# iorx65n register map
Registers from a debugger description file.
Registers are 8-bit, access not given, no defined reset value unless marked. A register's access mark holds for its fields unless they carry their own. Addresses are absolute; registers are grouped by the start of their names; lines under a group give offsets from that group; [hi:lo] are bit positions; {n}, {i} and the like mark numbered series; 'fields as' and 'values as' point back to an identical list; <NAME> marks a mode.

## SFR (part 1 of 7)
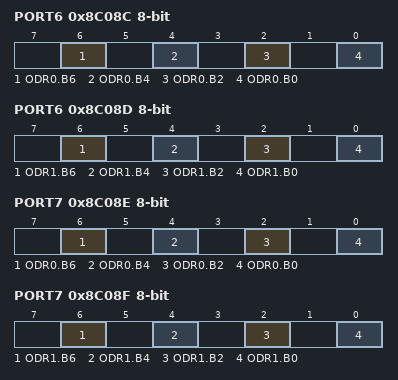
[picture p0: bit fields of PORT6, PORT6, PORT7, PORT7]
0x8C08C PORT6
  [6] ODR0.B6, [4] ODR0.B4, [2] ODR0.B2, [0] ODR0.B0
0x8C08D PORT6
  [6] ODR1.B6, [4] ODR1.B4, [2] ODR1.B2, [0] ODR1.B0
0x8C08E PORT7
  [6] ODR0.B6, [4] ODR0.B4, [2] ODR0.B2, [0] ODR0.B0
0x8C08F PORT7
  [6] ODR1.B6, [4] ODR1.B4, [2] ODR1.B2, [0] ODR1.B0
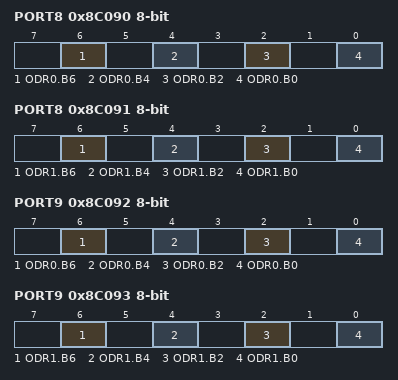
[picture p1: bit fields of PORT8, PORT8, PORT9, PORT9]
0x8C090 PORT8
  [6] ODR0.B6, [4] ODR0.B4, [2] ODR0.B2, [0] ODR0.B0
0x8C091 PORT8
  [6] ODR1.B6, [4] ODR1.B4, [2] ODR1.B2, [0] ODR1.B0
0x8C092 PORT9
  [6] ODR0.B6, [4] ODR0.B4, [2] ODR0.B2, [0] ODR0.B0
0x8C093 PORT9
  [6] ODR1.B6, [4] ODR1.B4, [2] ODR1.B2, [0] ODR1.B0
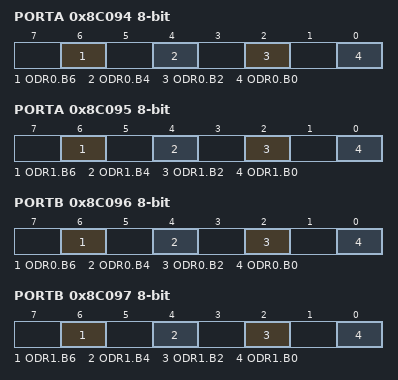
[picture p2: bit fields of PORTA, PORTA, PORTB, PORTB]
0x8C094 PORTA
  [6] ODR0.B6, [4] ODR0.B4, [2] ODR0.B2, [0] ODR0.B0
0x8C095 PORTA
  [6] ODR1.B6, [4] ODR1.B4, [2] ODR1.B2, [0] ODR1.B0
0x8C096 PORTB
  [6] ODR0.B6, [4] ODR0.B4, [2] ODR0.B2, [0] ODR0.B0
0x8C097 PORTB
  [6] ODR1.B6, [4] ODR1.B4, [2] ODR1.B2, [0] ODR1.B0
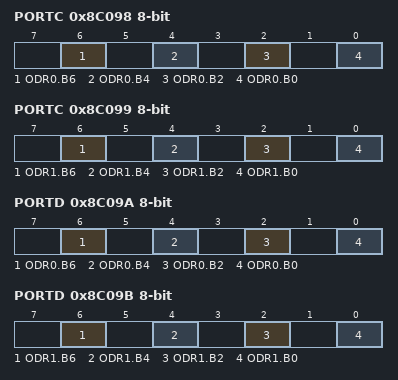
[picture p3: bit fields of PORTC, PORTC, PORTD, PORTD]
0x8C098 PORTC
  [6] ODR0.B6, [4] ODR0.B4, [2] ODR0.B2, [0] ODR0.B0
0x8C099 PORTC
  [6] ODR1.B6, [4] ODR1.B4, [2] ODR1.B2, [0] ODR1.B0
0x8C09A PORTD
  [6] ODR0.B6, [4] ODR0.B4, [2] ODR0.B2, [0] ODR0.B0
0x8C09B PORTD
  [6] ODR1.B6, [4] ODR1.B4, [2] ODR1.B2, [0] ODR1.B0
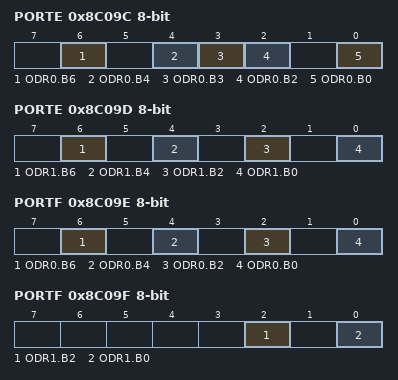
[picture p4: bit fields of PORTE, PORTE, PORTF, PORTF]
0x8C09C PORTE
  [6] ODR0.B6, [4] ODR0.B4, [3] ODR0.B3, [2] ODR0.B2, [0] ODR0.B0
0x8C09D PORTE
  [6] ODR1.B6, [4] ODR1.B4, [2] ODR1.B2, [0] ODR1.B0
0x8C09E PORTF
  [6] ODR0.B6, [4] ODR0.B4, [2] ODR0.B2, [0] ODR0.B0
0x8C09F PORTF
  [2] ODR1.B2, [0] ODR1.B0
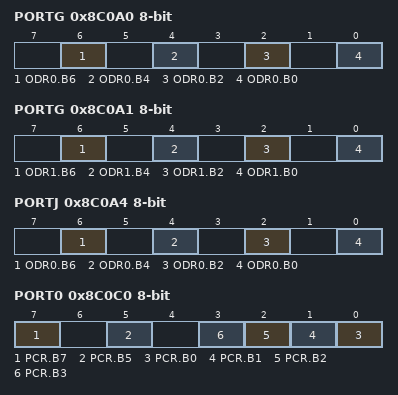
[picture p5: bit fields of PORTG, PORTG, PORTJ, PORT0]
0x8C0A0 PORTG
  [6] ODR0.B6, [4] ODR0.B4, [2] ODR0.B2, [0] ODR0.B0
0x8C0A1 PORTG
  [6] ODR1.B6, [4] ODR1.B4, [2] ODR1.B2, [0] ODR1.B0
0x8C0A4 PORTJ
  [6] ODR0.B6, [4] ODR0.B4, [2] ODR0.B2, [0] ODR0.B0
0x8C0A5 PORTJ
  [2] ODR1.B2
0x8C0C0 PORT0
  [7] PCR.B7, [5] PCR.B5, [n] PCR.B{n} (n=0..3)
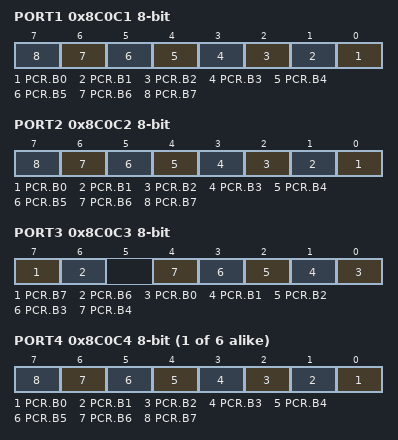
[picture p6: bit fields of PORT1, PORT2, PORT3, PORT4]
0x8C0C1 PORT1
  [n] PCR.B{n} (n=0..7)
0x8C0C2 PORT2
  [n] PCR.B{n} (n=0..7)
0x8C0C3 PORT3
  [7] PCR.B7, [6] PCR.B6, [n] PCR.B{n} (n=0..4)
{0x8C0C0+i} PORT{i} (i=4..9)
  [n] PCR.B{n} (n=0..7)
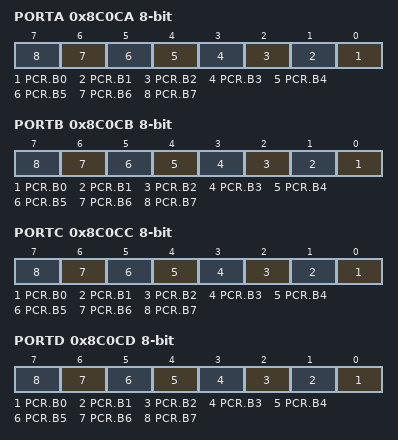
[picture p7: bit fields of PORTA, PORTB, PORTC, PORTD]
0x8C0CA PORTA
  [n] PCR.B{n} (n=0..7)
0x8C0CB PORTB
  [n] PCR.B{n} (n=0..7)
0x8C0CC PORTC
  [n] PCR.B{n} (n=0..7)
0x8C0CD PORTD
  [n] PCR.B{n} (n=0..7)
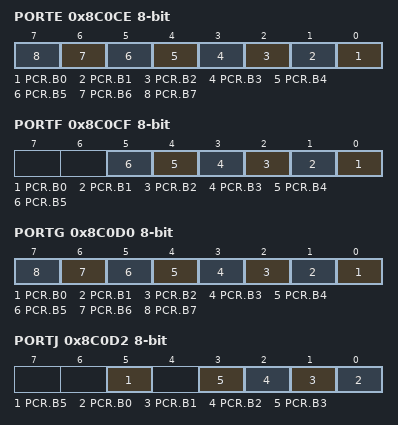
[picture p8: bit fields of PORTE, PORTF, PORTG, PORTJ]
0x8C0CE PORTE
  [n] PCR.B{n} (n=0..7)
0x8C0CF PORTF
  [n] PCR.B{n} (n=0..5)
0x8C0D0 PORTG
  [n] PCR.B{n} (n=0..7)
0x8C0D2 PORTJ
  [5] PCR.B5, [n] PCR.B{n} (n=0..3)
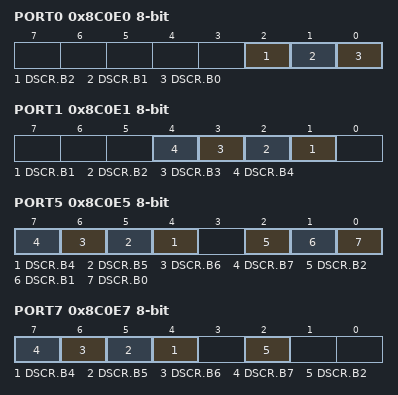
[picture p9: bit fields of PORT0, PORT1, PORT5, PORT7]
0x8C0E0 PORT0
  [2] DSCR.B2, [1] DSCR.B1, [0] DSCR.B0
0x8C0E1 PORT1
  [n] DSCR.B{n} (n=1..4)
0x8C0E2 PORT2
  [7] DSCR.B7
0x8C0E5 PORT5
  [n] DSCR.B{n} (n=4..7), [2] DSCR.B2, [1] DSCR.B1, [0] DSCR.B0
0x8C0E7 PORT7
  [n] DSCR.B{n} (n=4..7), [2] DSCR.B2
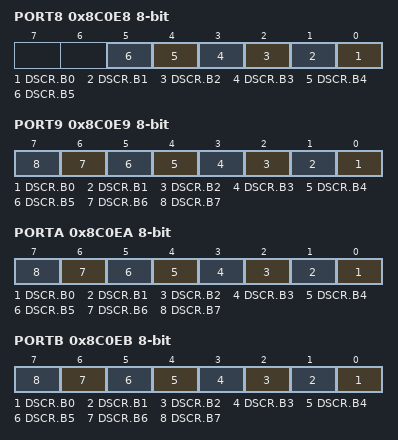
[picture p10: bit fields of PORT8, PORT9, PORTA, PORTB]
0x8C0E8 PORT8
  [n] DSCR.B{n} (n=0..5)
0x8C0E9 PORT9
  [n] DSCR.B{n} (n=0..7)
0x8C0EA PORTA
  [n] DSCR.B{n} (n=0..7)
0x8C0EB PORTB
  [n] DSCR.B{n} (n=0..7)
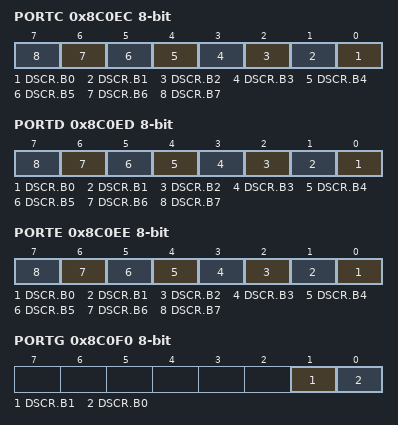
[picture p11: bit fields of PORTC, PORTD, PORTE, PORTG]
0x8C0EC PORTC
  [n] DSCR.B{n} (n=0..7)
0x8C0ED PORTD
  [n] DSCR.B{n} (n=0..7)
0x8C0EE PORTE
  [n] DSCR.B{n} (n=0..7)
0x8C0F0 PORTG
  [1] DSCR.B1, [0] DSCR.B0
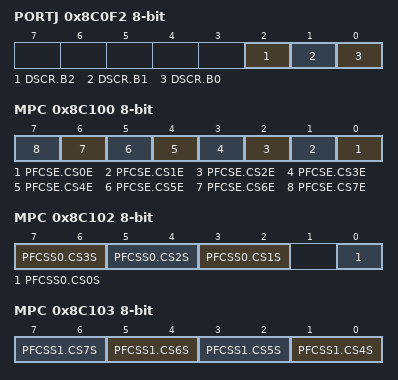
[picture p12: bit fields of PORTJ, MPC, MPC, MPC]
0x8C0F2 PORTJ
  [2] DSCR.B2, [1] DSCR.B1, [0] DSCR.B0
0x8C100 MPC
  [n] PFCSE.CS{n}E (n=0..7)
0x8C102 MPC
  [7:6] PFCSS0.CS3S, [5:4] PFCSS0.CS2S, [3:2] PFCSS0.CS1S, [0] PFCSS0.CS0S
0x8C103 MPC
  [2n-7:2n-8] PFCSS1.CS{n}S (n=4..7)
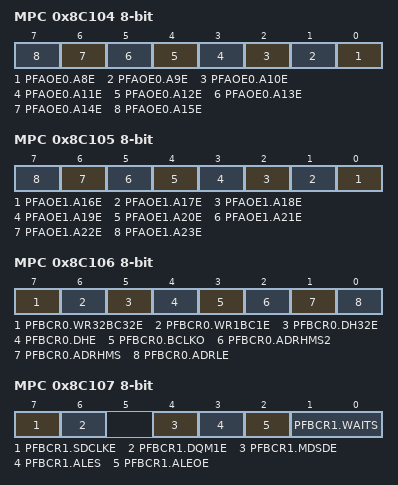
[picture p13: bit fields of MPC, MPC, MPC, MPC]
0x8C104 MPC
  [n-8] PFAOE0.A{n}E (n=8..15)
0x8C105 MPC
  [n-16] PFAOE1.A{n}E (n=16..23)
0x8C106 MPC
  [7] PFBCR0.WR32BC32E, [6] PFBCR0.WR1BC1E, [5] PFBCR0.DH32E, [4] PFBCR0.DHE, [3] PFBCR0.BCLKO, [2] PFBCR0.ADRHMS2, [1] PFBCR0.ADRHMS, [0] PFBCR0.ADRLE
0x8C107 MPC
  [7] PFBCR1.SDCLKE, [6] PFBCR1.DQM1E, [4] PFBCR1.MDSDE, [3] PFBCR1.ALES, [2] PFBCR1.ALEOE, [1:0] PFBCR1.WAITS
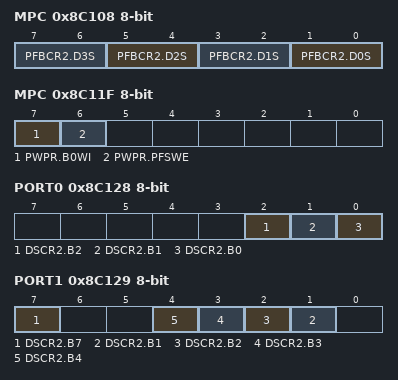
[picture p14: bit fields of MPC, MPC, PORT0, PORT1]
0x8C108 MPC
  [2n+1:2n] PFBCR2.D{n}S (n=0..3)
0x8C109 MPC
  [0] PFBCR3.DLHS
0x8C10E MPC
  [4] PFENET.PHYMODE0
0x8C11F MPC
  [7] PWPR.B0WI, [6] PWPR.PFSWE
0x8C128 PORT0
  [2] DSCR2.B2, [1] DSCR2.B1, [0] DSCR2.B0
0x8C129 PORT1
  [7] DSCR2.B7, [n] DSCR2.B{n} (n=1..4)
0x8C12A PORT2
  [7] DSCR2.B7, [n] DSCR2.B{n} (n=0..3)
0x8C12B PORT3
  [1] DSCR2.B1, [0] DSCR2.B0
0x8C12D PORT5
  [n] DSCR2.B{n} (n=0..7)
0x8C12F PORT7
  [n] DSCR2.B{n} (n=2..7), [0] DSCR2.B0
0x8C130 PORT8
  [7] DSCR2.B7, [n] DSCR2.B{n} (n=0..5)
0x8C131 PORT9
  [n] DSCR2.B{n} (n=0..7)
0x8C132 PORTA
  [n] DSCR2.B{n} (n=0..7)
0x8C133 PORTB
  [n] DSCR2.B{n} (n=0..7)
0x8C134 PORTC
  [n] DSCR2.B{n} (n=0..7)
0x8C135 PORTD
  [n] DSCR2.B{n} (n=0..7)
0x8C136 PORTE
  [n] DSCR2.B{n} (n=0..7)
0x8C138 PORTG
  [n] DSCR2.B{n} (n=0..7)
0x8C13A PORTJ
  [2] DSCR2.B2, [1] DSCR2.B1, [0] DSCR2.B0
0x8C140 MPC
  [7] P00PFS.ASEL, [6] P00PFS.ISEL, [5:0] P00PFS.PSEL
0x8C141 MPC
  [7] P01PFS.ASEL, [6] P01PFS.ISEL, [5:0] P01PFS.PSEL
0x8C142 MPC
  [7] P02PFS.ASEL, [6] P02PFS.ISEL, [5:0] P02PFS.PSEL
0x8C143 MPC
  [7] P03PFS.ASEL, [6] P03PFS.ISEL
0x8C145 MPC
  [7] P05PFS.ASEL, [6] P05PFS.ISEL
0x8C147 MPC
  [6] P07PFS.ISEL, [5:0] P07PFS.PSEL
0x8C148 MPC
  [6] P10PFS.ISEL, [5:0] P10PFS.PSEL
0x8C149 MPC
  [6] P11PFS.ISEL, [5:0] P11PFS.PSEL
0x8C14A MPC
  [6] P12PFS.ISEL, [5:0] P12PFS.PSEL
0x8C14B MPC
  [6] P13PFS.ISEL, [5:0] P13PFS.PSEL
0x8C14C MPC
  [6] P14PFS.ISEL, [5:0] P14PFS.PSEL
0x8C14D MPC
  [6] P15PFS.ISEL, [5:0] P15PFS.PSEL
0x8C14E MPC
  [6] P16PFS.ISEL, [5:0] P16PFS.PSEL
0x8C14F MPC
  [6] P17PFS.ISEL, [5:0] P17PFS.PSEL
0x8C150 MPC
  [6] P20PFS.ISEL, [5:0] P20PFS.PSEL
0x8C151 MPC
  [6] P21PFS.ISEL, [5:0] P21PFS.PSEL
0x8C152 MPC
  [5:0] P22PFS.PSEL
0x8C153 MPC
  [5:0] P23PFS.PSEL
0x8C154 MPC
  [5:0] P24PFS.PSEL
0x8C155 MPC
  [5:0] P25PFS.PSEL
0x8C156 MPC
  [5:0] P26PFS.PSEL
0x8C157 MPC
  [5:0] P27PFS.PSEL
0x8C158 MPC
  [6] P30PFS.ISEL, [5:0] P30PFS.PSEL
0x8C159 MPC
  [6] P31PFS.ISEL, [5:0] P31PFS.PSEL
0x8C15A MPC
  [6] P32PFS.ISEL, [5:0] P32PFS.PSEL
0x8C15B MPC
  [6] P33PFS.ISEL, [5:0] P33PFS.PSEL
0x8C15C MPC
  [6] P34PFS.ISEL, [5:0] P34PFS.PSEL
0x8C160 MPC
  [7] P40PFS.ASEL, [6] P40PFS.ISEL
0x8C161 MPC
  [7] P41PFS.ASEL, [6] P41PFS.ISEL
0x8C162 MPC
  [7] P42PFS.ASEL, [6] P42PFS.ISEL
0x8C163 MPC
  [7] P43PFS.ASEL, [6] P43PFS.ISEL
0x8C164 MPC
  [7] P44PFS.ASEL, [6] P44PFS.ISEL
0x8C165 MPC
  [7] P45PFS.ASEL, [6] P45PFS.ISEL
0x8C166 MPC
  [7] P46PFS.ASEL, [6] P46PFS.ISEL
0x8C167 MPC
  [7] P47PFS.ASEL, [6] P47PFS.ISEL
0x8C168 MPC
  [5:0] P50PFS.PSEL
0x8C169 MPC
  [5:0] P51PFS.PSEL
0x8C16A MPC
  [5:0] P52PFS.PSEL
0x8C16C MPC
  [5:0] P54PFS.PSEL
0x8C16D MPC
  [6] P55PFS.ISEL, [5:0] P55PFS.PSEL
0x8C16E MPC
  [5:0] P56PFS.PSEL
0x8C16F MPC
  [5:0] P57PFS.PSEL
0x8C176 MPC
  [5:0] P66PFS.PSEL
0x8C177 MPC
  [6] P67PFS.ISEL, [5:0] P67PFS.PSEL
0x8C179 MPC
  [5:0] P71PFS.PSEL
0x8C17A MPC
  [5:0] P72PFS.PSEL
0x8C17B MPC
  [5:0] P73PFS.PSEL
0x8C17C MPC
  [5:0] P74PFS.PSEL
0x8C17D MPC
  [5:0] P75PFS.PSEL
0x8C17E MPC
  [5:0] P76PFS.PSEL
0x8C17F MPC
  [5:0] P77PFS.PSEL
0x8C180 MPC
  [5:0] P80PFS.PSEL
0x8C181 MPC
  [5:0] P81PFS.PSEL
0x8C182 MPC
  [5:0] P82PFS.PSEL
0x8C183 MPC
  [5:0] P83PFS.PSEL
0x8C184 MPC
  [5:0] P84PFS.PSEL
0x8C185 MPC
  [5:0] P85PFS.PSEL
0x8C186 MPC
  [5:0] P86PFS.PSEL
0x8C187 MPC
  [5:0] P87PFS.PSEL
0x8C188 MPC
  [7] P90PFS.ASEL, [5:0] P90PFS.PSEL
0x8C189 MPC
  [7] P91PFS.ASEL, [5:0] P91PFS.PSEL
0x8C18A MPC
  [7] P92PFS.ASEL, [5:0] P92PFS.PSEL
0x8C18B MPC
  [7] P93PFS.ASEL, [5:0] P93PFS.PSEL
0x8C190 MPC
  [5:0] PA0PFS.PSEL
0x8C191 MPC
  [6] PA1PFS.ISEL, [5:0] PA1PFS.PSEL
0x8C192 MPC
  [5:0] PA2PFS.PSEL
0x8C193 MPC
  [6] PA3PFS.ISEL, [5:0] PA3PFS.PSEL
0x8C194 MPC
  [6] PA4PFS.ISEL, [5:0] PA4PFS.PSEL
0x8C195 MPC
  [5:0] PA5PFS.PSEL
0x8C196 MPC
  [5:0] PA6PFS.PSEL
0x8C197 MPC
  [5:0] PA7PFS.PSEL
0x8C198 MPC
  [6] PB0PFS.ISEL, [5:0] PB0PFS.PSEL
0x8C199 MPC
  [6] PB1PFS.ISEL, [5:0] PB1PFS.PSEL
0x8C19A MPC
  [5:0] PB2PFS.PSEL
0x8C19B MPC
  [5:0] PB3PFS.PSEL
0x8C19C MPC
  [5:0] PB4PFS.PSEL
0x8C19D MPC
  [5:0] PB5PFS.PSEL
0x8C19E MPC
  [5:0] PB6PFS.PSEL
0x8C19F MPC
  [5:0] PB7PFS.PSEL
0x8C1A0 MPC
  [6] PC0PFS.ISEL, [5:0] PC0PFS.PSEL
0x8C1A1 MPC
  [6] PC1PFS.ISEL, [5:0] PC1PFS.PSEL
0x8C1A2 MPC
  [5:0] PC2PFS.PSEL
0x8C1A3 MPC
  [5:0] PC3PFS.PSEL
0x8C1A4 MPC
  [5:0] PC4PFS.PSEL
0x8C1A5 MPC
  [5:0] PC5PFS.PSEL
0x8C1A6 MPC
  [6] PC6PFS.ISEL, [5:0] PC6PFS.PSEL
0x8C1A7 MPC
  [6] PC7PFS.ISEL, [5:0] PC7PFS.PSEL
0x8C1A8 MPC
  [7] PD0PFS.ASEL, [6] PD0PFS.ISEL, [5:0] PD0PFS.PSEL
0x8C1A9 MPC
  [7] PD1PFS.ASEL, [6] PD1PFS.ISEL, [5:0] PD1PFS.PSEL
0x8C1AA MPC
  [7] PD2PFS.ASEL, [6] PD2PFS.ISEL, [5:0] PD2PFS.PSEL
0x8C1AB MPC
  [7] PD3PFS.ASEL, [6] PD3PFS.ISEL, [5:0] PD3PFS.PSEL
0x8C1AC MPC
  [7] PD4PFS.ASEL, [6] PD4PFS.ISEL, [5:0] PD4PFS.PSEL
0x8C1AD MPC
  [7] PD5PFS.ASEL, [6] PD5PFS.ISEL, [5:0] PD5PFS.PSEL
0x8C1AE MPC
  [7] PD6PFS.ASEL, [6] PD6PFS.ISEL, [5:0] PD6PFS.PSEL
0x8C1AF MPC
  [7] PD7PFS.ASEL, [6] PD7PFS.ISEL, [5:0] PD7PFS.PSEL
0x8C1B0 MPC
  [7] PE0PFS.ASEL, [5:0] PE0PFS.PSEL
0x8C1B1 MPC
  [7] PE1PFS.ASEL, [5:0] PE1PFS.PSEL
0x8C1B2 MPC
  [7] PE2PFS.ASEL, [6] PE2PFS.ISEL, [5:0] PE2PFS.PSEL
0x8C1B3 MPC
  [7] PE3PFS.ASEL, [5:0] PE3PFS.PSEL
0x8C1B4 MPC
  [7] PE4PFS.ASEL, [5:0] PE4PFS.PSEL
0x8C1B5 MPC
  [7] PE5PFS.ASEL, [6] PE5PFS.ISEL, [5:0] PE5PFS.PSEL
0x8C1B6 MPC
  [7] PE6PFS.ASEL, [6] PE6PFS.ISEL, [5:0] PE6PFS.PSEL
0x8C1B7 MPC
  [7] PE7PFS.ASEL, [6] PE7PFS.ISEL, [5:0] PE7PFS.PSEL
0x8C1B8 MPC
  [5:0] PF0PFS.PSEL
0x8C1B9 MPC
  [5:0] PF1PFS.PSEL
0x8C1BA MPC
  [5:0] PF2PFS.PSEL
0x8C1BD MPC
  [6] PF5PFS.ISEL
0x8C1D0 MPC
  [5:0] PJ0PFS.PSEL
0x8C1D1 MPC
  [5:0] PJ1PFS.PSEL
0x8C1D2 MPC
  [5:0] PJ2PFS.PSEL
0x8C1D3 MPC
  [5:0] PJ3PFS.PSEL
0x8C1D5 MPC
  [5:0] PJ5PFS.PSEL
0x8C280 SYSTEM
  [7] DPSBYCR.DPSBY, [6] DPSBYCR.IOKEEP, [1:0] DPSBYCR.DEEPCUT
0x8C282 SYSTEM
  [n] DPSIER0.DIRQ{n}E (n=0..7)
0x8C283 SYSTEM
  [n-8] DPSIER1.DIRQ{n}E (n=8..15)
0x8C284 SYSTEM
  [7] DPSIER2.DUSBIE, [6] DPSIER2.DRIICCIE, [5] DPSIER2.DRIICDIE, [4] DPSIER2.DNMIE, [3] DPSIER2.DRTCAIE, [2] DPSIER2.DRTCIIE, [1] DPSIER2.DLVD2IE, [0] DPSIER2.DLVD1IE
0x8C285 SYSTEM
  [0] DPSIER3.DCANIE
0x8C286 SYSTEM
  [n] DPSIFR0.DIRQ{n}F (n=0..7)
0x8C287 SYSTEM
  [n-8] DPSIFR1.DIRQ{n}F (n=8..15)
0x8C288 SYSTEM
  [7] DPSIFR2.DUSBIF, [6] DPSIFR2.DRIICCIF, [5] DPSIFR2.DRIICDIF, [4] DPSIFR2.DNMIF, [3] DPSIFR2.DRTCAIF, [2] DPSIFR2.DRTCIIF, [1] DPSIFR2.DLVD2IF, [0] DPSIFR2.DLVD1IF
0x8C289 SYSTEM
  [0] DPSIFR3.DCANIF
0x8C28A SYSTEM
  [n] DPSIEGR0.DIRQ{n}EG (n=0..7)
0x8C28B SYSTEM
  [n-8] DPSIEGR1.DIRQ{n}EG (n=8..15)
0x8C28C SYSTEM
  [6] DPSIEGR2.DRIICCEG, [5] DPSIEGR2.DRIICDEG, [4] DPSIEGR2.DNMIEG, [1] DPSIEGR2.DLVD2EG, [0] DPSIEGR2.DLVD1EG
0x8C28D SYSTEM
  [0] DPSIEGR3.DCANIEG
0x8C290 SYSTEM
  [7] RSTSR0.DPSRSTF, [3] RSTSR0.LVD2RF, [2] RSTSR0.LVD1RF, [1] RSTSR0.LVD0RF, [0] RSTSR0.PORF
0x8C291 SYSTEM
  [0] RSTSR1.CWSF
0x8C293 SYSTEM
  [6] MOFCR.MOSEL, [5:4] MOFCR.MODRV2, [0] MOFCR.MOFXIN
0x8C294 SYSTEM
  [0] HOCOPCR.HOCOPCNT
0x8C296 FLASH
  [1:0] FWEPROR.FLWE
0x8C297 SYSTEM
  [6] LVCMPCR.LVD2E, [5] LVCMPCR.LVD1E
0x8C298 SYSTEM
  [7:4] LVDLVLR.LVD2LVL, [3:0] LVDLVLR.LVD1LVL
0x8C29A SYSTEM
  [7] LVD1CR0.LVD1RN, [6] LVD1CR0.LVD1RI, [5:4] LVD1CR0.LVD1FSAMP, [2] LVD1CR0.LVD1CMPE, [1] LVD1CR0.LVD1DFDIS, [0] LVD1CR0.LVD1RIE
0x8C29B SYSTEM
  [7] LVD2CR0.LVD2RN, [6] LVD2CR0.LVD2RI, [5:4] LVD2CR0.LVD2FSAMP, [2] LVD2CR0.LVD2CMPE, [1] LVD2CR0.LVD2DFDIS, [0] LVD2CR0.LVD2RIE
0x8C400 RTC
  [6] R64CNT.F1HZ, [5] R64CNT.F2HZ, [4] R64CNT.F4HZ, [3] R64CNT.F8HZ, [2] R64CNT.F16HZ, [1] R64CNT.F32HZ, [0] R64CNT.F64HZ
0x8C402 RTC
  [6:4] RSECCNT.SEC10, [3:0] RSECCNT.SEC1, [7:0] BCNT0.BCNT
0x8C404 RTC
  [6:4] RMINCNT.MIN10, [3:0] RMINCNT.MIN1, [7:0] BCNT1.BCNT
0x8C406 RTC
  [6] RHRCNT.PM, [5:4] RHRCNT.HR10, [3:0] RHRCNT.HR1, [7:0] BCNT2.BCNT
0x8C408 RTC
  [2:0] RWKCNT.DAYW, [7:0] BCNT3.BCNT
0x8C40A RTC
  [5:4] RDAYCNT.DATE10, [3:0] RDAYCNT.DATE1
0x8C40C RTC
  [4] RMONCNT.MON10, [3:0] RMONCNT.MON1
0x8C40E RTC 16-bit
  [7:4] RYRCNT.YR10, [3:0] RYRCNT.YR1
0x8C410 RTC
  [7] RSECAR.ENB, [6:4] RSECAR.SEC10, [3:0] RSECAR.SEC1, [7:0] BCNT0AR.BCNTAR
0x8C412 RTC
  [7] RMINAR.ENB, [6:4] RMINAR.MIN10, [3:0] RMINAR.MIN1, [7:0] BCNT1AR.BCNTAR
0x8C414 RTC
  [7] RHRAR.ENB, [6] RHRAR.PM, [5:4] RHRAR.HR10, [3:0] RHRAR.HR1, [7:0] BCNT2AR.BCNTAR
0x8C416 RTC
  [7] RWKAR.ENB, [2:0] RWKAR.DAYW, [7:0] BCNT3AR.BCNTAR
0x8C418 RTC
  [7] RDAYAR.ENB, [5:4] RDAYAR.DATE10, [3:0] RDAYAR.DATE1, [7:0] BCNT0AER.ENB
0x8C41A RTC
  [7] RMONAR.ENB, [4] RMONAR.MON10, [3:0] RMONAR.MON1, [7:0] BCNT1AER.ENB
0x8C41C RTC 16-bit
  [7:4] RYRAR.YR10, [3:0] RYRAR.YR1, [7:0] BCNT2AER.ENB
0x8C41E RTC
  [7] RYRAREN.ENB, [7:0] BCNT3AER.ENB
0x8C422 RTC
  [7:4] RCR1.PES, [3] RCR1.RTCOS, [2] RCR1.PIE, [1] RCR1.CIE, [0] RCR1.AIE
0x8C424 RTC
  [7] RCR2.CNTMD, [6] RCR2.HR24, [5] RCR2.AADJP, [4] RCR2.AADJE, [3] RCR2.RTCOE, [2] RCR2.ADJ30, [1] RCR2.RESET, [0] RCR2.START
0x8C426 RTC
  [3:1] RCR3.RTCDV, [0] RCR3.RTCEN
0x8C428 RTC
  [0] RCR4.RCKSEL
0x8C42A RTC 16-bit
  [0] RFRH.RFC
0x8C42C RTC 16-bit
  [15:0] RFRL.RFC
0x8C42E RTC
  [7:6] RADJ.PMADJ, [5:0] RADJ.ADJ
0x8C440 RTC
  [7] RTCCR0.TCEN, [5:4] RTCCR0.TCNF, [2] RTCCR0.TCST, [1:0] RTCCR0.TCCT
0x8C442 RTC
  [7] RTCCR1.TCEN, [5:4] RTCCR1.TCNF, [2] RTCCR1.TCST, [1:0] RTCCR1.TCCT
0x8C444 RTC
  [7] RTCCR2.TCEN, [5:4] RTCCR2.TCNF, [2] RTCCR2.TCST, [1:0] RTCCR2.TCCT
0x8C452 RTC
  [6:4] RSECCP0.SEC10, [3:0] RSECCP0.SEC1, [7:0] BCNT0CP0.BCNTCP0
0x8C454 RTC
  [6:4] RMINCP0.MIN10, [3:0] RMINCP0.MIN1, [7:0] BCNT1CP0.BCNTCP0
0x8C456 RTC
  [6] RHRCP0.PM, [5:4] RHRCP0.HR10, [3:0] RHRCP0.HR1, [7:0] BCNT2CP0.BCNTCP0
0x8C45A RTC
  [5:4] RDAYCP0.DATE10, [3:0] RDAYCP0.DATE1, [7:0] BCNT3CP0.BCNTCP0
0x8C45C RTC
  [4] RMONCP0.MON10, [3:0] RMONCP0.MON1
0x8C462 RTC
  [6:4] RSECCP1.SEC10, [3:0] RSECCP1.SEC1, [7:0] BCNT0CP1.BCNTCP1
0x8C464 RTC
  [6:4] RMINCP1.MIN10, [3:0] RMINCP1.MIN1, [7:0] BCNT1CP1.BCNTCP1
0x8C466 RTC
  [6] RHRCP1.PM, [5:4] RHRCP1.HR10, [3:0] RHRCP1.HR1, [7:0] BCNT2CP1.BCNTCP1
0x8C46A RTC
  [5:4] RDAYCP1.DATE10, [3:0] RDAYCP1.DATE1, [7:0] BCNT3CP1.BCNTCP1
0x8C46C RTC
  [4] RMONCP1.MON10, [3:0] RMONCP1.MON1
0x8C472 RTC
  [6:4] RSECCP2.SEC10, [3:0] RSECCP2.SEC1, [7:0] BCNT0CP2.BCNTCP2
0x8C474 RTC
  [6:4] RMINCP2.MIN10, [3:0] RMINCP2.MIN1, [7:0] BCNT1CP2.BCNTCP2
0x8C476 RTC
  [6] RHRCP2.PM, [5:4] RHRCP2.HR10, [3:0] RHRCP2.HR1, [7:0] BCNT2CP2.BCNTCP2
0x8C47A RTC
  [5:4] RDAYCP2.DATE10, [3:0] RDAYCP2.DATE1, [7:0] BCNT3CP2.BCNTCP2
0x8C47C RTC
  [4] RMONCP2.MON10, [3:0] RMONCP2.MON1
0x8C4C0 POE3 16-bit
  [12] ICSR1.POE0F, [8] ICSR1.PIE1, [1:0] ICSR1.POE0M
0x8C4C2 POE3 16-bit
  [15] OCSR1.OSF1, [9] OCSR1.OCE1, [8] OCSR1.OIE1
0x8C4C4 POE3 16-bit
  [12] ICSR2.POE4F, [8] ICSR2.PIE2, [1:0] ICSR2.POE4M
0x8C4C6 POE3 16-bit
  [15] OCSR2.OSF2, [9] OCSR2.OCE2, [8] OCSR2.OIE2
0x8C4C8 POE3 16-bit
  [12] ICSR3.POE8F, [9] ICSR3.POE8E, [8] ICSR3.PIE3, [1:0] ICSR3.POE8M
0x8C4CA POE3
  [2] SPOER.MTUCH0HIZ, [1] SPOER.MTUCH67HIZ, [0] SPOER.MTUCH34HIZ
0x8C4CB POE3
  [3] POECR1.MTU0DZE, [2] POECR1.MTU0CZE, [1] POECR1.MTU0BZE, [0] POECR1.MTU0AZE
0x8C4CC POE3 16-bit
  [10] POECR2.MTU3BDZE, [9] POECR2.MTU4ACZE, [8] POECR2.MTU4BDZE, [2] POECR2.MTU6BDZE, [1] POECR2.MTU7ACZE, [0] POECR2.MTU7BDZE
0x8C4D0 POE3 16-bit
  [13] POECR4.IC5ADDMT67ZE, [12] POECR4.IC4ADDMT67ZE, [11] POECR4.IC3ADDMT67ZE, [9] POECR4.IC1ADDMT67ZE, [n] POECR4.IC{n}ADDMT34ZE (n=2..5)
0x8C4D2 POE3 16-bit
  [5] POECR5.IC5ADDMT0ZE, [4] POECR5.IC4ADDMT0ZE, [2] POECR5.IC2ADDMT0ZE, [1] POECR5.IC1ADDMT0ZE
0x8C4D6 POE3 16-bit
  [12] ICSR4.POE10F, [9] ICSR4.POE10E, [8] ICSR4.PIE4, [1:0] ICSR4.POE10M
0x8C4D8 POE3 16-bit
  [12] ICSR5.POE11F, [9] ICSR5.POE11E, [8] ICSR5.PIE5, [1:0] ICSR5.POE11M
0x8C4DA POE3 16-bit
  [7] ALR1.OLSEN, [5] ALR1.OLSG2B, [4] ALR1.OLSG2A, [3] ALR1.OLSG1B, [2] ALR1.OLSG1A, [1] ALR1.OLSG0B, [0] ALR1.OLSG0A
0x8C4DC POE3 16-bit
  [12] ICSR6.OSTSTF, [9] ICSR6.OSTSTE
0x8C4E4 POE3
  [7:4] M0SELR1.M0BSEL, [3:0] M0SELR1.M0ASEL
0x8C4E5 POE3
  [7:4] M0SELR2.M0DSEL, [3:0] M0SELR2.M0CSEL
0x8C4E6 POE3
  [7:4] M3SELR.M3DSEL, [3:0] M3SELR.M3BSEL
0x8C4E7 POE3
  [7:4] M4SELR1.M4CSEL, [3:0] M4SELR1.M4ASEL
0x8C4E8 POE3
  [7:4] M4SELR2.M4DSEL, [3:0] M4SELR2.M4BSEL
0x8C4EA POE3
  [7:4] M6SELR.M6DSEL, [3:0] M6SELR.M6BSEL
0x8C500 TEMPS
  [7] TSCR.TSEN, [4] TSCR.TSOE
0x8C5C0 DA
  [1] DAADUSR.AMADSEL1
0x90200 CAN0 32-bit
  [31] MB[0]_ID.IDE, [30] MB[0]_ID.RTR, [28:18] MB[0]_ID.SID, [17:0] MB[0]_ID.EID
0x90210 CAN0 32-bit
  [31] MB[1]_ID.IDE, [30] MB[1]_ID.RTR, [28:18] MB[1]_ID.SID, [17:0] MB[1]_ID.EID
0x90220 CAN0 32-bit
  [31] MB[2]_ID.IDE, [30] MB[2]_ID.RTR, [28:18] MB[2]_ID.SID, [17:0] MB[2]_ID.EID
0x90230 CAN0 32-bit
  [31] MB[3]_ID.IDE, [30] MB[3]_ID.RTR, [28:18] MB[3]_ID.SID, [17:0] MB[3]_ID.EID
0x90240 CAN0 32-bit
  [31] MB[4]_ID.IDE, [30] MB[4]_ID.RTR, [28:18] MB[4]_ID.SID, [17:0] MB[4]_ID.EID
0x90250 CAN0 32-bit
  [31] MB[5]_ID.IDE, [30] MB[5]_ID.RTR, [28:18] MB[5]_ID.SID, [17:0] MB[5]_ID.EID
0x90260 CAN0 32-bit
  [31] MB[6]_ID.IDE, [30] MB[6]_ID.RTR, [28:18] MB[6]_ID.SID, [17:0] MB[6]_ID.EID
0x90270 CAN0 32-bit
  [31] MB[7]_ID.IDE, [30] MB[7]_ID.RTR, [28:18] MB[7]_ID.SID, [17:0] MB[7]_ID.EID
0x90280 CAN0 32-bit
  [31] MB[8]_ID.IDE, [30] MB[8]_ID.RTR, [28:18] MB[8]_ID.SID, [17:0] MB[8]_ID.EID
0x90290 CAN0 32-bit
  [31] MB[9]_ID.IDE, [30] MB[9]_ID.RTR, [28:18] MB[9]_ID.SID, [17:0] MB[9]_ID.EID
0x902A0 CAN0 32-bit
  [31] MB[10]_ID.IDE, [30] MB[10]_ID.RTR, [28:18] MB[10]_ID.SID, [17:0] MB[10]_ID.EID
0x902B0 CAN0 32-bit
  [31] MB[11]_ID.IDE, [30] MB[11]_ID.RTR, [28:18] MB[11]_ID.SID, [17:0] MB[11]_ID.EID
0x902C0 CAN0 32-bit
  [31] MB[12]_ID.IDE, [30] MB[12]_ID.RTR, [28:18] MB[12]_ID.SID, [17:0] MB[12]_ID.EID
0x902D0 CAN0 32-bit
  [31] MB[13]_ID.IDE, [30] MB[13]_ID.RTR, [28:18] MB[13]_ID.SID, [17:0] MB[13]_ID.EID
0x902E0 CAN0 32-bit
  [31] MB[14]_ID.IDE, [30] MB[14]_ID.RTR, [28:18] MB[14]_ID.SID, [17:0] MB[14]_ID.EID
0x902F0 CAN0 32-bit
  [31] MB[15]_ID.IDE, [30] MB[15]_ID.RTR, [28:18] MB[15]_ID.SID, [17:0] MB[15]_ID.EID
0x90300 CAN0 32-bit
  [31] MB[16]_ID.IDE, [30] MB[16]_ID.RTR, [28:18] MB[16]_ID.SID, [17:0] MB[16]_ID.EID
0x90310 CAN0 32-bit
  [31] MB[17]_ID.IDE, [30] MB[17]_ID.RTR, [28:18] MB[17]_ID.SID, [17:0] MB[17]_ID.EID
0x90320 CAN0 32-bit
  [31] MB[18]_ID.IDE, [30] MB[18]_ID.RTR, [28:18] MB[18]_ID.SID, [17:0] MB[18]_ID.EID
0x90330 CAN0 32-bit
  [31] MB[19]_ID.IDE, [30] MB[19]_ID.RTR, [28:18] MB[19]_ID.SID, [17:0] MB[19]_ID.EID
0x90340 CAN0 32-bit
  [31] MB[20]_ID.IDE, [30] MB[20]_ID.RTR, [28:18] MB[20]_ID.SID, [17:0] MB[20]_ID.EID
0x90350 CAN0 32-bit
  [31] MB[21]_ID.IDE, [30] MB[21]_ID.RTR, [28:18] MB[21]_ID.SID, [17:0] MB[21]_ID.EID
0x90360 CAN0 32-bit
  [31] MB[22]_ID.IDE, [30] MB[22]_ID.RTR, [28:18] MB[22]_ID.SID, [17:0] MB[22]_ID.EID
0x90370 CAN0 32-bit
  [31] MB[23]_ID.IDE, [30] MB[23]_ID.RTR, [28:18] MB[23]_ID.SID, [17:0] MB[23]_ID.EID
0x90380 CAN0 32-bit
  [31] MB[24]_ID.IDE, [30] MB[24]_ID.RTR, [28:18] MB[24]_ID.SID, [17:0] MB[24]_ID.EID
0x90390 CAN0 32-bit
  [31] MB[25]_ID.IDE, [30] MB[25]_ID.RTR, [28:18] MB[25]_ID.SID, [17:0] MB[25]_ID.EID
0x903A0 CAN0 32-bit
  [31] MB[26]_ID.IDE, [30] MB[26]_ID.RTR, [28:18] MB[26]_ID.SID, [17:0] MB[26]_ID.EID
0x903B0 CAN0 32-bit
  [31] MB[27]_ID.IDE, [30] MB[27]_ID.RTR, [28:18] MB[27]_ID.SID, [17:0] MB[27]_ID.EID
0x903C0 CAN0 32-bit
  [31] MB[28]_ID.IDE, [30] MB[28]_ID.RTR, [28:18] MB[28]_ID.SID, [17:0] MB[28]_ID.EID
0x903D0 CAN0 32-bit
  [31] MB[29]_ID.IDE, [30] MB[29]_ID.RTR, [28:18] MB[29]_ID.SID, [17:0] MB[29]_ID.EID
0x903E0 CAN0 32-bit
  [31] MB[30]_ID.IDE, [30] MB[30]_ID.RTR, [28:18] MB[30]_ID.SID, [17:0] MB[30]_ID.EID
0x903F0 CAN0 32-bit
  [31] MB[31]_ID.IDE, [30] MB[31]_ID.RTR, [28:18] MB[31]_ID.SID, [17:0] MB[31]_ID.EID
0x90400 CAN0 32-bit
  [28:18] MKR[0].SID, [17:0] MKR[0].EID
0x90404 CAN0 32-bit
  [28:18] MKR[1].SID, [17:0] MKR[1].EID
0x90408 CAN0 32-bit
  [28:18] MKR[2].SID, [17:0] MKR[2].EID
0x9040C CAN0 32-bit
  [28:18] MKR[3].SID, [17:0] MKR[3].EID
0x90410 CAN0 32-bit
  [28:18] MKR[4].SID, [17:0] MKR[4].EID
0x90414 CAN0 32-bit
  [28:18] MKR[5].SID, [17:0] MKR[5].EID
0x90418 CAN0 32-bit
  [28:18] MKR[6].SID, [17:0] MKR[6].EID
0x9041C CAN0 32-bit
  [28:18] MKR[7].SID, [17:0] MKR[7].EID
0x90420 CAN0 32-bit
  [31] FIDCR0.IDE, [30] FIDCR0.RTR, [28:18] FIDCR0.SID, [17:0] FIDCR0.EID
0x90424 CAN0 32-bit
  [31] FIDCR1.IDE, [30] FIDCR1.RTR, [28:18] FIDCR1.SID, [17:0] FIDCR1.EID
0x90428 CAN0 32-bit
  [n] MKIVLR.MB{n} (n=0..31)
0x9042C CAN0 32-bit
  [n] MIER.MB{n} (n=0..31)
0x90820 CAN0
  [7] MCTL[0]_TX.TRMREQ, [7] MCTL[0]_RX.TRMREQ, [6] MCTL[0]_TX.RECREQ, [6] MCTL[0]_RX.RECREQ, [4] MCTL[0]_TX.ONESHOT, [4] MCTL[0]_RX.ONESHOT, [2] MCTL[0]_TX.TRMABT, [2] MCTL[0]_RX.MSGLOST, [1] MCTL[0]_TX.TRMACTIVE, [1] MCTL[0]_RX.INVALDATA, [0] MCTL[0]_TX.SENTDATA, [0] MCTL[0]_RX.NEWDATA
0x90821 CAN0
  [7] MCTL[1]_TX.TRMREQ, [7] MCTL[1]_RX.TRMREQ, [6] MCTL[1]_TX.RECREQ, [6] MCTL[1]_RX.RECREQ, [4] MCTL[1]_TX.ONESHOT, [4] MCTL[1]_RX.ONESHOT, [2] MCTL[1]_TX.TRMABT, [2] MCTL[1]_RX.MSGLOST, [1] MCTL[1]_TX.TRMACTIVE, [1] MCTL[1]_RX.INVALDATA, [0] MCTL[1]_TX.SENTDATA, [0] MCTL[1]_RX.NEWDATA
0x90822 CAN0
  [7] MCTL[2]_TX.TRMREQ, [7] MCTL[2]_RX.TRMREQ, [6] MCTL[2]_TX.RECREQ, [6] MCTL[2]_RX.RECREQ, [4] MCTL[2]_TX.ONESHOT, [4] MCTL[2]_RX.ONESHOT, [2] MCTL[2]_TX.TRMABT, [2] MCTL[2]_RX.MSGLOST, [1] MCTL[2]_TX.TRMACTIVE, [1] MCTL[2]_RX.INVALDATA, [0] MCTL[2]_TX.SENTDATA, [0] MCTL[2]_RX.NEWDATA
0x90823 CAN0
  [7] MCTL[3]_TX.TRMREQ, [7] MCTL[3]_RX.TRMREQ, [6] MCTL[3]_TX.RECREQ, [6] MCTL[3]_RX.RECREQ, [4] MCTL[3]_TX.ONESHOT, [4] MCTL[3]_RX.ONESHOT, [2] MCTL[3]_TX.TRMABT, [2] MCTL[3]_RX.MSGLOST, [1] MCTL[3]_TX.TRMACTIVE, [1] MCTL[3]_RX.INVALDATA, [0] MCTL[3]_TX.SENTDATA, [0] MCTL[3]_RX.NEWDATA
0x90824 CAN0
  [7] MCTL[4]_TX.TRMREQ, [7] MCTL[4]_RX.TRMREQ, [6] MCTL[4]_TX.RECREQ, [6] MCTL[4]_RX.RECREQ, [4] MCTL[4]_TX.ONESHOT, [4] MCTL[4]_RX.ONESHOT, [2] MCTL[4]_TX.TRMABT, [2] MCTL[4]_RX.MSGLOST, [1] MCTL[4]_TX.TRMACTIVE, [1] MCTL[4]_RX.INVALDATA, [0] MCTL[4]_TX.SENTDATA, [0] MCTL[4]_RX.NEWDATA
0x90825 CAN0
  [7] MCTL[5]_TX.TRMREQ, [7] MCTL[5]_RX.TRMREQ, [6] MCTL[5]_TX.RECREQ, [6] MCTL[5]_RX.RECREQ, [4] MCTL[5]_TX.ONESHOT, [4] MCTL[5]_RX.ONESHOT, [2] MCTL[5]_TX.TRMABT, [2] MCTL[5]_RX.MSGLOST, [1] MCTL[5]_TX.TRMACTIVE, [1] MCTL[5]_RX.INVALDATA, [0] MCTL[5]_TX.SENTDATA, [0] MCTL[5]_RX.NEWDATA
0x90826 CAN0
  [7] MCTL[6]_TX.TRMREQ, [7] MCTL[6]_RX.TRMREQ, [6] MCTL[6]_TX.RECREQ, [6] MCTL[6]_RX.RECREQ, [4] MCTL[6]_TX.ONESHOT, [4] MCTL[6]_RX.ONESHOT, [2] MCTL[6]_TX.TRMABT, [2] MCTL[6]_RX.MSGLOST, [1] MCTL[6]_TX.TRMACTIVE, [1] MCTL[6]_RX.INVALDATA, [0] MCTL[6]_TX.SENTDATA, [0] MCTL[6]_RX.NEWDATA
0x90827 CAN0
  [7] MCTL[7]_TX.TRMREQ, [7] MCTL[7]_RX.TRMREQ, [6] MCTL[7]_TX.RECREQ, [6] MCTL[7]_RX.RECREQ, [4] MCTL[7]_TX.ONESHOT, [4] MCTL[7]_RX.ONESHOT, [2] MCTL[7]_TX.TRMABT, [2] MCTL[7]_RX.MSGLOST, [1] MCTL[7]_TX.TRMACTIVE, [1] MCTL[7]_RX.INVALDATA, [0] MCTL[7]_TX.SENTDATA, [0] MCTL[7]_RX.NEWDATA
0x90828 CAN0
  [7] MCTL[8]_TX.TRMREQ, [7] MCTL[8]_RX.TRMREQ, [6] MCTL[8]_TX.RECREQ, [6] MCTL[8]_RX.RECREQ, [4] MCTL[8]_TX.ONESHOT, [4] MCTL[8]_RX.ONESHOT, [2] MCTL[8]_TX.TRMABT, [2] MCTL[8]_RX.MSGLOST, [1] MCTL[8]_TX.TRMACTIVE, [1] MCTL[8]_RX.INVALDATA, [0] MCTL[8]_TX.SENTDATA, [0] MCTL[8]_RX.NEWDATA
0x90829 CAN0
  [7] MCTL[9]_TX.TRMREQ, [7] MCTL[9]_RX.TRMREQ, [6] MCTL[9]_TX.RECREQ, [6] MCTL[9]_RX.RECREQ, [4] MCTL[9]_TX.ONESHOT, [4] MCTL[9]_RX.ONESHOT, [2] MCTL[9]_TX.TRMABT, [2] MCTL[9]_RX.MSGLOST, [1] MCTL[9]_TX.TRMACTIVE, [1] MCTL[9]_RX.INVALDATA, [0] MCTL[9]_TX.SENTDATA, [0] MCTL[9]_RX.NEWDATA
0x9082A CAN0
  [7] MCTL[10]_TX.TRMREQ, [7] MCTL[10]_RX.TRMREQ, [6] MCTL[10]_TX.RECREQ, [6] MCTL[10]_RX.RECREQ, [4] MCTL[10]_TX.ONESHOT, [4] MCTL[10]_RX.ONESHOT, [2] MCTL[10]_TX.TRMABT, [2] MCTL[10]_RX.MSGLOST, [1] MCTL[10]_TX.TRMACTIVE, [1] MCTL[10]_RX.INVALDATA, [0] MCTL[10]_TX.SENTDATA, [0] MCTL[10]_RX.NEWDATA
0x9082B CAN0
  [7] MCTL[11]_TX.TRMREQ, [7] MCTL[11]_RX.TRMREQ, [6] MCTL[11]_TX.RECREQ, [6] MCTL[11]_RX.RECREQ, [4] MCTL[11]_TX.ONESHOT, [4] MCTL[11]_RX.ONESHOT, [2] MCTL[11]_TX.TRMABT, [2] MCTL[11]_RX.MSGLOST, [1] MCTL[11]_TX.TRMACTIVE, [1] MCTL[11]_RX.INVALDATA, [0] MCTL[11]_TX.SENTDATA, [0] MCTL[11]_RX.NEWDATA
0x9082C CAN0
  [7] MCTL[12]_TX.TRMREQ, [7] MCTL[12]_RX.TRMREQ, [6] MCTL[12]_TX.RECREQ, [6] MCTL[12]_RX.RECREQ, [4] MCTL[12]_TX.ONESHOT, [4] MCTL[12]_RX.ONESHOT, [2] MCTL[12]_TX.TRMABT, [2] MCTL[12]_RX.MSGLOST, [1] MCTL[12]_TX.TRMACTIVE, [1] MCTL[12]_RX.INVALDATA, [0] MCTL[12]_TX.SENTDATA, [0] MCTL[12]_RX.NEWDATA
0x9082D CAN0
  [7] MCTL[13]_TX.TRMREQ, [7] MCTL[13]_RX.TRMREQ, [6] MCTL[13]_TX.RECREQ, [6] MCTL[13]_RX.RECREQ, [4] MCTL[13]_TX.ONESHOT, [4] MCTL[13]_RX.ONESHOT, [2] MCTL[13]_TX.TRMABT, [2] MCTL[13]_RX.MSGLOST, [1] MCTL[13]_TX.TRMACTIVE, [1] MCTL[13]_RX.INVALDATA, [0] MCTL[13]_TX.SENTDATA, [0] MCTL[13]_RX.NEWDATA
0x9082E CAN0
  [7] MCTL[14]_TX.TRMREQ, [7] MCTL[14]_RX.TRMREQ, [6] MCTL[14]_TX.RECREQ, [6] MCTL[14]_RX.RECREQ, [4] MCTL[14]_TX.ONESHOT, [4] MCTL[14]_RX.ONESHOT, [2] MCTL[14]_TX.TRMABT, [2] MCTL[14]_RX.MSGLOST, [1] MCTL[14]_TX.TRMACTIVE, [1] MCTL[14]_RX.INVALDATA, [0] MCTL[14]_TX.SENTDATA, [0] MCTL[14]_RX.NEWDATA
0x9082F CAN0
  [7] MCTL[15]_TX.TRMREQ, [7] MCTL[15]_RX.TRMREQ, [6] MCTL[15]_TX.RECREQ, [6] MCTL[15]_RX.RECREQ, [4] MCTL[15]_TX.ONESHOT, [4] MCTL[15]_RX.ONESHOT, [2] MCTL[15]_TX.TRMABT, [2] MCTL[15]_RX.MSGLOST, [1] MCTL[15]_TX.TRMACTIVE, [1] MCTL[15]_RX.INVALDATA, [0] MCTL[15]_TX.SENTDATA, [0] MCTL[15]_RX.NEWDATA
0x90830 CAN0
  [7] MCTL[16]_TX.TRMREQ, [7] MCTL[16]_RX.TRMREQ, [6] MCTL[16]_TX.RECREQ, [6] MCTL[16]_RX.RECREQ, [4] MCTL[16]_TX.ONESHOT, [4] MCTL[16]_RX.ONESHOT, [2] MCTL[16]_TX.TRMABT, [2] MCTL[16]_RX.MSGLOST, [1] MCTL[16]_TX.TRMACTIVE, [1] MCTL[16]_RX.INVALDATA, [0] MCTL[16]_TX.SENTDATA, [0] MCTL[16]_RX.NEWDATA
0x90831 CAN0
  [7] MCTL[17]_TX.TRMREQ, [7] MCTL[17]_RX.TRMREQ, [6] MCTL[17]_TX.RECREQ, [6] MCTL[17]_RX.RECREQ, [4] MCTL[17]_TX.ONESHOT, [4] MCTL[17]_RX.ONESHOT, [2] MCTL[17]_TX.TRMABT, [2] MCTL[17]_RX.MSGLOST, [1] MCTL[17]_TX.TRMACTIVE, [1] MCTL[17]_RX.INVALDATA, [0] MCTL[17]_TX.SENTDATA, [0] MCTL[17]_RX.NEWDATA
0x90832 CAN0
  [7] MCTL[18]_TX.TRMREQ, [7] MCTL[18]_RX.TRMREQ, [6] MCTL[18]_TX.RECREQ, [6] MCTL[18]_RX.RECREQ, [4] MCTL[18]_TX.ONESHOT, [4] MCTL[18]_RX.ONESHOT, [2] MCTL[18]_TX.TRMABT, [2] MCTL[18]_RX.MSGLOST, [1] MCTL[18]_TX.TRMACTIVE, [1] MCTL[18]_RX.INVALDATA, [0] MCTL[18]_TX.SENTDATA, [0] MCTL[18]_RX.NEWDATA
0x90833 CAN0
  [7] MCTL[19]_TX.TRMREQ, [7] MCTL[19]_RX.TRMREQ, [6] MCTL[19]_TX.RECREQ, [6] MCTL[19]_RX.RECREQ, [4] MCTL[19]_TX.ONESHOT, [4] MCTL[19]_RX.ONESHOT, [2] MCTL[19]_TX.TRMABT, [2] MCTL[19]_RX.MSGLOST, [1] MCTL[19]_TX.TRMACTIVE, [1] MCTL[19]_RX.INVALDATA, [0] MCTL[19]_TX.SENTDATA, [0] MCTL[19]_RX.NEWDATA
0x90834 CAN0
  [7] MCTL[20]_TX.TRMREQ, [7] MCTL[20]_RX.TRMREQ, [6] MCTL[20]_TX.RECREQ, [6] MCTL[20]_RX.RECREQ, [4] MCTL[20]_TX.ONESHOT, [4] MCTL[20]_RX.ONESHOT, [2] MCTL[20]_TX.TRMABT, [2] MCTL[20]_RX.MSGLOST, [1] MCTL[20]_TX.TRMACTIVE, [1] MCTL[20]_RX.INVALDATA, [0] MCTL[20]_TX.SENTDATA, [0] MCTL[20]_RX.NEWDATA
0x90835 CAN0
  [7] MCTL[21]_TX.TRMREQ, [7] MCTL[21]_RX.TRMREQ, [6] MCTL[21]_TX.RECREQ, [6] MCTL[21]_RX.RECREQ, [4] MCTL[21]_TX.ONESHOT, [4] MCTL[21]_RX.ONESHOT, [2] MCTL[21]_TX.TRMABT, [2] MCTL[21]_RX.MSGLOST, [1] MCTL[21]_TX.TRMACTIVE, [1] MCTL[21]_RX.INVALDATA, [0] MCTL[21]_TX.SENTDATA, [0] MCTL[21]_RX.NEWDATA
0x90836 CAN0
  [7] MCTL[22]_TX.TRMREQ, [7] MCTL[22]_RX.TRMREQ, [6] MCTL[22]_TX.RECREQ, [6] MCTL[22]_RX.RECREQ, [4] MCTL[22]_TX.ONESHOT, [4] MCTL[22]_RX.ONESHOT, [2] MCTL[22]_TX.TRMABT, [2] MCTL[22]_RX.MSGLOST, [1] MCTL[22]_TX.TRMACTIVE, [1] MCTL[22]_RX.INVALDATA, [0] MCTL[22]_TX.SENTDATA, [0] MCTL[22]_RX.NEWDATA
0x90837 CAN0
  [7] MCTL[23]_TX.TRMREQ, [7] MCTL[23]_RX.TRMREQ, [6] MCTL[23]_TX.RECREQ, [6] MCTL[23]_RX.RECREQ, [4] MCTL[23]_TX.ONESHOT, [4] MCTL[23]_RX.ONESHOT, [2] MCTL[23]_TX.TRMABT, [2] MCTL[23]_RX.MSGLOST, [1] MCTL[23]_TX.TRMACTIVE, [1] MCTL[23]_RX.INVALDATA, [0] MCTL[23]_TX.SENTDATA, [0] MCTL[23]_RX.NEWDATA
0x90838 CAN0
  [7] MCTL[24]_TX.TRMREQ, [7] MCTL[24]_RX.TRMREQ, [6] MCTL[24]_TX.RECREQ, [6] MCTL[24]_RX.RECREQ, [4] MCTL[24]_TX.ONESHOT, [4] MCTL[24]_RX.ONESHOT, [2] MCTL[24]_TX.TRMABT, [2] MCTL[24]_RX.MSGLOST, [1] MCTL[24]_TX.TRMACTIVE, [1] MCTL[24]_RX.INVALDATA, [0] MCTL[24]_TX.SENTDATA, [0] MCTL[24]_RX.NEWDATA
0x90839 CAN0
  [7] MCTL[25]_TX.TRMREQ, [7] MCTL[25]_RX.TRMREQ, [6] MCTL[25]_TX.RECREQ, [6] MCTL[25]_RX.RECREQ, [4] MCTL[25]_TX.ONESHOT, [4] MCTL[25]_RX.ONESHOT, [2] MCTL[25]_TX.TRMABT, [2] MCTL[25]_RX.MSGLOST, [1] MCTL[25]_TX.TRMACTIVE, [1] MCTL[25]_RX.INVALDATA, [0] MCTL[25]_TX.SENTDATA, [0] MCTL[25]_RX.NEWDATA
0x9083A CAN0
  [7] MCTL[26]_TX.TRMREQ, [7] MCTL[26]_RX.TRMREQ, [6] MCTL[26]_TX.RECREQ, [6] MCTL[26]_RX.RECREQ, [4] MCTL[26]_TX.ONESHOT, [4] MCTL[26]_RX.ONESHOT, [2] MCTL[26]_TX.TRMABT, [2] MCTL[26]_RX.MSGLOST, [1] MCTL[26]_TX.TRMACTIVE, [1] MCTL[26]_RX.INVALDATA, [0] MCTL[26]_TX.SENTDATA, [0] MCTL[26]_RX.NEWDATA
0x9083B CAN0
  [7] MCTL[27]_TX.TRMREQ, [7] MCTL[27]_RX.TRMREQ, [6] MCTL[27]_TX.RECREQ, [6] MCTL[27]_RX.RECREQ, [4] MCTL[27]_TX.ONESHOT, [4] MCTL[27]_RX.ONESHOT, [2] MCTL[27]_TX.TRMABT, [2] MCTL[27]_RX.MSGLOST, [1] MCTL[27]_TX.TRMACTIVE, [1] MCTL[27]_RX.INVALDATA, [0] MCTL[27]_TX.SENTDATA, [0] MCTL[27]_RX.NEWDATA
0x9083C CAN0
  [7] MCTL[28]_TX.TRMREQ, [7] MCTL[28]_RX.TRMREQ, [6] MCTL[28]_TX.RECREQ, [6] MCTL[28]_RX.RECREQ, [4] MCTL[28]_TX.ONESHOT, [4] MCTL[28]_RX.ONESHOT, [2] MCTL[28]_TX.TRMABT, [2] MCTL[28]_RX.MSGLOST, [1] MCTL[28]_TX.TRMACTIVE, [1] MCTL[28]_RX.INVALDATA, [0] MCTL[28]_TX.SENTDATA, [0] MCTL[28]_RX.NEWDATA
0x9083D CAN0
  [7] MCTL[29]_TX.TRMREQ, [7] MCTL[29]_RX.TRMREQ, [6] MCTL[29]_TX.RECREQ, [6] MCTL[29]_RX.RECREQ, [4] MCTL[29]_TX.ONESHOT, [4] MCTL[29]_RX.ONESHOT, [2] MCTL[29]_TX.TRMABT, [2] MCTL[29]_RX.MSGLOST, [1] MCTL[29]_TX.TRMACTIVE, [1] MCTL[29]_RX.INVALDATA, [0] MCTL[29]_TX.SENTDATA, [0] MCTL[29]_RX.NEWDATA
0x9083E CAN0
  [7] MCTL[30]_TX.TRMREQ, [7] MCTL[30]_RX.TRMREQ, [6] MCTL[30]_TX.RECREQ, [6] MCTL[30]_RX.RECREQ, [4] MCTL[30]_TX.ONESHOT, [4] MCTL[30]_RX.ONESHOT, [2] MCTL[30]_TX.TRMABT, [2] MCTL[30]_RX.MSGLOST, [1] MCTL[30]_TX.TRMACTIVE, [1] MCTL[30]_RX.INVALDATA, [0] MCTL[30]_TX.SENTDATA, [0] MCTL[30]_RX.NEWDATA
0x9083F CAN0
  [7] MCTL[31]_TX.TRMREQ, [7] MCTL[31]_RX.TRMREQ, [6] MCTL[31]_TX.RECREQ, [6] MCTL[31]_RX.RECREQ, [4] MCTL[31]_TX.ONESHOT, [4] MCTL[31]_RX.ONESHOT, [2] MCTL[31]_TX.TRMABT, [2] MCTL[31]_RX.MSGLOST, [1] MCTL[31]_TX.TRMACTIVE, [1] MCTL[31]_RX.INVALDATA, [0] MCTL[31]_TX.SENTDATA, [0] MCTL[31]_RX.NEWDATA
0x90840 CAN0 16-bit
  [13] CTLR.RBOC, [12:11] CTLR.BOM, [10] CTLR.SLPM, [9:8] CTLR.CANM, [7:6] CTLR.TSPS, [5] CTLR.TSRC, [4] CTLR.TPM, [3] CTLR.MLM, [2:1] CTLR.IDFM, [0] CTLR.MBM
0x90842 CAN0 16-bit
  [14] STR.RECST, [13] STR.TRMST, [12] STR.BOST, [11] STR.EPST, [10] STR.SLPST, [9] STR.HLTST, [8] STR.RSTST, [7] STR.EST, [6] STR.TABST, [5] STR.FMLST, [4] STR.NMLST, [3] STR.TFST, [2] STR.RFST, [1] STR.SDST, [0] STR.NDST
0x90844 CAN0 32-bit
  [31:28] BCR.TSEG1, [25:16] BCR.BRP, [13:12] BCR.SJW, [10:8] BCR.TSEG2, [0] BCR.CCLKS
0x90848 CAN0
  [7] RFCR.RFEST, [6] RFCR.RFWST, [5] RFCR.RFFST, [4] RFCR.RFMLF, [3:1] RFCR.RFUST, [0] RFCR.RFE
0x9084A CAN0
  [7] TFCR.TFEST, [6] TFCR.TFFST, [3:1] TFCR.TFUST, [0] TFCR.TFE
0x9084C CAN0
  [7] EIER.BLIE, [6] EIER.OLIE, [5] EIER.ORIE, [4] EIER.BORIE, [3] EIER.BOEIE, [2] EIER.EPIE, [1] EIER.EWIE, [0] EIER.BEIE
0x9084D CAN0
  [7] EIFR.BLIF, [6] EIFR.OLIF, [5] EIFR.ORIF, [4] EIFR.BORIF, [3] EIFR.BOEIF, [2] EIFR.EPIF, [1] EIFR.EWIF, [0] EIFR.BEIF
0x90850 CAN0
  [7] ECSR.EDPM, [6] ECSR.ADEF, [5] ECSR.BE0F, [4] ECSR.BE1F, [3] ECSR.CEF, [2] ECSR.AEF, [1] ECSR.FEF, [0] ECSR.SEF
0x90852 CAN0
  [7] MSSR.SEST, [4:0] MSSR.MBNST
0x90853 CAN0
  [1:0] MSMR.MBSM
0x90858 CAN0
  [2:1] TCR.TSTM, [0] TCR.TSTE
0x91200 CAN1 32-bit
  fields as CAN0
0x91210 CAN1 32-bit
  [31] MB[1]_ID.IDE, [30] MB[1]_ID.RTR, [28:18] MB[1]_ID.SID, [17:0] MB[1]_ID.EID
0x91220 CAN1 32-bit
  [31] MB[2]_ID.IDE, [30] MB[2]_ID.RTR, [28:18] MB[2]_ID.SID, [17:0] MB[2]_ID.EID
0x91230 CAN1 32-bit
  [31] MB[3]_ID.IDE, [30] MB[3]_ID.RTR, [28:18] MB[3]_ID.SID, [17:0] MB[3]_ID.EID
0x91240 CAN1 32-bit
  [31] MB[4]_ID.IDE, [30] MB[4]_ID.RTR, [28:18] MB[4]_ID.SID, [17:0] MB[4]_ID.EID
0x91250 CAN1 32-bit
  [31] MB[5]_ID.IDE, [30] MB[5]_ID.RTR, [28:18] MB[5]_ID.SID, [17:0] MB[5]_ID.EID
0x91260 CAN1 32-bit
  [31] MB[6]_ID.IDE, [30] MB[6]_ID.RTR, [28:18] MB[6]_ID.SID, [17:0] MB[6]_ID.EID
0x91270 CAN1 32-bit
  [31] MB[7]_ID.IDE, [30] MB[7]_ID.RTR, [28:18] MB[7]_ID.SID, [17:0] MB[7]_ID.EID
0x91280 CAN1 32-bit
  [31] MB[8]_ID.IDE, [30] MB[8]_ID.RTR, [28:18] MB[8]_ID.SID, [17:0] MB[8]_ID.EID
0x91290 CAN1 32-bit
  [31] MB[9]_ID.IDE, [30] MB[9]_ID.RTR, [28:18] MB[9]_ID.SID, [17:0] MB[9]_ID.EID
0x912A0 CAN1 32-bit
  [31] MB[10]_ID.IDE, [30] MB[10]_ID.RTR, [28:18] MB[10]_ID.SID, [17:0] MB[10]_ID.EID
0x912B0 CAN1 32-bit
  [31] MB[11]_ID.IDE, [30] MB[11]_ID.RTR, [28:18] MB[11]_ID.SID, [17:0] MB[11]_ID.EID
0x912C0 CAN1 32-bit
  [31] MB[12]_ID.IDE, [30] MB[12]_ID.RTR, [28:18] MB[12]_ID.SID, [17:0] MB[12]_ID.EID
0x912D0 CAN1 32-bit
  [31] MB[13]_ID.IDE, [30] MB[13]_ID.RTR, [28:18] MB[13]_ID.SID, [17:0] MB[13]_ID.EID
0x912E0 CAN1 32-bit
  [31] MB[14]_ID.IDE, [30] MB[14]_ID.RTR, [28:18] MB[14]_ID.SID, [17:0] MB[14]_ID.EID
0x912F0 CAN1 32-bit
  [31] MB[15]_ID.IDE, [30] MB[15]_ID.RTR, [28:18] MB[15]_ID.SID, [17:0] MB[15]_ID.EID
0x91300 CAN1 32-bit
  [31] MB[16]_ID.IDE, [30] MB[16]_ID.RTR, [28:18] MB[16]_ID.SID, [17:0] MB[16]_ID.EID
0x91310 CAN1 32-bit
  [31] MB[17]_ID.IDE, [30] MB[17]_ID.RTR, [28:18] MB[17]_ID.SID, [17:0] MB[17]_ID.EID
0x91320 CAN1 32-bit
  [31] MB[18]_ID.IDE, [30] MB[18]_ID.RTR, [28:18] MB[18]_ID.SID, [17:0] MB[18]_ID.EID
0x91330 CAN1 32-bit
  [31] MB[19]_ID.IDE, [30] MB[19]_ID.RTR, [28:18] MB[19]_ID.SID, [17:0] MB[19]_ID.EID
0x91340 CAN1 32-bit
  [31] MB[20]_ID.IDE, [30] MB[20]_ID.RTR, [28:18] MB[20]_ID.SID, [17:0] MB[20]_ID.EID
0x91350 CAN1 32-bit
  [31] MB[21]_ID.IDE, [30] MB[21]_ID.RTR, [28:18] MB[21]_ID.SID, [17:0] MB[21]_ID.EID
0x91360 CAN1 32-bit
  [31] MB[22]_ID.IDE, [30] MB[22]_ID.RTR, [28:18] MB[22]_ID.SID, [17:0] MB[22]_ID.EID
0x91370 CAN1 32-bit
  [31] MB[23]_ID.IDE, [30] MB[23]_ID.RTR, [28:18] MB[23]_ID.SID, [17:0] MB[23]_ID.EID
0x91380 CAN1 32-bit
  [31] MB[24]_ID.IDE, [30] MB[24]_ID.RTR, [28:18] MB[24]_ID.SID, [17:0] MB[24]_ID.EID
0x91390 CAN1 32-bit
  [31] MB[25]_ID.IDE, [30] MB[25]_ID.RTR, [28:18] MB[25]_ID.SID, [17:0] MB[25]_ID.EID
0x913A0 CAN1 32-bit
  [31] MB[26]_ID.IDE, [30] MB[26]_ID.RTR, [28:18] MB[26]_ID.SID, [17:0] MB[26]_ID.EID
0x913B0 CAN1 32-bit
  [31] MB[27]_ID.IDE, [30] MB[27]_ID.RTR, [28:18] MB[27]_ID.SID, [17:0] MB[27]_ID.EID
0x913C0 CAN1 32-bit
  [31] MB[28]_ID.IDE, [30] MB[28]_ID.RTR, [28:18] MB[28]_ID.SID, [17:0] MB[28]_ID.EID
0x913D0 CAN1 32-bit
  [31] MB[29]_ID.IDE, [30] MB[29]_ID.RTR, [28:18] MB[29]_ID.SID, [17:0] MB[29]_ID.EID
0x913E0 CAN1 32-bit
  [31] MB[30]_ID.IDE, [30] MB[30]_ID.RTR, [28:18] MB[30]_ID.SID, [17:0] MB[30]_ID.EID
0x913F0 CAN1 32-bit
  [31] MB[31]_ID.IDE, [30] MB[31]_ID.RTR, [28:18] MB[31]_ID.SID, [17:0] MB[31]_ID.EID
0x91400 CAN1 32-bit
  [28:18] MKR[0].SID, [17:0] MKR[0].EID
0x91404 CAN1 32-bit
  [28:18] MKR[1].SID, [17:0] MKR[1].EID
0x91408 CAN1 32-bit
  [28:18] MKR[2].SID, [17:0] MKR[2].EID
0x9140C CAN1 32-bit
  [28:18] MKR[3].SID, [17:0] MKR[3].EID
0x91410 CAN1 32-bit
  [28:18] MKR[4].SID, [17:0] MKR[4].EID
0x91414 CAN1 32-bit
  [28:18] MKR[5].SID, [17:0] MKR[5].EID
0x91418 CAN1 32-bit
  [28:18] MKR[6].SID, [17:0] MKR[6].EID
0x9141C CAN1 32-bit
  [28:18] MKR[7].SID, [17:0] MKR[7].EID
0x91420 CAN1 32-bit
  [31] FIDCR0.IDE, [30] FIDCR0.RTR, [28:18] FIDCR0.SID, [17:0] FIDCR0.EID
0x91424 CAN1 32-bit
  [31] FIDCR1.IDE, [30] FIDCR1.RTR, [28:18] FIDCR1.SID, [17:0] FIDCR1.EID
0x91428 CAN1 32-bit
  [n] MKIVLR.MB{n} (n=0..31)
0x9142C CAN1 32-bit
  [n] MIER.MB{n} (n=0..31)
0x91820 CAN1
  [7] MCTL[0]_TX.TRMREQ, [7] MCTL[0]_RX.TRMREQ, [6] MCTL[0]_TX.RECREQ, [6] MCTL[0]_RX.RECREQ, [4] MCTL[0]_TX.ONESHOT, [4] MCTL[0]_RX.ONESHOT, [2] MCTL[0]_TX.TRMABT, [2] MCTL[0]_RX.MSGLOST, [1] MCTL[0]_TX.TRMACTIVE, [1] MCTL[0]_RX.INVALDATA, [0] MCTL[0]_TX.SENTDATA, [0] MCTL[0]_RX.NEWDATA
0x91821 CAN1
  [7] MCTL[1]_TX.TRMREQ, [7] MCTL[1]_RX.TRMREQ, [6] MCTL[1]_TX.RECREQ, [6] MCTL[1]_RX.RECREQ, [4] MCTL[1]_TX.ONESHOT, [4] MCTL[1]_RX.ONESHOT, [2] MCTL[1]_TX.TRMABT, [2] MCTL[1]_RX.MSGLOST, [1] MCTL[1]_TX.TRMACTIVE, [1] MCTL[1]_RX.INVALDATA, [0] MCTL[1]_TX.SENTDATA, [0] MCTL[1]_RX.NEWDATA
0x91822 CAN1
  [7] MCTL[2]_TX.TRMREQ, [7] MCTL[2]_RX.TRMREQ, [6] MCTL[2]_TX.RECREQ, [6] MCTL[2]_RX.RECREQ, [4] MCTL[2]_TX.ONESHOT, [4] MCTL[2]_RX.ONESHOT, [2] MCTL[2]_TX.TRMABT, [2] MCTL[2]_RX.MSGLOST, [1] MCTL[2]_TX.TRMACTIVE, [1] MCTL[2]_RX.INVALDATA, [0] MCTL[2]_TX.SENTDATA, [0] MCTL[2]_RX.NEWDATA
0x91823 CAN1
  [7] MCTL[3]_TX.TRMREQ, [7] MCTL[3]_RX.TRMREQ, [6] MCTL[3]_TX.RECREQ, [6] MCTL[3]_RX.RECREQ, [4] MCTL[3]_TX.ONESHOT, [4] MCTL[3]_RX.ONESHOT, [2] MCTL[3]_TX.TRMABT, [2] MCTL[3]_RX.MSGLOST, [1] MCTL[3]_TX.TRMACTIVE, [1] MCTL[3]_RX.INVALDATA, [0] MCTL[3]_TX.SENTDATA, [0] MCTL[3]_RX.NEWDATA
0x91824 CAN1
  [7] MCTL[4]_TX.TRMREQ, [7] MCTL[4]_RX.TRMREQ, [6] MCTL[4]_TX.RECREQ, [6] MCTL[4]_RX.RECREQ, [4] MCTL[4]_TX.ONESHOT, [4] MCTL[4]_RX.ONESHOT, [2] MCTL[4]_TX.TRMABT, [2] MCTL[4]_RX.MSGLOST, [1] MCTL[4]_TX.TRMACTIVE, [1] MCTL[4]_RX.INVALDATA, [0] MCTL[4]_TX.SENTDATA, [0] MCTL[4]_RX.NEWDATA
0x91825 CAN1
  [7] MCTL[5]_TX.TRMREQ, [7] MCTL[5]_RX.TRMREQ, [6] MCTL[5]_TX.RECREQ, [6] MCTL[5]_RX.RECREQ, [4] MCTL[5]_TX.ONESHOT, [4] MCTL[5]_RX.ONESHOT, [2] MCTL[5]_TX.TRMABT, [2] MCTL[5]_RX.MSGLOST, [1] MCTL[5]_TX.TRMACTIVE, [1] MCTL[5]_RX.INVALDATA, [0] MCTL[5]_TX.SENTDATA, [0] MCTL[5]_RX.NEWDATA
0x91826 CAN1
  [7] MCTL[6]_TX.TRMREQ, [7] MCTL[6]_RX.TRMREQ, [6] MCTL[6]_TX.RECREQ, [6] MCTL[6]_RX.RECREQ, [4] MCTL[6]_TX.ONESHOT, [4] MCTL[6]_RX.ONESHOT, [2] MCTL[6]_TX.TRMABT, [2] MCTL[6]_RX.MSGLOST, [1] MCTL[6]_TX.TRMACTIVE, [1] MCTL[6]_RX.INVALDATA, [0] MCTL[6]_TX.SENTDATA, [0] MCTL[6]_RX.NEWDATA
0x91827 CAN1
  [7] MCTL[7]_TX.TRMREQ, [7] MCTL[7]_RX.TRMREQ, [6] MCTL[7]_TX.RECREQ, [6] MCTL[7]_RX.RECREQ, [4] MCTL[7]_TX.ONESHOT, [4] MCTL[7]_RX.ONESHOT, [2] MCTL[7]_TX.TRMABT, [2] MCTL[7]_RX.MSGLOST, [1] MCTL[7]_TX.TRMACTIVE, [1] MCTL[7]_RX.INVALDATA, [0] MCTL[7]_TX.SENTDATA, [0] MCTL[7]_RX.NEWDATA
0x91828 CAN1
  [7] MCTL[8]_TX.TRMREQ, [7] MCTL[8]_RX.TRMREQ, [6] MCTL[8]_TX.RECREQ, [6] MCTL[8]_RX.RECREQ, [4] MCTL[8]_TX.ONESHOT, [4] MCTL[8]_RX.ONESHOT, [2] MCTL[8]_TX.TRMABT, [2] MCTL[8]_RX.MSGLOST, [1] MCTL[8]_TX.TRMACTIVE, [1] MCTL[8]_RX.INVALDATA, [0] MCTL[8]_TX.SENTDATA, [0] MCTL[8]_RX.NEWDATA
0x91829 CAN1
  [7] MCTL[9]_TX.TRMREQ, [7] MCTL[9]_RX.TRMREQ, [6] MCTL[9]_TX.RECREQ, [6] MCTL[9]_RX.RECREQ, [4] MCTL[9]_TX.ONESHOT, [4] MCTL[9]_RX.ONESHOT, [2] MCTL[9]_TX.TRMABT, [2] MCTL[9]_RX.MSGLOST, [1] MCTL[9]_TX.TRMACTIVE, [1] MCTL[9]_RX.INVALDATA, [0] MCTL[9]_TX.SENTDATA, [0] MCTL[9]_RX.NEWDATA
0x9182A CAN1
  [7] MCTL[10]_TX.TRMREQ, [7] MCTL[10]_RX.TRMREQ, [6] MCTL[10]_TX.RECREQ, [6] MCTL[10]_RX.RECREQ, [4] MCTL[10]_TX.ONESHOT, [4] MCTL[10]_RX.ONESHOT, [2] MCTL[10]_TX.TRMABT, [2] MCTL[10]_RX.MSGLOST, [1] MCTL[10]_TX.TRMACTIVE, [1] MCTL[10]_RX.INVALDATA, [0] MCTL[10]_TX.SENTDATA, [0] MCTL[10]_RX.NEWDATA
0x9182B CAN1
  [7] MCTL[11]_TX.TRMREQ, [7] MCTL[11]_RX.TRMREQ, [6] MCTL[11]_TX.RECREQ, [6] MCTL[11]_RX.RECREQ, [4] MCTL[11]_TX.ONESHOT, [4] MCTL[11]_RX.ONESHOT, [2] MCTL[11]_TX.TRMABT, [2] MCTL[11]_RX.MSGLOST, [1] MCTL[11]_TX.TRMACTIVE, [1] MCTL[11]_RX.INVALDATA, [0] MCTL[11]_TX.SENTDATA, [0] MCTL[11]_RX.NEWDATA
0x9182C CAN1
  [7] MCTL[12]_TX.TRMREQ, [7] MCTL[12]_RX.TRMREQ, [6] MCTL[12]_TX.RECREQ, [6] MCTL[12]_RX.RECREQ, [4] MCTL[12]_TX.ONESHOT, [4] MCTL[12]_RX.ONESHOT, [2] MCTL[12]_TX.TRMABT, [2] MCTL[12]_RX.MSGLOST, [1] MCTL[12]_TX.TRMACTIVE, [1] MCTL[12]_RX.INVALDATA, [0] MCTL[12]_TX.SENTDATA, [0] MCTL[12]_RX.NEWDATA
0x9182D CAN1
  [7] MCTL[13]_TX.TRMREQ, [7] MCTL[13]_RX.TRMREQ, [6] MCTL[13]_TX.RECREQ, [6] MCTL[13]_RX.RECREQ, [4] MCTL[13]_TX.ONESHOT, [4] MCTL[13]_RX.ONESHOT, [2] MCTL[13]_TX.TRMABT, [2] MCTL[13]_RX.MSGLOST, [1] MCTL[13]_TX.TRMACTIVE, [1] MCTL[13]_RX.INVALDATA, [0] MCTL[13]_TX.SENTDATA, [0] MCTL[13]_RX.NEWDATA
0x9182E CAN1
  [7] MCTL[14]_TX.TRMREQ, [7] MCTL[14]_RX.TRMREQ, [6] MCTL[14]_TX.RECREQ, [6] MCTL[14]_RX.RECREQ, [4] MCTL[14]_TX.ONESHOT, [4] MCTL[14]_RX.ONESHOT, [2] MCTL[14]_TX.TRMABT, [2] MCTL[14]_RX.MSGLOST, [1] MCTL[14]_TX.TRMACTIVE, [1] MCTL[14]_RX.INVALDATA, [0] MCTL[14]_TX.SENTDATA, [0] MCTL[14]_RX.NEWDATA
0x9182F CAN1
  [7] MCTL[15]_TX.TRMREQ, [7] MCTL[15]_RX.TRMREQ, [6] MCTL[15]_TX.RECREQ, [6] MCTL[15]_RX.RECREQ, [4] MCTL[15]_TX.ONESHOT, [4] MCTL[15]_RX.ONESHOT, [2] MCTL[15]_TX.TRMABT, [2] MCTL[15]_RX.MSGLOST, [1] MCTL[15]_TX.TRMACTIVE, [1] MCTL[15]_RX.INVALDATA, [0] MCTL[15]_TX.SENTDATA, [0] MCTL[15]_RX.NEWDATA
0x91830 CAN1
  [7] MCTL[16]_TX.TRMREQ, [7] MCTL[16]_RX.TRMREQ, [6] MCTL[16]_TX.RECREQ, [6] MCTL[16]_RX.RECREQ, [4] MCTL[16]_TX.ONESHOT, [4] MCTL[16]_RX.ONESHOT, [2] MCTL[16]_TX.TRMABT, [2] MCTL[16]_RX.MSGLOST, [1] MCTL[16]_TX.TRMACTIVE, [1] MCTL[16]_RX.INVALDATA, [0] MCTL[16]_TX.SENTDATA, [0] MCTL[16]_RX.NEWDATA
0x91831 CAN1
  [7] MCTL[17]_TX.TRMREQ, [7] MCTL[17]_RX.TRMREQ, [6] MCTL[17]_TX.RECREQ, [6] MCTL[17]_RX.RECREQ, [4] MCTL[17]_TX.ONESHOT, [4] MCTL[17]_RX.ONESHOT, [2] MCTL[17]_TX.TRMABT, [2] MCTL[17]_RX.MSGLOST, [1] MCTL[17]_TX.TRMACTIVE, [1] MCTL[17]_RX.INVALDATA, [0] MCTL[17]_TX.SENTDATA, [0] MCTL[17]_RX.NEWDATA
0x91832 CAN1
  [7] MCTL[18]_TX.TRMREQ, [7] MCTL[18]_RX.TRMREQ, [6] MCTL[18]_TX.RECREQ, [6] MCTL[18]_RX.RECREQ, [4] MCTL[18]_TX.ONESHOT, [4] MCTL[18]_RX.ONESHOT, [2] MCTL[18]_TX.TRMABT, [2] MCTL[18]_RX.MSGLOST, [1] MCTL[18]_TX.TRMACTIVE, [1] MCTL[18]_RX.INVALDATA, [0] MCTL[18]_TX.SENTDATA, [0] MCTL[18]_RX.NEWDATA
0x91833 CAN1
  [7] MCTL[19]_TX.TRMREQ, [7] MCTL[19]_RX.TRMREQ, [6] MCTL[19]_TX.RECREQ, [6] MCTL[19]_RX.RECREQ, [4] MCTL[19]_TX.ONESHOT, [4] MCTL[19]_RX.ONESHOT, [2] MCTL[19]_TX.TRMABT, [2] MCTL[19]_RX.MSGLOST, [1] MCTL[19]_TX.TRMACTIVE, [1] MCTL[19]_RX.INVALDATA, [0] MCTL[19]_TX.SENTDATA, [0] MCTL[19]_RX.NEWDATA
0x91834 CAN1
  [7] MCTL[20]_TX.TRMREQ, [7] MCTL[20]_RX.TRMREQ, [6] MCTL[20]_TX.RECREQ, [6] MCTL[20]_RX.RECREQ, [4] MCTL[20]_TX.ONESHOT, [4] MCTL[20]_RX.ONESHOT, [2] MCTL[20]_TX.TRMABT, [2] MCTL[20]_RX.MSGLOST, [1] MCTL[20]_TX.TRMACTIVE, [1] MCTL[20]_RX.INVALDATA, [0] MCTL[20]_TX.SENTDATA, [0] MCTL[20]_RX.NEWDATA
# iorx65n register map
Registers are 8-bit, access not given, no defined reset value unless marked. A register's access mark holds for its fields unless they carry their own. Addresses are absolute; registers are grouped by the start of their names; [hi:lo] are bit positions; {n}, {i} and the like mark numbered series; 'fields as' and 'values as' point back to an identical list.

## SFR (part 3 of 7)
0x87348 ICU
  [3:0] IPR[72](ICU,IRQ8).IPR
0x87349 ICU
  [3:0] IPR[73](ICU,IRQ9).IPR
0x8734A ICU
  [3:0] IPR[74](ICU,IRQ10).IPR
0x8734B ICU
  [3:0] IPR[75](ICU,IRQ11).IPR
0x8734C ICU
  [3:0] IPR[76](ICU,IRQ12).IPR
0x8734D ICU
  [3:0] IPR[77](ICU,IRQ13).IPR
0x8734E ICU
  [3:0] IPR[78](ICU,IRQ14).IPR
0x8734F ICU
  [3:0] IPR[79](ICU,IRQ15).IPR
0x87350 ICU
  [3:0] IPR[80](SCI3,RXI3).IPR
0x87351 ICU
  [3:0] IPR[81](SCI3,TXI3).IPR
0x87352 ICU
  [3:0] IPR[82](SCI4,RXI4).IPR
0x87353 ICU
  [3:0] IPR[83](SCI4,TXI4).IPR
0x87354 ICU
  [3:0] IPR[84](SCI5,RXI5).IPR
0x87355 ICU
  [3:0] IPR[85](SCI5,TXI5).IPR
0x87356 ICU
  [3:0] IPR[86](SCI6,RXI6).IPR
0x87357 ICU
  [3:0] IPR[87](SCI6,TXI6).IPR
0x87358 ICU
  [3:0] IPR[88](LVD1,LVD1).IPR
0x87359 ICU
  [3:0] IPR[89](LVD2,LVD2).IPR
0x8735A ICU
  [3:0] IPR[90](USB0,USBR0).IPR
0x8735B ICU
  [3:0] IPR[91].IPR
0x8735C ICU
  [3:0] IPR[92](RTC,ALM).IPR
0x8735D ICU
  [3:0] IPR[93](RTC,PRD).IPR
0x8735E ICU
  [3:0] IPR[94].IPR
0x8735F ICU
  [3:0] IPR[95](IWDT,IWUNI).IPR
0x87360 ICU
  [3:0] IPR[96](WDT,WUNI).IPR
0x87361 ICU
  [3:0] IPR[97](PDC,PCDFI).IPR
0x87362 ICU
  [3:0] IPR[98](SCI7,RXI7).IPR
0x87363 ICU
  [3:0] IPR[99](SCI7,TXI7).IPR
0x87364 ICU
  [3:0] IPR[100](SCI8,RXI8).IPR
0x87365 ICU
  [3:0] IPR[101](SCI8,TXI8).IPR
0x87366 ICU
  [3:0] IPR[102](SCI9,RXI9).IPR
0x87367 ICU
  [3:0] IPR[103](SCI9,TXI9).IPR
0x87368 ICU
  [3:0] IPR[104](SCI10,RXI10).IPR
0x87369 ICU
  [3:0] IPR[105](SCI10,TXI10).IPR
0x8736A ICU
  [3:0] IPR[106](ICU,GROUPBE0).IPR
0x8736B ICU
  [3:0] IPR[107](ICU,GROUPBL2).IPR
0x8736C ICU
  [3:0] IPR[108](RSPI2,SPRI2).IPR
0x8736D ICU
  [3:0] IPR[109](RSPI2,SPTI2).IPR
0x8736E ICU
  [3:0] IPR[110](ICU,GROUPBL0).IPR
0x8736F ICU
  [3:0] IPR[111](ICU,GROUPBL1).IPR
0x87370 ICU
  [3:0] IPR[112](ICU,GROUPAL0).IPR
0x87371 ICU
  [3:0] IPR[113](ICU,GROUPAL1).IPR
0x87372 ICU
  [3:0] IPR[114](SCI11,RXI11).IPR
0x87373 ICU
  [3:0] IPR[115](SCI11,TXI11).IPR
0x87374 ICU
  [3:0] IPR[116](SCI12,RXI12).IPR
0x87375 ICU
  [3:0] IPR[117](SCI12,TXI12).IPR
0x87376 ICU
  [3:0] IPR[118].IPR
0x87377 ICU
  [3:0] IPR[119].IPR
0x87378 ICU
  [3:0] IPR[120](DMAC,DMAC0I).IPR
0x87379 ICU
  [3:0] IPR[121](DMAC,DMAC1I).IPR
0x8737A ICU
  [3:0] IPR[122](DMAC,DMAC2I).IPR
0x8737B ICU
  [3:0] IPR[123](DMAC,DMAC3I).IPR
0x8737C ICU
  [3:0] IPR[124](DMAC,DMAC74I).IPR
0x8737D ICU
  [3:0] IPR[125](OST,OSTDI).IPR
0x8737E ICU
  [3:0] IPR[126](EXDMAC,EXDMAC0I).IPR
0x8737F ICU
  [3:0] IPR[127](EXDMAC,EXDMAC1I).IPR
0x87380 ICU
  [3:0] IPR[128](PERIB,INTB128).IPR
0x87381 ICU
  [3:0] IPR[129](PERIB,INTB129).IPR
0x87382 ICU
  [3:0] IPR[130](PERIB,INTB130).IPR
0x87383 ICU
  [3:0] IPR[131](PERIB,INTB131).IPR
0x87384 ICU
  [3:0] IPR[132](PERIB,INTB132).IPR
0x87385 ICU
  [3:0] IPR[133](PERIB,INTB133).IPR
0x87386 ICU
  [3:0] IPR[134](PERIB,INTB134).IPR
0x87387 ICU
  [3:0] IPR[135](PERIB,INTB135).IPR
0x87388 ICU
  [3:0] IPR[136](PERIB,INTB136).IPR
0x87389 ICU
  [3:0] IPR[137](PERIB,INTB137).IPR
0x8738A ICU
  [3:0] IPR[138](PERIB,INTB138).IPR
0x8738B ICU
  [3:0] IPR[139](PERIB,INTB139).IPR
0x8738C ICU
  [3:0] IPR[140](PERIB,INTB140).IPR
0x8738D ICU
  [3:0] IPR[141](PERIB,INTB141).IPR
0x8738E ICU
  [3:0] IPR[142](PERIB,INTB142).IPR
0x8738F ICU
  [3:0] IPR[143](PERIB,INTB143).IPR
0x87390 ICU
  [3:0] IPR[144](PERIB,INTB144).IPR
0x87391 ICU
  [3:0] IPR[145](PERIB,INTB145).IPR
0x87392 ICU
  [3:0] IPR[146](PERIB,INTB146).IPR
0x87393 ICU
  [3:0] IPR[147](PERIB,INTB147).IPR
0x87394 ICU
  [3:0] IPR[148](PERIB,INTB148).IPR
0x87395 ICU
  [3:0] IPR[149](PERIB,INTB149).IPR
0x87396 ICU
  [3:0] IPR[150](PERIB,INTB150).IPR
0x87397 ICU
  [3:0] IPR[151](PERIB,INTB151).IPR
0x87398 ICU
  [3:0] IPR[152](PERIB,INTB152).IPR
0x87399 ICU
  [3:0] IPR[153](PERIB,INTB153).IPR
0x8739A ICU
  [3:0] IPR[154](PERIB,INTB154).IPR
0x8739B ICU
  [3:0] IPR[155](PERIB,INTB155).IPR
0x8739C ICU
  [3:0] IPR[156](PERIB,INTB156).IPR
0x8739D ICU
  [3:0] IPR[157](PERIB,INTB157).IPR
0x8739E ICU
  [3:0] IPR[158](PERIB,INTB158).IPR
0x8739F ICU
  [3:0] IPR[159](PERIB,INTB159).IPR
0x873A0 ICU
  [3:0] IPR[160](PERIB,INTB160).IPR
0x873A1 ICU
  [3:0] IPR[161](PERIB,INTB161).IPR
0x873A2 ICU
  [3:0] IPR[162](PERIB,INTB162).IPR
0x873A3 ICU
  [3:0] IPR[163](PERIB,INTB163).IPR
0x873A4 ICU
  [3:0] IPR[164](PERIB,INTB164).IPR
0x873A5 ICU
  [3:0] IPR[165](PERIB,INTB165).IPR
0x873A6 ICU
  [3:0] IPR[166](PERIB,INTB166).IPR
0x873A7 ICU
  [3:0] IPR[167](PERIB,INTB167).IPR
0x873A8 ICU
  [3:0] IPR[168](PERIB,INTB168).IPR
0x873A9 ICU
  [3:0] IPR[169](PERIB,INTB169).IPR
0x873AA ICU
  [3:0] IPR[170](PERIB,INTB170).IPR
0x873AB ICU
  [3:0] IPR[171](PERIB,INTB171).IPR
0x873AC ICU
  [3:0] IPR[172](PERIB,INTB172).IPR
0x873AD ICU
  [3:0] IPR[173](PERIB,INTB173).IPR
0x873AE ICU
  [3:0] IPR[174](PERIB,INTB174).IPR
0x873AF ICU
  [3:0] IPR[175](PERIB,INTB175).IPR
0x873B0 ICU
  [3:0] IPR[176](PERIB,INTB176).IPR
0x873B1 ICU
  [3:0] IPR[177](PERIB,INTB177).IPR
0x873B2 ICU
  [3:0] IPR[178](PERIB,INTB178).IPR
0x873B3 ICU
  [3:0] IPR[179](PERIB,INTB179).IPR
0x873B4 ICU
  [3:0] IPR[180](PERIB,INTB180).IPR
0x873B5 ICU
  [3:0] IPR[181](PERIB,INTB181).IPR
0x873B6 ICU
  [3:0] IPR[182](PERIB,INTB182).IPR
0x873B7 ICU
  [3:0] IPR[183](PERIB,INTB183).IPR
0x873B8 ICU
  [3:0] IPR[184](PERIB,INTB184).IPR
0x873B9 ICU
  [3:0] IPR[185](PERIB,INTB185).IPR
0x873BA ICU
  [3:0] IPR[186](PERIB,INTB186).IPR
0x873BB ICU
  [3:0] IPR[187](PERIB,INTB187).IPR
0x873BC ICU
  [3:0] IPR[188](PERIB,INTB188).IPR
0x873BD ICU
  [3:0] IPR[189](PERIB,INTB189).IPR
0x873BE ICU
  [3:0] IPR[190](PERIB,INTB190).IPR
0x873BF ICU
  [3:0] IPR[191](PERIB,INTB191).IPR
0x873C0 ICU
  [3:0] IPR[192](PERIB,INTB192).IPR
0x873C1 ICU
  [3:0] IPR[193](PERIB,INTB193).IPR
0x873C2 ICU
  [3:0] IPR[194](PERIB,INTB194).IPR
0x873C3 ICU
  [3:0] IPR[195](PERIB,INTB195).IPR
0x873C4 ICU
  [3:0] IPR[196](PERIB,INTB196).IPR
0x873C5 ICU
  [3:0] IPR[197](PERIB,INTB197).IPR
0x873C6 ICU
  [3:0] IPR[198](PERIB,INTB198).IPR
0x873C7 ICU
  [3:0] IPR[199](PERIB,INTB199).IPR
0x873C8 ICU
  [3:0] IPR[200](PERIB,INTB200).IPR
0x873C9 ICU
  [3:0] IPR[201](PERIB,INTB201).IPR
0x873CA ICU
  [3:0] IPR[202](PERIB,INTB202).IPR
0x873CB ICU
  [3:0] IPR[203](PERIB,INTB203).IPR
0x873CC ICU
  [3:0] IPR[204](PERIB,INTB204).IPR
0x873CD ICU
  [3:0] IPR[205](PERIB,INTB205).IPR
0x873CE ICU
  [3:0] IPR[206](PERIB,INTB206).IPR
0x873CF ICU
  [3:0] IPR[207](PERIB,INTB207).IPR
0x873D0 ICU
  [3:0] IPR[208](PERIA,INTA208).IPR
0x873D1 ICU
  [3:0] IPR[209](PERIA,INTA209).IPR
0x873D2 ICU
  [3:0] IPR[210](PERIA,INTA210).IPR
0x873D3 ICU
  [3:0] IPR[211](PERIA,INTA211).IPR
0x873D4 ICU
  [3:0] IPR[212](PERIA,INTA212).IPR
0x873D5 ICU
  [3:0] IPR[213](PERIA,INTA213).IPR
0x873D6 ICU
  [3:0] IPR[214](PERIA,INTA214).IPR
0x873D7 ICU
  [3:0] IPR[215](PERIA,INTA215).IPR
0x873D8 ICU
  [3:0] IPR[216](PERIA,INTA216).IPR
0x873D9 ICU
  [3:0] IPR[217](PERIA,INTA217).IPR
0x873DA ICU
  [3:0] IPR[218](PERIA,INTA218).IPR
0x873DB ICU
  [3:0] IPR[219](PERIA,INTA219).IPR
0x873DC ICU
  [3:0] IPR[220](PERIA,INTA220).IPR
0x873DD ICU
  [3:0] IPR[221](PERIA,INTA221).IPR
0x873DE ICU
  [3:0] IPR[222](PERIA,INTA222).IPR
0x873DF ICU
  [3:0] IPR[223](PERIA,INTA223).IPR
0x873E0 ICU
  [3:0] IPR[224](PERIA,INTA224).IPR
0x873E1 ICU
  [3:0] IPR[225](PERIA,INTA225).IPR
0x873E2 ICU
  [3:0] IPR[226](PERIA,INTA226).IPR
0x873E3 ICU
  [3:0] IPR[227](PERIA,INTA227).IPR
0x873E4 ICU
  [3:0] IPR[228](PERIA,INTA228).IPR
0x873E5 ICU
  [3:0] IPR[229](PERIA,INTA229).IPR
0x873E6 ICU
  [3:0] IPR[230](PERIA,INTA230).IPR
0x873E7 ICU
  [3:0] IPR[231](PERIA,INTA231).IPR
0x873E8 ICU
  [3:0] IPR[232](PERIA,INTA232).IPR
0x873E9 ICU
  [3:0] IPR[233](PERIA,INTA233).IPR
0x873EA ICU
  [3:0] IPR[234](PERIA,INTA234).IPR
0x873EB ICU
  [3:0] IPR[235](PERIA,INTA235).IPR
0x873EC ICU
  [3:0] IPR[236](PERIA,INTA236).IPR
0x873ED ICU
  [3:0] IPR[237](PERIA,INTA237).IPR
0x873EE ICU
  [3:0] IPR[238](PERIA,INTA238).IPR
0x873EF ICU
  [3:0] IPR[239](PERIA,INTA239).IPR
0x873F0 ICU
  [3:0] IPR[240](PERIA,INTA240).IPR
0x873F1 ICU
  [3:0] IPR[241](PERIA,INTA241).IPR
0x873F2 ICU
  [3:0] IPR[242](PERIA,INTA242).IPR
0x873F3 ICU
  [3:0] IPR[243](PERIA,INTA243).IPR
0x873F4 ICU
  [3:0] IPR[244](PERIA,INTA244).IPR
0x873F5 ICU
  [3:0] IPR[245](PERIA,INTA245).IPR
0x873F6 ICU
  [3:0] IPR[246](PERIA,INTA246).IPR
0x873F7 ICU
  [3:0] IPR[247](PERIA,INTA247).IPR
0x873F8 ICU
  [3:0] IPR[248](PERIA,INTA248).IPR
0x873F9 ICU
  [3:0] IPR[249](PERIA,INTA249).IPR
0x873FA ICU
  [3:0] IPR[250](PERIA,INTA250).IPR
0x873FB ICU
  [3:0] IPR[251](PERIA,INTA251).IPR
0x873FC ICU
  [3:0] IPR[252](PERIA,INTA252).IPR
0x873FD ICU
  [3:0] IPR[253](PERIA,INTA253).IPR
0x873FE ICU
  [3:0] IPR[254](PERIA,INTA254).IPR
0x873FF ICU
  [3:0] IPR[255](PERIA,INTA255).IPR
0x87500 ICU
  [3:2] IRQCR[0].IRQMD
0x87501 ICU
  [3:2] IRQCR[1].IRQMD
0x87502 ICU
  [3:2] IRQCR[2].IRQMD
0x87503 ICU
  [3:2] IRQCR[3].IRQMD
0x87504 ICU
  [3:2] IRQCR[4].IRQMD
0x87505 ICU
  [3:2] IRQCR[5].IRQMD
0x87506 ICU
  [3:2] IRQCR[6].IRQMD
0x87507 ICU
  [3:2] IRQCR[7].IRQMD
0x87508 ICU
  [3:2] IRQCR[8].IRQMD
0x87509 ICU
  [3:2] IRQCR[9].IRQMD
0x8750A ICU
  [3:2] IRQCR[10].IRQMD
0x8750B ICU
  [3:2] IRQCR[11].IRQMD
0x8750C ICU
  [3:2] IRQCR[12].IRQMD
0x8750D ICU
  [3:2] IRQCR[13].IRQMD
0x8750E ICU
  [3:2] IRQCR[14].IRQMD
0x8750F ICU
  [3:2] IRQCR[15].IRQMD
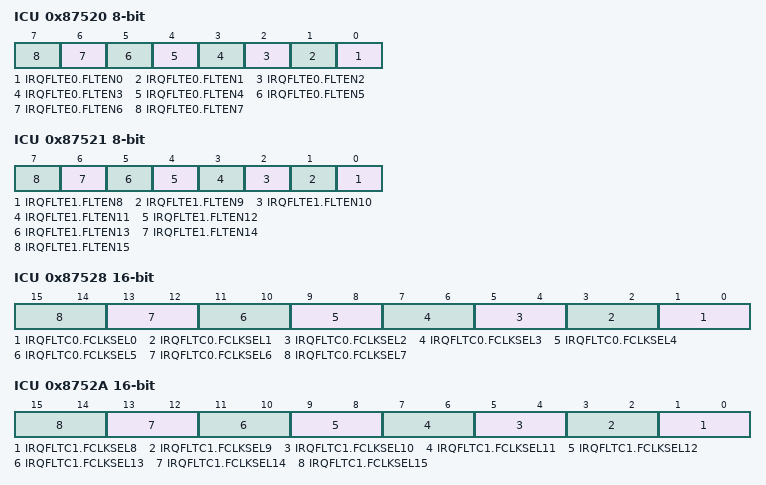
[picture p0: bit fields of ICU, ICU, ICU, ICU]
0x87520 ICU
  [n] IRQFLTE0.FLTEN{n} (n=0..7)
0x87521 ICU
  [n-8] IRQFLTE1.FLTEN{n} (n=8..15)
0x87528 ICU 16-bit
  [2n+1:2n] IRQFLTC0.FCLKSEL{n} (n=0..7)
0x8752A ICU 16-bit
  [2n-15:2n-16] IRQFLTC1.FCLKSEL{n} (n=8..15)
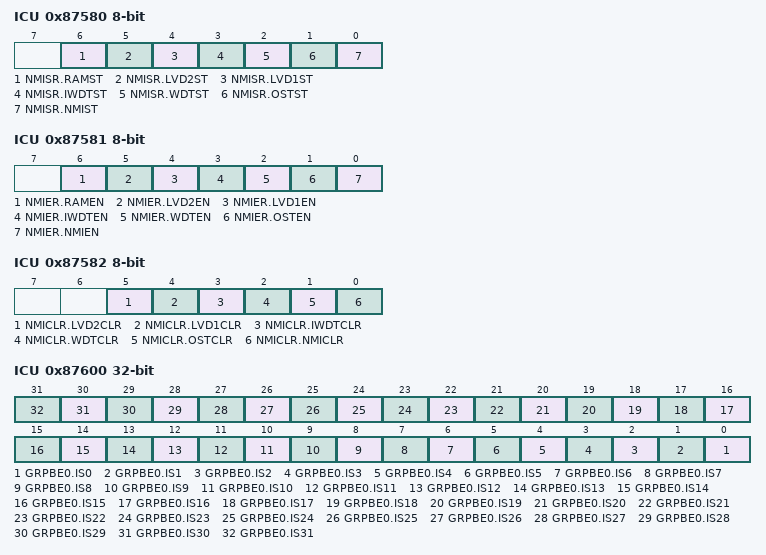
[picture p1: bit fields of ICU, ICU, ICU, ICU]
0x87580 ICU
  [6] NMISR.RAMST, [5] NMISR.LVD2ST, [4] NMISR.LVD1ST, [3] NMISR.IWDTST, [2] NMISR.WDTST, [1] NMISR.OSTST, [0] NMISR.NMIST
0x87581 ICU
  [6] NMIER.RAMEN, [5] NMIER.LVD2EN, [4] NMIER.LVD1EN, [3] NMIER.IWDTEN, [2] NMIER.WDTEN, [1] NMIER.OSTEN, [0] NMIER.NMIEN
0x87582 ICU
  [5] NMICLR.LVD2CLR, [4] NMICLR.LVD1CLR, [3] NMICLR.IWDTCLR, [2] NMICLR.WDTCLR, [1] NMICLR.OSTCLR, [0] NMICLR.NMICLR
0x87583 ICU
  [3] NMICR.NMIMD
0x87590 ICU
  [0] NMIFLTE.NFLTEN
0x87594 ICU
  [1:0] NMIFLTC.NFCLKSEL
0x87600 ICU 32-bit
  [n] GRPBE0.IS{n} (n=0..31)
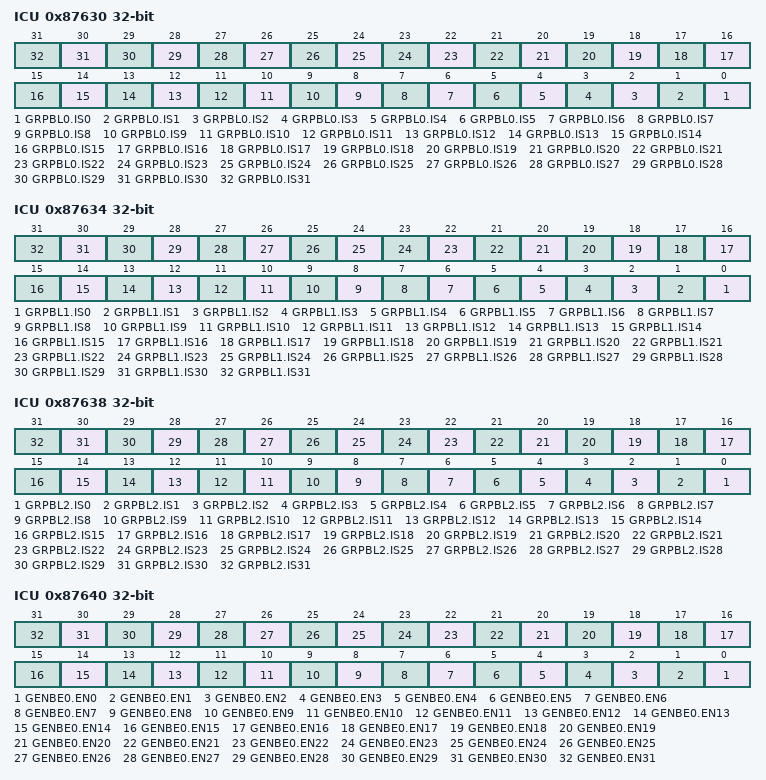
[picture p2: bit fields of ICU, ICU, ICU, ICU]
0x87630 ICU 32-bit
  [n] GRPBL0.IS{n} (n=0..31)
0x87634 ICU 32-bit
  [n] GRPBL1.IS{n} (n=0..31)
0x87638 ICU 32-bit
  [n] GRPBL2.IS{n} (n=0..31)
0x87640 ICU 32-bit
  [n] GENBE0.EN{n} (n=0..31)
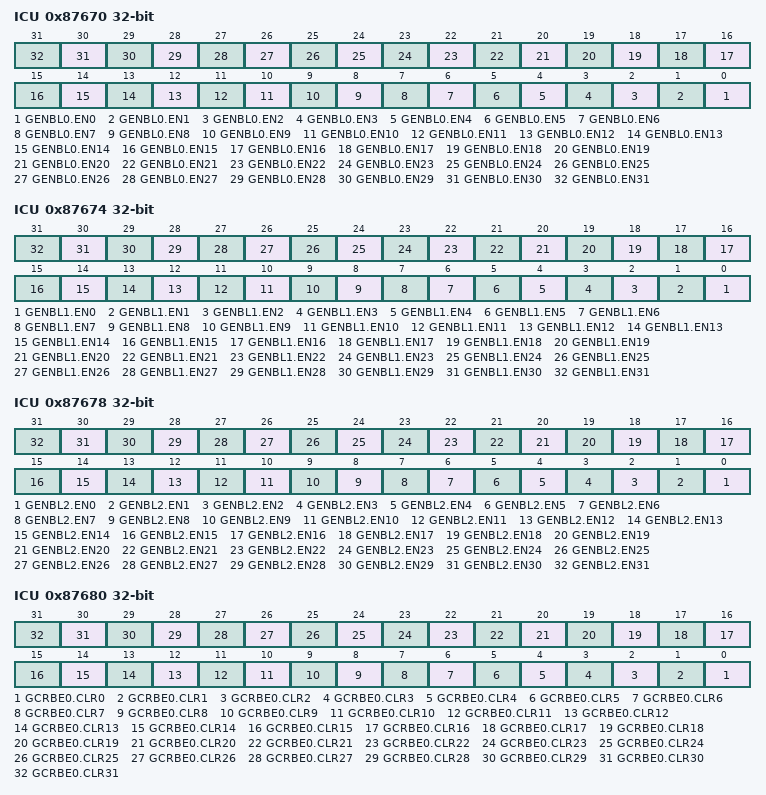
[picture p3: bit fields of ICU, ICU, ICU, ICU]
0x87670 ICU 32-bit
  [n] GENBL0.EN{n} (n=0..31)
0x87674 ICU 32-bit
  [n] GENBL1.EN{n} (n=0..31)
0x87678 ICU 32-bit
  [n] GENBL2.EN{n} (n=0..31)
0x87680 ICU 32-bit
  [n] GCRBE0.CLR{n} (n=0..31)
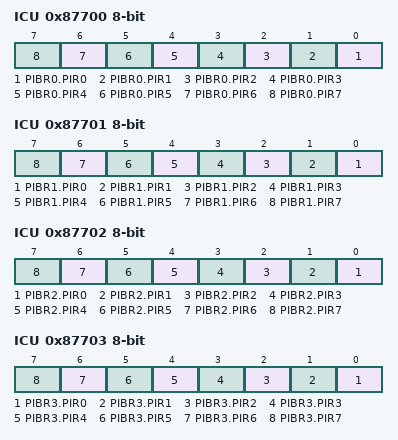
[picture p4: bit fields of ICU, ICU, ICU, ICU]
0x87700 ICU
  [n] PIBR0.PIR{n} (n=0..7)
0x87701 ICU
  [n] PIBR1.PIR{n} (n=0..7)
0x87702 ICU
  [n] PIBR2.PIR{n} (n=0..7)
0x87703 ICU
  [n] PIBR3.PIR{n} (n=0..7)
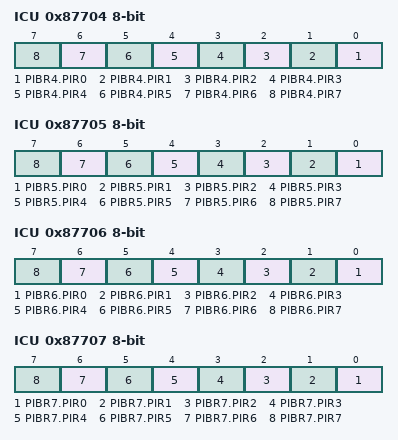
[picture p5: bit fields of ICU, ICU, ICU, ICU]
0x87704 ICU
  [n] PIBR4.PIR{n} (n=0..7)
0x87705 ICU
  [n] PIBR5.PIR{n} (n=0..7)
0x87706 ICU
  [n] PIBR6.PIR{n} (n=0..7)
0x87707 ICU
  [n] PIBR7.PIR{n} (n=0..7)
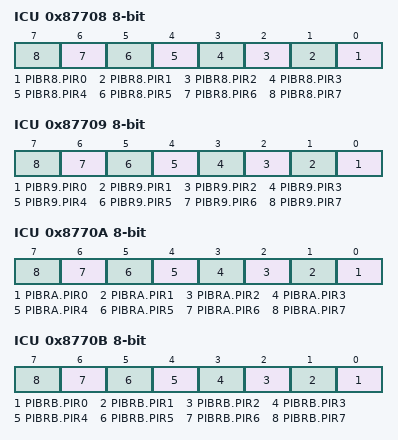
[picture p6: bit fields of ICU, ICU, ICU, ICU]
0x87708 ICU
  [n] PIBR8.PIR{n} (n=0..7)
0x87709 ICU
  [n] PIBR9.PIR{n} (n=0..7)
0x8770A ICU
  [n] PIBRA.PIR{n} (n=0..7)
0x8770B ICU
  [n] PIBRB.PIR{n} (n=0..7)
0x87780 ICU
  [7:0] SLIBXR128.SLI
0x87781 ICU
  [7:0] SLIBXR129.SLI
0x87782 ICU
  [7:0] SLIBXR130.SLI
0x87783 ICU
  [7:0] SLIBXR131.SLI
0x87784 ICU
  [7:0] SLIBXR132.SLI
0x87785 ICU
  [7:0] SLIBXR133.SLI
0x87786 ICU
  [7:0] SLIBXR134.SLI
0x87787 ICU
  [7:0] SLIBXR135.SLI
0x87788 ICU
  [7:0] SLIBXR136.SLI
0x87789 ICU
  [7:0] SLIBXR137.SLI
0x8778A ICU
  [7:0] SLIBXR138.SLI
0x8778B ICU
  [7:0] SLIBXR139.SLI
0x8778C ICU
  [7:0] SLIBXR140.SLI
0x8778D ICU
  [7:0] SLIBXR141.SLI
0x8778E ICU
  [7:0] SLIBXR142.SLI
0x8778F ICU
  [7:0] SLIBXR143.SLI
0x87790 ICU
  [7:0] SLIBR144.SLI
0x87791 ICU
  [7:0] SLIBR145.SLI
0x87792 ICU
  [7:0] SLIBR146.SLI
0x87793 ICU
  [7:0] SLIBR147.SLI
0x87794 ICU
  [7:0] SLIBR148.SLI
0x87795 ICU
  [7:0] SLIBR149.SLI
0x87796 ICU
  [7:0] SLIBR150.SLI
0x87797 ICU
  [7:0] SLIBR151.SLI
0x87798 ICU
  [7:0] SLIBR152.SLI
0x87799 ICU
  [7:0] SLIBR153.SLI
0x8779A ICU
  [7:0] SLIBR154.SLI
0x8779B ICU
  [7:0] SLIBR155.SLI
0x8779C ICU
  [7:0] SLIBR156.SLI
0x8779D ICU
  [7:0] SLIBR157.SLI
0x8779E ICU
  [7:0] SLIBR158.SLI
0x8779F ICU
  [7:0] SLIBR159.SLI
0x877A0 ICU
  [7:0] SLIBR160.SLI
0x877A1 ICU
  [7:0] SLIBR161.SLI
0x877A2 ICU
  [7:0] SLIBR162.SLI
0x877A3 ICU
  [7:0] SLIBR163.SLI
0x877A4 ICU
  [7:0] SLIBR164.SLI
0x877A5 ICU
  [7:0] SLIBR165.SLI
0x877A6 ICU
  [7:0] SLIBR166.SLI
0x877A7 ICU
  [7:0] SLIBR167.SLI
0x877A8 ICU
  [7:0] SLIBR168.SLI
0x877A9 ICU
  [7:0] SLIBR169.SLI
0x877AA ICU
  [7:0] SLIBR170.SLI
0x877AB ICU
  [7:0] SLIBR171.SLI
0x877AC ICU
  [7:0] SLIBR172.SLI
0x877AD ICU
  [7:0] SLIBR173.SLI
0x877AE ICU
  [7:0] SLIBR174.SLI
0x877AF ICU
  [7:0] SLIBR175.SLI
0x877B0 ICU
  [7:0] SLIBR176.SLI
0x877B1 ICU
  [7:0] SLIBR177.SLI
0x877B2 ICU
  [7:0] SLIBR178.SLI
0x877B3 ICU
  [7:0] SLIBR179.SLI
0x877B4 ICU
  [7:0] SLIBR180.SLI
0x877B5 ICU
  [7:0] SLIBR181.SLI
0x877B6 ICU
  [7:0] SLIBR182.SLI
0x877B7 ICU
  [7:0] SLIBR183.SLI
0x877B8 ICU
  [7:0] SLIBR184.SLI
0x877B9 ICU
  [7:0] SLIBR185.SLI
0x877BA ICU
  [7:0] SLIBR186.SLI
0x877BB ICU
  [7:0] SLIBR187.SLI
0x877BC ICU
  [7:0] SLIBR188.SLI
0x877BD ICU
  [7:0] SLIBR189.SLI
0x877BE ICU
  [7:0] SLIBR190.SLI
0x877BF ICU
  [7:0] SLIBR191.SLI
0x877C0 ICU
  [7:0] SLIBR192.SLI
0x877C1 ICU
  [7:0] SLIBR193.SLI
0x877C2 ICU
  [7:0] SLIBR194.SLI
0x877C3 ICU
  [7:0] SLIBR195.SLI
0x877C4 ICU
  [7:0] SLIBR196.SLI
0x877C5 ICU
  [7:0] SLIBR197.SLI
0x877C6 ICU
  [7:0] SLIBR198.SLI
0x877C7 ICU
  [7:0] SLIBR199.SLI
0x877C8 ICU
  [7:0] SLIBR200.SLI
0x877C9 ICU
  [7:0] SLIBR201.SLI
0x877CA ICU
  [7:0] SLIBR202.SLI
0x877CB ICU
  [7:0] SLIBR203.SLI
0x877CC ICU
  [7:0] SLIBR204.SLI
0x877CD ICU
  [7:0] SLIBR205.SLI
0x877CE ICU
  [7:0] SLIBR206.SLI
0x877CF ICU
  [7:0] SLIBR207.SLI
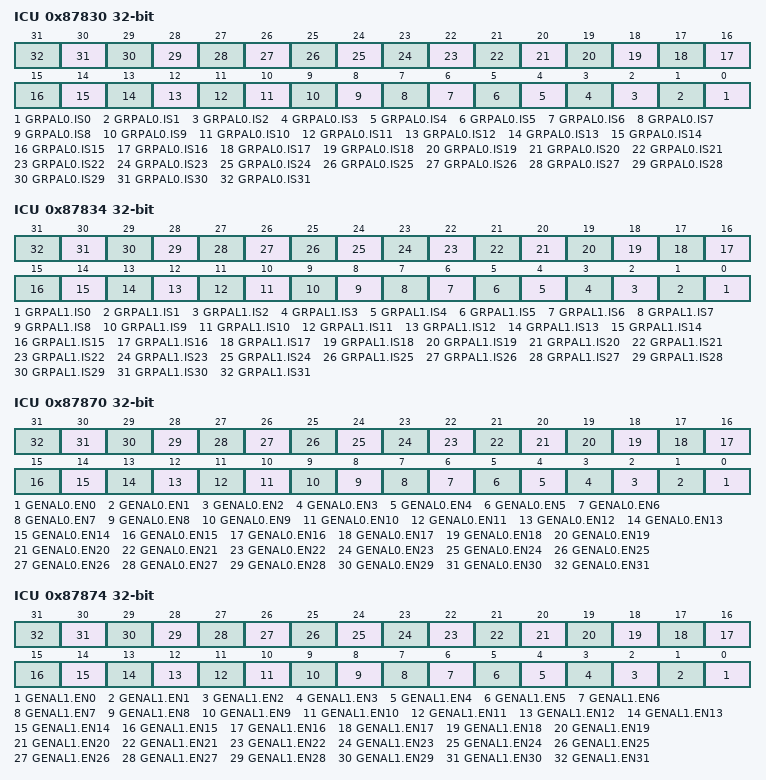
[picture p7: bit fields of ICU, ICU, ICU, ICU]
0x87830 ICU 32-bit
  [n] GRPAL0.IS{n} (n=0..31)
0x87834 ICU 32-bit
  [n] GRPAL1.IS{n} (n=0..31)
0x87870 ICU 32-bit
  [n] GENAL0.EN{n} (n=0..31)
0x87874 ICU 32-bit
  [n] GENAL1.EN{n} (n=0..31)
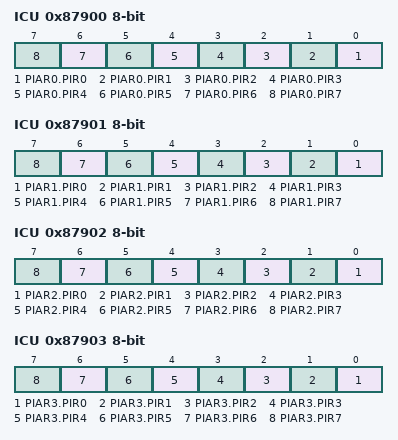
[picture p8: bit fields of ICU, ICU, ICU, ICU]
0x87900 ICU
  [n] PIAR0.PIR{n} (n=0..7)
0x87901 ICU
  [n] PIAR1.PIR{n} (n=0..7)
0x87902 ICU
  [n] PIAR2.PIR{n} (n=0..7)
0x87903 ICU
  [n] PIAR3.PIR{n} (n=0..7)
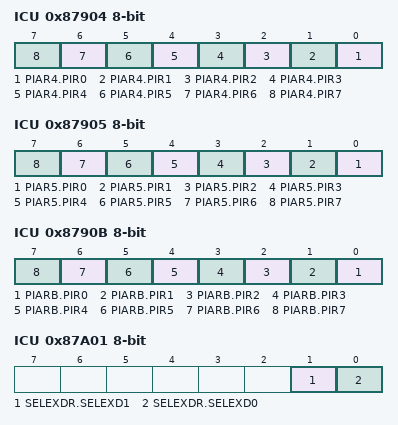
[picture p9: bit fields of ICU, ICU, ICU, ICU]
0x87904 ICU
  [n] PIAR4.PIR{n} (n=0..7)
0x87905 ICU
  [n] PIAR5.PIR{n} (n=0..7)
0x8790B ICU
  [n] PIARB.PIR{n} (n=0..7)
0x87A00 ICU
  [0] SLIPRCR.WPRC
0x87A01 ICU
  [1] SELEXDR.SELEXD1, [0] SELEXDR.SELEXD0
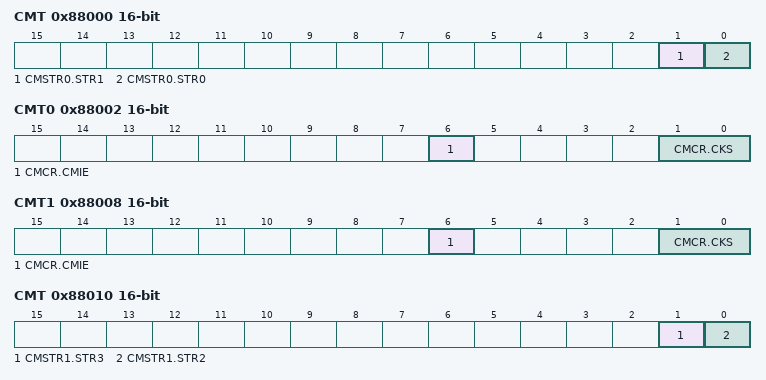
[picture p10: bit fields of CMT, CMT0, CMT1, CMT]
0x88000 CMT 16-bit
  [1] CMSTR0.STR1, [0] CMSTR0.STR0
0x88002 CMT0 16-bit
  [6] CMCR.CMIE, [1:0] CMCR.CKS
0x88008 CMT1 16-bit
  [6] CMCR.CMIE, [1:0] CMCR.CKS
0x88010 CMT 16-bit
  [1] CMSTR1.STR3, [0] CMSTR1.STR2
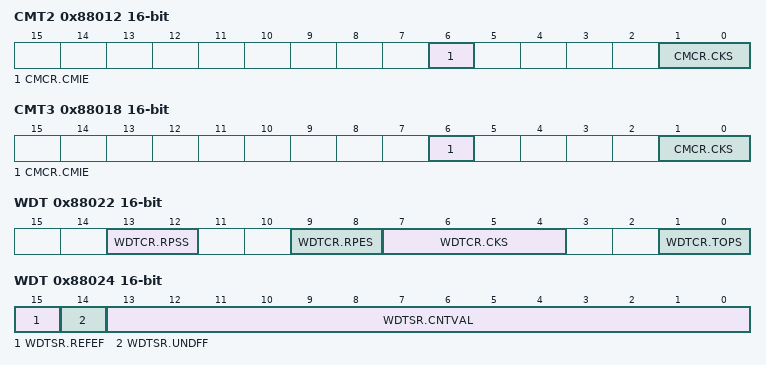
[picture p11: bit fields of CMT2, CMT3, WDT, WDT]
0x88012 CMT2 16-bit
  [6] CMCR.CMIE, [1:0] CMCR.CKS
0x88018 CMT3 16-bit
  [6] CMCR.CMIE, [1:0] CMCR.CKS
0x88022 WDT 16-bit
  [13:12] WDTCR.RPSS, [9:8] WDTCR.RPES, [7:4] WDTCR.CKS, [1:0] WDTCR.TOPS
0x88024 WDT 16-bit
  [15] WDTSR.REFEF, [14] WDTSR.UNDFF, [13:0] WDTSR.CNTVAL
0x88026 WDT
  [7] WDTRCR.RSTIRQS
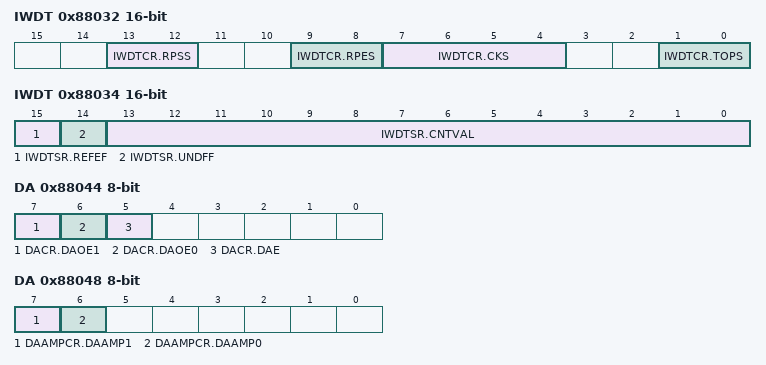
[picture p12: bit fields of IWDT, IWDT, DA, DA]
0x88032 IWDT 16-bit
  [13:12] IWDTCR.RPSS, [9:8] IWDTCR.RPES, [7:4] IWDTCR.CKS, [1:0] IWDTCR.TOPS
0x88034 IWDT 16-bit
  [15] IWDTSR.REFEF, [14] IWDTSR.UNDFF, [13:0] IWDTSR.CNTVAL
0x88036 IWDT
  [7] IWDTRCR.RSTIRQS
0x88038 IWDT
  [7] IWDTCSTPR.SLCSTP
0x88044 DA
  [7] DACR.DAOE1, [6] DACR.DAOE0, [5] DACR.DAE
0x88045 DA
  [7] DADPR.DPSEL
0x88046 DA
  [7] DAADSCR.DAADST
0x88048 DA
  [7] DAAMPCR.DAAMP1, [6] DAAMPCR.DAAMP0
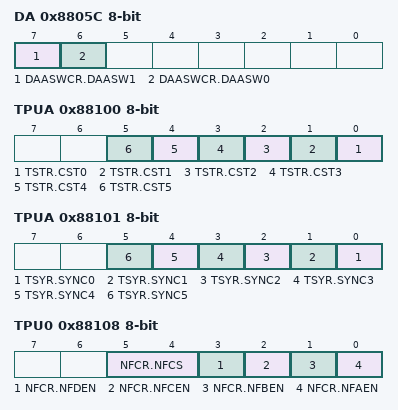
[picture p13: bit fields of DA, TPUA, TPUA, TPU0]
0x8805C DA
  [7] DAASWCR.DAASW1, [6] DAASWCR.DAASW0
0x88100 TPUA
  [n] TSTR.CST{n} (n=0..5)
0x88101 TPUA
  [n] TSYR.SYNC{n} (n=0..5)
0x88108 TPU0
  [5:4] NFCR.NFCS, [3] NFCR.NFDEN, [2] NFCR.NFCEN, [1] NFCR.NFBEN, [0] NFCR.NFAEN
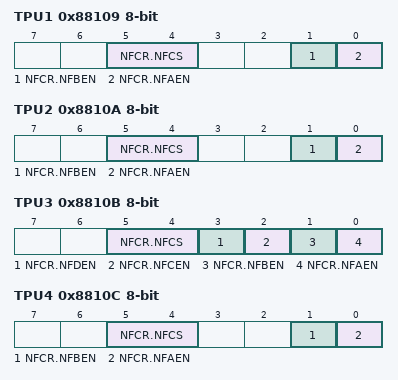
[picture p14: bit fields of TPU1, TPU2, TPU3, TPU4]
0x88109 TPU1
  [5:4] NFCR.NFCS, [1] NFCR.NFBEN, [0] NFCR.NFAEN
0x8810A TPU2
  [5:4] NFCR.NFCS, [1] NFCR.NFBEN, [0] NFCR.NFAEN
0x8810B TPU3
  fields as TPU0
0x8810C TPU4
  [5:4] NFCR.NFCS, [1] NFCR.NFBEN, [0] NFCR.NFAEN
0x8810D TPU5
  [5:4] NFCR.NFCS, [1] NFCR.NFBEN, [0] NFCR.NFAEN
0x88110 TPU0
  [7:5] TCR.CCLR, [4:3] TCR.CKEG, [2:0] TCR.TPSC
0x88111 TPU0
  [7] TMDR.ICSELD, [6] TMDR.ICSELB, [5] TMDR.BFB, [4] TMDR.BFA, [3:0] TMDR.MD
0x88112 TPU0
  [7:4] TIORH.IOB, [3:0] TIORH.IOA
0x88113 TPU0
  [7:4] TIORL.IOD, [3:0] TIORL.IOC
0x88114 TPU0
  [7] TIER.TTGE, [4] TIER.TCIEV, [3] TIER.TGIED, [2] TIER.TGIEC, [1] TIER.TGIEB, [0] TIER.TGIEA
0x88115 TPU0
  [4] TSR.TCFV, [3] TSR.TGFD, [2] TSR.TGFC, [1] TSR.TGFB, [0] TSR.TGFA
0x88120 TPU1
  [6:5] TCR.CCLR, [4:3] TCR.CKEG, [2:0] TCR.TPSC
0x88121 TPU1
  [6] TMDR.ICSELB, [3:0] TMDR.MD
0x88122 TPU1
  [7:4] TIOR.IOB, [3:0] TIOR.IOA
0x88124 TPU1
  [7] TIER.TTGE, [5] TIER.TCIEU, [4] TIER.TCIEV, [1] TIER.TGIEB, [0] TIER.TGIEA
0x88125 TPU1
  [7] TSR.TCFD, [5] TSR.TCFU, [4] TSR.TCFV, [1] TSR.TGFB, [0] TSR.TGFA
0x88130 TPU2
  [6:5] TCR.CCLR, [4:3] TCR.CKEG, [2:0] TCR.TPSC
0x88131 TPU2
  [6] TMDR.ICSELB, [3:0] TMDR.MD
0x88132 TPU2
  [7:4] TIOR.IOB, [3:0] TIOR.IOA
0x88134 TPU2
  [7] TIER.TTGE, [5] TIER.TCIEU, [4] TIER.TCIEV, [1] TIER.TGIEB, [0] TIER.TGIEA
0x88135 TPU2
  [7] TSR.TCFD, [5] TSR.TCFU, [4] TSR.TCFV, [1] TSR.TGFB, [0] TSR.TGFA
0x88140 TPU3
  [7:5] TCR.CCLR, [4:3] TCR.CKEG, [2:0] TCR.TPSC
0x88141 TPU3
  [7] TMDR.ICSELD, [6] TMDR.ICSELB, [5] TMDR.BFB, [4] TMDR.BFA, [3:0] TMDR.MD
0x88142 TPU3
  [7:4] TIORH.IOB, [3:0] TIORH.IOA
0x88143 TPU3
  [7:4] TIORL.IOD, [3:0] TIORL.IOC
0x88144 TPU3
  [7] TIER.TTGE, [4] TIER.TCIEV, [3] TIER.TGIED, [2] TIER.TGIEC, [1] TIER.TGIEB, [0] TIER.TGIEA
0x88145 TPU3
  [4] TSR.TCFV, [3] TSR.TGFD, [2] TSR.TGFC, [1] TSR.TGFB, [0] TSR.TGFA
0x88150 TPU4
  [6:5] TCR.CCLR, [4:3] TCR.CKEG, [2:0] TCR.TPSC
0x88151 TPU4
  [6] TMDR.ICSELB, [3:0] TMDR.MD
0x88152 TPU4
  [7:4] TIOR.IOB, [3:0] TIOR.IOA
0x88154 TPU4
  [7] TIER.TTGE, [5] TIER.TCIEU, [4] TIER.TCIEV, [1] TIER.TGIEB, [0] TIER.TGIEA
0x88155 TPU4
  [7] TSR.TCFD, [5] TSR.TCFU, [4] TSR.TCFV, [1] TSR.TGFB, [0] TSR.TGFA
0x88160 TPU5
  [6:5] TCR.CCLR, [4:3] TCR.CKEG, [2:0] TCR.TPSC
0x88161 TPU5
  [6] TMDR.ICSELB, [3:0] TMDR.MD
0x88162 TPU5
  [7:4] TIOR.IOB, [3:0] TIOR.IOA
0x88164 TPU5
  [5] TIER.TCIEU, [4] TIER.TCIEV, [1] TIER.TGIEB, [0] TIER.TGIEA
0x88165 TPU5
  [7] TSR.TCFD, [5] TSR.TCFU, [4] TSR.TCFV, [1] TSR.TGFB, [0] TSR.TGFA
0x881E6 PPG0
  [2n+1:2n] PCR.G{n}CMS (n=0..3)
0x881E7 PPG0
  [n+4] PMR.G{n}INV (n=0..3), [n] PMR.G{n}NOV (n=0..3)
0x881E8 PPG0
  [n-8] NDERH.NDER{n} (n=8..15)
0x881E9 PPG0
  [n] NDERL.NDER{n} (n=0..7)
0x881EA PPG0
  [n-8] PODRH.POD{n} (n=8..15)
0x881EB PPG0
  [n] PODRL.POD{n} (n=0..7)
0x881EC PPG0
  [n-8] NDRH.NDR{n} (n=8..15)
0x881ED PPG0
  [n] NDRL.NDR{n} (n=0..7)
0x881EE PPG0
  [n-8] NDRH2.NDR{n} (n=8..11)
0x881EF PPG0
  [n] NDRL2.NDR{n} (n=0..3)
0x881F0 PPG1
  [0] PTRSLR.PTRSL
0x881F6 PPG1
  [2n+1:2n] PCR.G{n}CMS (n=0..3)
0x881F7 PPG1
  [n+4] PMR.G{n}INV (n=0..3), [n] PMR.G{n}NOV (n=0..3)
0x881F8 PPG1
  [n-24] NDERH.NDER{n} (n=24..31)
0x881F9 PPG1
  [n-16] NDERL.NDER{n} (n=16..23)
0x881FA PPG1
  [n-24] PODRH.POD{n} (n=24..31)
0x881FB PPG1
  [n-16] PODRL.POD{n} (n=16..23)
0x881FC PPG1
  [n-24] NDRH.NDR{n} (n=24..31)
0x881FD PPG1
  [n-16] NDRL.NDR{n} (n=16..23)
0x881FE PPG1
  [n-24] NDRH2.NDR{n} (n=24..27)
0x881FF PPG1
  [n-16] NDRL2.NDR{n} (n=16..19)
0x88200 TMR0
  [7] TCR.CMIEB, [6] TCR.CMIEA, [5] TCR.OVIE, [4:3] TCR.CCLR
0x88201 TMR1
  [7] TCR.CMIEB, [6] TCR.CMIEA, [5] TCR.OVIE, [4:3] TCR.CCLR
0x88202 TMR0
  [4] TCSR.ADTE, [3:2] TCSR.OSB, [1:0] TCSR.OSA
0x88203 TMR1
  [3:2] TCSR.OSB, [1:0] TCSR.OSA
0x8820A TMR0
  [7] TCCR.TMRIS, [4:3] TCCR.CSS, [2:0] TCCR.CKS
0x8820B TMR1
  [7] TCCR.TMRIS, [4:3] TCCR.CSS, [2:0] TCCR.CKS
0x8820C TMR0
  [0] TCSTR.TCS
0x8820D TMR1
  [0] TCSTR.TCS
0x88210 TMR2
  [7] TCR.CMIEB, [6] TCR.CMIEA, [5] TCR.OVIE, [4:3] TCR.CCLR
0x88211 TMR3
  [7] TCR.CMIEB, [6] TCR.CMIEA, [5] TCR.OVIE, [4:3] TCR.CCLR
0x88212 TMR2
  [4] TCSR.ADTE, [3:2] TCSR.OSB, [1:0] TCSR.OSA
0x88213 TMR3
  [3:2] TCSR.OSB, [1:0] TCSR.OSA
0x8821A TMR2
  [7] TCCR.TMRIS, [4:3] TCCR.CSS, [2:0] TCCR.CKS
0x8821B TMR3
  [7] TCCR.TMRIS, [4:3] TCCR.CSS, [2:0] TCCR.CKS
0x8821C TMR2
  [0] TCSTR.TCS
0x8821D TMR3
  [0] TCSTR.TCS
0x88280 CRC
  [7] CRCCR.DORCLR, [6] CRCCR.LMS, [2:0] CRCCR.GPS
{0x88300+0x20*i} RIIC{i} (i=0..2)
  [7] ICCR1.ICE, [6] ICCR1.IICRST, [5] ICCR1.CLO, [4] ICCR1.SOWP, [3] ICCR1.SCLO, [2] ICCR1.SDAO, [1] ICCR1.SCLI, [0] ICCR1.SDAI
{0x88301+0x20*i} RIIC{i} (i=0..2)
  [7] ICCR2.BBSY, [6] ICCR2.MST, [5] ICCR2.TRS, [3] ICCR2.SP, [2] ICCR2.RS, [1] ICCR2.ST
{0x88302+0x20*i} RIIC{i} (i=0..2)
  [7] ICMR1.MTWP, [6:4] ICMR1.CKS, [3] ICMR1.BCWP, [2:0] ICMR1.BC
{0x88303+0x20*i} RIIC{i} (i=0..2)
  [7] ICMR2.DLCS, [6:4] ICMR2.SDDL, [2] ICMR2.TMOH, [1] ICMR2.TMOL, [0] ICMR2.TMOS
{0x88304+0x20*i} RIIC{i} (i=0..2)
  [7] ICMR3.SMBS, [6] ICMR3.WAIT, [5] ICMR3.RDRFS, [4] ICMR3.ACKWP, [3] ICMR3.ACKBT, [2] ICMR3.ACKBR, [1:0] ICMR3.NF
{0x88305+0x20*i} RIIC{i} (i=0..2)
  [7] ICFER.FMPE, [6] ICFER.SCLE, [5] ICFER.NFE, [4] ICFER.NACKE, [3] ICFER.SALE, [2] ICFER.NALE, [1] ICFER.MALE, [0] ICFER.TMOE
{0x88306+0x20*i} RIIC{i} (i=0..2)
  [7] ICSER.HOAE, [5] ICSER.DIDE, [3] ICSER.GCAE, [2] ICSER.SAR2E, [1] ICSER.SAR1E, [0] ICSER.SAR0E
{0x88307+0x20*i} RIIC{i} (i=0..2)
  [7] ICIER.TIE, [6] ICIER.TEIE, [5] ICIER.RIE, [4] ICIER.NAKIE, [3] ICIER.SPIE, [2] ICIER.STIE, [1] ICIER.ALIE, [0] ICIER.TMOIE
{0x88308+0x20*i} RIIC{i} (i=0..2)
  [7] ICSR1.HOA, [5] ICSR1.DID, [3] ICSR1.GCA, [2] ICSR1.AAS2, [1] ICSR1.AAS1, [0] ICSR1.AAS0
{0x88309+0x20*i} RIIC{i} (i=0..2)
  [7] ICSR2.TDRE, [6] ICSR2.TEND, [5] ICSR2.RDRF, [4] ICSR2.NACKF, [3] ICSR2.STOP, [2] ICSR2.START, [1] ICSR2.AL, [0] ICSR2.TMOF
0x8830A RIIC0
  [7:1] SARL0.SVA, [0] SARL0.SVA0
0x8830B RIIC0
  [2:1] SARU0.SVA, [0] SARU0.FS
0x8830C RIIC0
  [7:1] SARL1.SVA, [0] SARL1.SVA0
0x8830D RIIC0
  [2:1] SARU1.SVA, [0] SARU1.FS
0x8830E RIIC0
  [7:1] SARL2.SVA, [0] SARL2.SVA0
0x8830F RIIC0
  [2:1] SARU2.SVA, [0] SARU2.FS
{0x88310+0x20*i} RIIC{i} (i=0..2)
  [4:0] ICBRL.BRL
{0x88311+0x20*i} RIIC{i} (i=0..2)
  [4:0] ICBRH.BRH
0x8832A RIIC1
  [7:1] SARL0.SVA, [0] SARL0.SVA0
0x8832B RIIC1
  [2:1] SARU0.SVA, [0] SARU0.FS
0x8832C RIIC1
  [7:1] SARL1.SVA, [0] SARL1.SVA0
0x8832D RIIC1
  [2:1] SARU1.SVA, [0] SARU1.FS
0x8832E RIIC1
  [7:1] SARL2.SVA, [0] SARL2.SVA0
0x8832F RIIC1
  [2:1] SARU2.SVA, [0] SARU2.FS
0x8834A RIIC2
  [7:1] SARL0.SVA, [0] SARL0.SVA0
0x8834B RIIC2
  [2:1] SARU0.SVA, [0] SARU0.FS
0x8834C RIIC2
  [7:1] SARL1.SVA, [0] SARL1.SVA0
0x8834D RIIC2
  [2:1] SARU1.SVA, [0] SARU1.FS
0x8834E RIIC2
  [7:1] SARL2.SVA, [0] SARL2.SVA0
0x8834F RIIC2
  [2:1] SARU2.SVA, [0] SARU2.FS
0x88500 MMCIF 32-bit
  [30] CECMDSET.BOOT, [29:24] CECMDSET.CMD, [23:22] CECMDSET.RTYP, [21] CECMDSET.RBSY, [19] CECMDSET.WDAT, [18] CECMDSET.DWEN, [17] CECMDSET.CMLTE, [16] CECMDSET.CMD12EN, [15:14] CECMDSET.RIDXC, [13:12] CECMDSET.RCRC7C, [10] CECMDSET.CRC16C, [9] CECMDSET.BOOTACK, [8] CECMDSET.CRCSTE, [7] CECMDSET.TBIT, [6] CECMDSET.OPDM, [3] CECMDSET.SBIT, [1:0] CECMDSET.DATW
0x8850C MMCIF 32-bit
  [31:0] CEARGCMD12.C12ARG
0x88510 MMCIF 32-bit
  [0] CECMDCTRL.BREAK
0x88514 MMCIF 32-bit
  [31:16] CEBLOCKSET.BLKCNT, [15:0] CEBLOCKSET.BLKSIZ
0x88518 MMCIF 32-bit
  [31] CECLKCTRL.MMCBUSBSY, [24] CECLKCTRL.CLKEN, [19:16] CECLKCTRL.CLKDIV, [13:12] CECLKCTRL.SRSPTO, [11:8] CECLKCTRL.SRBSYTO, [7:4] CECLKCTRL.SRWDTO
0x8851C MMCIF 32-bit
  [26] CEBUFACC.DMATYP, [25] CEBUFACC.DMAWEN, [24] CEBUFACC.DMAREN, [16] CEBUFACC.ATYP
0x88530 MMCIF 32-bit
  [31:0] CERESPCMD12.RSP12
0x88534 MMCIF 32-bit
  [31:0] CEDATA.DATA
0x8853C MMCIF 32-bit
  [31:28] CEBOOT.SBTCLKDIV, [27:24] CEBOOT.SBTACKTO, [23:20] CEBOOT.SFSTBTDATTO, [19:16] CEBOOT.SBTDATTO
0x88540 MMCIF 32-bit
  [26] CEINT.CMD12DRE, [25] CEINT.CMD12RBE, [24] CEINT.CMD12CRE, [23] CEINT.DTRANE, [22] CEINT.BUFRE, [21] CEINT.BUFWEN, [20] CEINT.BUFREN, [17] CEINT.RBSYE, [16] CEINT.CRSPE, [15] CEINT.CMDVIO, [14] CEINT.BUFVIO, [11] CEINT.WDATERR, [10] CEINT.RDATERR, [9] CEINT.RIDXERR, [8] CEINT.RSPERR, [4] CEINT.CRCSTO, [3] CEINT.WDATTO, [2] CEINT.RDATTO, [1] CEINT.RBSYTO, [0] CEINT.RSPTO
0x88544 MMCIF 32-bit
  [26] CEINTEN.MCMD12DRE, [25] CEINTEN.MCMD12RBE, [24] CEINTEN.MCMD12CRE, [23] CEINTEN.MDTRANE, [22] CEINTEN.MBUFRE, [21] CEINTEN.MBUFWEN, [20] CEINTEN.MBUFREN, [17] CEINTEN.MRBSYE, [16] CEINTEN.MCRSPE, [15] CEINTEN.MCMDVIO, [14] CEINTEN.MBUFVIO, [11] CEINTEN.MWDATERR, [10] CEINTEN.MRDATERR, [9] CEINTEN.MRIDXERR, [8] CEINTEN.MRSPERR, [4] CEINTEN.MCRCSTO, [3] CEINTEN.MWDATTO, [2] CEINTEN.MRDATTO, [1] CEINTEN.MRBSYTO, [0] CEINTEN.MRSPTO
0x88548 MMCIF 32-bit
  [31] CEHOSTSTS1.CMDSEQ, [30] CEHOSTSTS1.CMDSIG, [29:24] CEHOSTSTS1.RSPIDX, [23:16] CEHOSTSTS1.DATSIG, [15:0] CEHOSTSTS1.RCVBLK
0x8854C MMCIF 32-bit
  [31] CEHOSTSTS2.CRCSTE, [30] CEHOSTSTS2.CRC16E, [29] CEHOSTSTS2.AC12CRCE, [28] CEHOSTSTS2.RSPCRC7E, [27] CEHOSTSTS2.CRCSTEBE, [26] CEHOSTSTS2.RDATEBE, [25] CEHOSTSTS2.AC12REBE, [24] CEHOSTSTS2.RSPEBE, [23] CEHOSTSTS2.AC12IDXE, [22] CEHOSTSTS2.RSPIDXE, [21] CEHOSTSTS2.BTACKPATE, [20] CEHOSTSTS2.BTACKEBE, [18:16] CEHOSTSTS2.CRCST, [14] CEHOSTSTS2.STRDATTO, [13] CEHOSTSTS2.DATBSYTO, [12] CEHOSTSTS2.CRCSTTO, [11] CEHOSTSTS2.AC12BSYTO, [10] CEHOSTSTS2.RSPBSYTO, [9] CEHOSTSTS2.AC12RSPTO, [8] CEHOSTSTS2.STRSPTO, [7] CEHOSTSTS2.BTACKTO, [6] CEHOSTSTS2.FSTBTDATTO, [5] CEHOSTSTS2.BTDATTO
0x88570 MMCIF 32-bit
  [14] CEDETECT.CDSIG, [13] CEDETECT.CDRISE, [12] CEDETECT.CDFALL, [5] CEDETECT.MCDRISE, [4] CEDETECT.MCDFALL
0x88574 MMCIF 32-bit
  [21] CEADDMODE.RESNOUT, [19] CEADDMODE.CLKMAIN
0x8857C MMCIF 32-bit
  [31] CEVERSION.SWRST, [15:0] CEVERSION.VERSION
0x89000 S12AD 16-bit
  [15] ADCSR.ADST, [14:13] ADCSR.ADCS, [12] ADCSR.ADIE, [9] ADCSR.TRGE, [8] ADCSR.EXTRG, [7] ADCSR.DBLE, [6] ADCSR.GBADIE, [4:0] ADCSR.DBLANS
0x89004 S12AD 16-bit
  [n] ADANSA0.ANSA{n:03} (n=0..7)
0x89008 S12AD 16-bit
  [n] ADADS0.ADS{n:03} (n=0..7)
0x8900C S12AD
  [7] ADADC.AVEE, [2:0] ADADC.ADC
0x8900E S12AD 16-bit
  [15] ADCER.ADRFMT, [11] ADCER.DIAGM, [10] ADCER.DIAGLD, [9:8] ADCER.DIAGVAL, [5] ADCER.ACE, [2:1] ADCER.ADPRC
0x89010 S12AD 16-bit
  [13:8] ADSTRGR.TRSA, [5:0] ADSTRGR.TRSB
0x89014 S12AD 16-bit
  [n] ADANSB0.ANSB{n:03} (n=0..7)
0x8901E S12AD 16-bit
  [15:14] ADRD.RIGHT.DIAGST, [15:4] ADRD.LEFT.AD, [11:0] ADRD.RIGHT.AD, [1:0] ADRD.LEFT.DIAGST
0x89063 S12AD
  [1:0] ADSAMPR.PRO
0x89066 S12AD 16-bit
  [10:8] ADSHCR.SHANS, [7:0] ADSHCR.SSTSH
0x8906E S12AD 16-bit
  [5] ADSAM.SAM
0x8907A S12AD
  [4:0] ADDISCR.ADNDIS
0x8907C S12AD
  [0] ADSHMSR.SHMD
0x89080 S12AD 16-bit
  [15] ADGSPCR.GBRP, [14] ADGSPCR.LGRRS, [1] ADGSPCR.GBRSCN, [0] ADGSPCR.PGS
0x8908C S12AD
  [5] ADWINMON.MONCMPB, [4] ADWINMON.MONCMPA, [0] ADWINMON.MONCOMB
0x89090 S12AD 16-bit
  [15] ADCMPCR.CMPAIE, [14] ADCMPCR.WCMPE, [13] ADCMPCR.CMPBIE, [11] ADCMPCR.CMPAE, [9] ADCMPCR.CMPBE, [1:0] ADCMPCR.CMPAB
0x89094 S12AD 16-bit
  [n] ADCMPANSR0.CMPCHA{n:03} (n=0..7)
0x89098 S12AD 16-bit
  [n] ADCMPLR0.CMPLCHA{n:03} (n=0..7)
0x890A0 S12AD 16-bit
  [n] ADCMPSR0.CMPSTCHA{n:03} (n=0..7)
0x890A6 S12AD
  [7] ADCMPBNSR.CMPLB, [5:0] ADCMPBNSR.CMPCHB
0x890AC S12AD
  [0] ADCMPBSR.CMPSTB
0x890D4 S12AD 16-bit
  [n] ADANSC0.ANSC{n:03} (n=0..7)
0x890D9 S12AD
  [7] ADGCTRGR.GRCE, [6] ADGCTRGR.GCADIE, [5:0] ADGCTRGR.TRSC
0x89100 S12AD1 16-bit
  fields as S12AD
0x89104 S12AD1 16-bit
  [n] ADANSA0.ANSA{n:03} (n=0..15)
0x89106 S12AD1 16-bit
  [n-100] ADANSA1.ANSA{n} (n=100..104)
0x89108 S12AD1 16-bit
  [n] ADADS0.ADS{n:03} (n=0..15)
0x8910A S12AD1 16-bit
  [n-100] ADADS1.ADS{n} (n=100..104)
0x8910C S12AD1
  [7] ADADC.AVEE, [2:0] ADADC.ADC
0x8910E S12AD1 16-bit
  [15] ADCER.ADRFMT, [11] ADCER.DIAGM, [10] ADCER.DIAGLD, [9:8] ADCER.DIAGVAL, [5] ADCER.ACE, [2:1] ADCER.ADPRC
0x89110 S12AD1 16-bit
  [13:8] ADSTRGR.TRSA, [5:0] ADSTRGR.TRSB
0x89112 S12AD1 16-bit
  [15] ADEXICR.EXOEN, [14:13] ADEXICR.EXSEL, [11] ADEXICR.OCSB, [10] ADEXICR.TSSB, [9] ADEXICR.OCSA, [8] ADEXICR.TSSA, [1] ADEXICR.OCSAD, [0] ADEXICR.TSSAD
0x89114 S12AD1 16-bit
  [n] ADANSB0.ANSB{n:03} (n=0..15)
0x89116 S12AD1 16-bit
  [n-100] ADANSB1.ANSB{n} (n=100..104)
0x8911E S12AD1 16-bit
  [15:14] ADRD.RIGHT.DIAGST, [15:4] ADRD.LEFT.AD, [11:0] ADRD.RIGHT.AD, [1:0] ADRD.LEFT.DIAGST
0x89163 S12AD1
  [1:0] ADSAMPR.PRO
0x8916E S12AD1 16-bit
  [5] ADSAM.SAM
0x8917A S12AD1
  [4:0] ADDISCR.ADNDIS
0x89180 S12AD1 16-bit
  [15] ADGSPCR.GBRP, [14] ADGSPCR.LGRRS, [1] ADGSPCR.GBRSCN, [0] ADGSPCR.PGS
0x8918C S12AD1
  [5] ADWINMON.MONCMPB, [4] ADWINMON.MONCMPA, [0] ADWINMON.MONCOMB
0x89190 S12AD1 16-bit
  [15] ADCMPCR.CMPAIE, [14] ADCMPCR.WCMPE, [13] ADCMPCR.CMPBIE, [11] ADCMPCR.CMPAE, [9] ADCMPCR.CMPBE, [1:0] ADCMPCR.CMPAB
0x89192 S12AD1
  [1] ADCMPANSER.CMPSOC, [0] ADCMPANSER.CMPSTS
0x89193 S12AD1
  [1] ADCMPLER.CMPLOC, [0] ADCMPLER.CMPLTS
0x89194 S12AD1 16-bit
  [n] ADCMPANSR0.CMPCHA{n:03} (n=0..15)
0x89196 S12AD1 16-bit
  [n-100] ADCMPANSR1.CMPCHA{n} (n=100..104)
0x89198 S12AD1 16-bit
  [n] ADCMPLR0.CMPLCHA{n:03} (n=0..15)
0x8919A S12AD1 16-bit
  [n-100] ADCMPLR1.CMPLCHA{n} (n=100..104)
0x891A0 S12AD1 16-bit
  [n] ADCMPSR0.CMPSTCHA{n:03} (n=0..15)
0x891A2 S12AD1 16-bit
  [n-100] ADCMPSR1.CMPSTCHA{n} (n=100..104)
0x891A4 S12AD1
  [1] ADCMPSER.CMPFOC, [0] ADCMPSER.CMPFTS
0x891A6 S12AD1
  [7] ADCMPBNSR.CMPLB, [5:0] ADCMPBNSR.CMPCHB
0x891AC S12AD1
  [0] ADCMPBSR.CMPSTB
0x891D4 S12AD1 16-bit
  [n] ADANSC0.ANSC{n:03} (n=0..15)
0x891D6 S12AD1 16-bit
  [n-100] ADANSC1.ANSC{n} (n=100..104)
0x891D8 S12AD1
  [1] ADGCEXCR.OCSC, [0] ADGCEXCR.TSSC
0x891D9 S12AD1
  [7] ADGCTRGR.GRCE, [6] ADGCTRGR.GCADIE, [5:0] ADGCTRGR.TRSC
0x89E00 QSPI
  [7] SPCR.SPRIE, [6] SPCR.SPE, [5] SPCR.SPTIE, [3] SPCR.MSTR, [1] SPCR.SPSSLIE
0x89E01 QSPI
  [0] SSLP.SSLP
0x89E02 QSPI
  [5] SPPCR.MOIFE, [4] SPPCR.MOIFV, [2] SPPCR.IO3FV, [1] SPPCR.IO2FV, [0] SPPCR.SPLP
0x89E03 QSPI
  [7] SPSR.SPRFF, [6] SPSR.TREND, [5] SPSR.SPTEF, [4] SPSR.SPSSLF
0x89E08 QSPI
  [1:0] SPSCR.SPSC
0x89E09 QSPI
  [1:0] SPSSR.SPSS
0x89E0A QSPI
  [n] SPBR.SPBR{n} (n=0..7)
0x89E0B QSPI
  [7] SPDCR.TXDMY
0x89E0C QSPI
  [2:0] SPCKD.SCKDL
0x89E0D QSPI
  [2:0] SSLND.SLNDL
0x89E0E QSPI
  [2:0] SPND.SPNDL
0x89E10 QSPI 16-bit
  [15] SPCMD0.SCKDEN, [14] SPCMD0.SLNDEN, [13] SPCMD0.SPNDEN, [12] SPCMD0.LSBF, [11:8] SPCMD0.SPB, [7] SPCMD0.SSLKP, [6:5] SPCMD0.SPIMOD, [4] SPCMD0.SPRW, [3:2] SPCMD0.BRDV, [1] SPCMD0.CPOL, [0] SPCMD0.CPHA
0x89E12 QSPI 16-bit
  [15] SPCMD1.SCKDEN, [14] SPCMD1.SLNDEN, [13] SPCMD1.SPNDEN, [12] SPCMD1.LSBF, [11:8] SPCMD1.SPB, [7] SPCMD1.SSLKP, [6:5] SPCMD1.SPIMOD, [4] SPCMD1.SPRW, [3:2] SPCMD1.BRDV, [1] SPCMD1.CPOL, [0] SPCMD1.CPHA
0x89E14 QSPI 16-bit
  [15] SPCMD2.SCKDEN, [14] SPCMD2.SLNDEN, [13] SPCMD2.SPNDEN, [12] SPCMD2.LSBF, [11:8] SPCMD2.SPB, [7] SPCMD2.SSLKP, [6:5] SPCMD2.SPIMOD, [4] SPCMD2.SPRW, [3:2] SPCMD2.BRDV, [1] SPCMD2.CPOL, [0] SPCMD2.CPHA
0x89E16 QSPI 16-bit
  [15] SPCMD3.SCKDEN, [14] SPCMD3.SLNDEN, [13] SPCMD3.SPNDEN, [12] SPCMD3.LSBF, [11:8] SPCMD3.SPB, [7] SPCMD3.SSLKP, [6:5] SPCMD3.SPIMOD, [4] SPCMD3.SPRW, [3:2] SPCMD3.BRDV, [1] SPCMD3.CPOL, [0] SPCMD3.CPHA
0x89E18 QSPI
  [7] SPBFCR.TXRST, [6] SPBFCR.RXRST, [5:4] SPBFCR.TXTRG, [3] SPBFCR.TXTRGEX, [2:0] SPBFCR.RXTRG
0x89E1A QSPI 16-bit
  [13:8] SPBDCR.TXBC, [5:0] SPBDCR.RXBC
{0x8A000+0x20*i} SCI{i} (i=0..9)
  [7] SMR.CM, [6] SMR.CHR, [5] SMR.PE, [4] SMR.PM, [3] SMR.STOP, [2] SMR.MP, [1:0] SMR.CKS
{0x8A000+0x20*i} SMCI{i} (i=0..9)
  [7] SMR.GM, [6] SMR.BLK, [5] SMR.PE, [4] SMR.PM, [3:2] SMR.BCP, [1:0] SMR.CKS
{0x8A002+0x20*i} SCI{i} (i=0..9)
  [7] SCR.TIE, [6] SCR.RIE, [5] SCR.TE, [4] SCR.RE, [3] SCR.MPIE, [2] SCR.TEIE, [1:0] SCR.CKE
{0x8A002+0x20*i} SMCI{i} (i=0..9)
  [7] SCR.TIE, [6] SCR.RIE, [5] SCR.TE, [4] SCR.RE, [3] SCR.MPIE, [2] SCR.TEIE, [1:0] SCR.CKE
{0x8A004+0x20*i} SCI{i} (i=0..9)
  [7] SSR.TDRE, [6] SSR.RDRF, [5] SSR.ORER, [4] SSR.FER, [3] SSR.PER, [2] SSR.TEND, [1] SSR.MPB, [0] SSR.MPBT
{0x8A004+0x20*i} SMCI{i} (i=0..9)
  [7] SSR.TDRE, [6] SSR.RDRF, [5] SSR.ORER, [4] SSR.ERS, [3] SSR.PER, [2] SSR.TEND, [1] SSR.MPB, [0] SSR.MPBT
{0x8A006+0x20*i} SCI{i} (i=0..9)
  [7] SCMR.BCP2, [4] SCMR.CHR1, [3] SCMR.SDIR, [2] SCMR.SINV, [0] SCMR.SMIF
{0x8A006+0x20*i} SMCI{i} (i=0..9)
  [7] SCMR.BCP2, [4] SCMR.CHR1, [3] SCMR.SDIR, [2] SCMR.SINV, [0] SCMR.SMIF
{0x8A007+0x20*i} SCI{i} (i=0..9)
  [7] SEMR.RXDESEL, [6] SEMR.BGDM, [5] SEMR.NFEN, [4] SEMR.ABCS, [2] SEMR.BRME, [0] SEMR.ACS0
{0x8A008+0x20*i} SCI{i} (i=0..9)
  [2:0] SNFR.NFCS
{0x8A009+0x20*i} SCI{i} (i=0..9)
  [7:3] SIMR1.IICDL, [0] SIMR1.IICM
{0x8A00A+0x20*i} SCI{i} (i=0..9)
  [5] SIMR2.IICACKT, [1] SIMR2.IICCSC, [0] SIMR2.IICINTM
{0x8A00B+0x20*i} SCI{i} (i=0..9)
  [7:6] SIMR3.IICSCLS, [5:4] SIMR3.IICSDAS, [3] SIMR3.IICSTIF, [2] SIMR3.IICSTPREQ, [1] SIMR3.IICRSTAREQ, [0] SIMR3.IICSTAREQ
{0x8A00C+0x20*i} SCI{i} (i=0..9)
  [0] SISR.IICACKR
{0x8A00D+0x20*i} SCI{i} (i=0..9)
  [7] SPMR.CKPH, [6] SPMR.CKPOL, [4] SPMR.MFF, [2] SPMR.MSS, [1] SPMR.CTSE, [0] SPMR.SSE
0x8AC00 SDHI 32-bit
  [15:14] SDCMD.CMD12AT, [13] SDCMD.TRSTP, [12] SDCMD.CMDRW, [11] SDCMD.CMDTP, [10:8] SDCMD.RSPTP, [7:6] SDCMD.ACMD, [5:0] SDCMD.CMDIDX
0x8AC10 SDHI 32-bit
  [8] SDSTOP.SDBLKCNTEN, [0] SDSTOP.STP
0x8AC38 SDHI 32-bit
  [10] SDSTS1.SDD3MON, [9] SDSTS1.SDD3IN, [8] SDSTS1.SDD3RM, [7] SDSTS1.SDWPMON, [5] SDSTS1.SDCDMON, [4] SDSTS1.SDCDIN, [3] SDSTS1.SDCDRM, [2] SDSTS1.ACEND, [0] SDSTS1.RSPEND
0x8AC3C SDHI 32-bit
  [15] SDSTS2.ILA, [14] SDSTS2.CBSY, [13] SDSTS2.SDCLKCREN, [9] SDSTS2.BWE, [8] SDSTS2.BRE, [7] SDSTS2.SDD0MON, [6] SDSTS2.RSPTO, [5] SDSTS2.ILR, [4] SDSTS2.ILW, [3] SDSTS2.DTO, [2] SDSTS2.ENDE, [1] SDSTS2.CRCE, [0] SDSTS2.CMDE
0x8AC40 SDHI 32-bit
  [9] SDIMSK1.SDD3INM, [8] SDIMSK1.SDD3RMM, [4] SDIMSK1.SDCDINM, [3] SDIMSK1.SDCDRMM, [2] SDIMSK1.ACENDM, [0] SDIMSK1.RSPENDM
0x8AC44 SDHI 32-bit
  [15] SDIMSK2.ILAM, [9] SDIMSK2.BWEM, [8] SDIMSK2.BREM, [6] SDIMSK2.RSPTOM, [5] SDIMSK2.ILRM, [4] SDIMSK2.ILWM, [3] SDIMSK2.DTTOM, [2] SDIMSK2.ENDEM, [1] SDIMSK2.CRCEM, [0] SDIMSK2.CMDEM
0x8AC48 SDHI 32-bit
  [9] SDCLKCR.CLKCTRLEN, [8] SDCLKCR.CLKEN, [7:0] SDCLKCR.CLKSEL
0x8AC4C SDHI 32-bit
  [9:0] SDSIZE.LEN
0x8AC50 SDHI 32-bit
  [15] SDOPT.WIDTH, [7:4] SDOPT.TOP, [3:0] SDOPT.CTOP
0x8AC58 SDHI 32-bit
  [14:12] SDERSTS1.CRCTK, [11] SDERSTS1.CRCTKE, [10] SDERSTS1.RDCRCE, [9] SDERSTS1.RSPCRCE1, [8] SDERSTS1.RSPCRCE0, [5] SDERSTS1.CRCLENE, [4] SDERSTS1.RDLENE, [3] SDERSTS1.RSPLENE1, [2] SDERSTS1.RSPLENE0, [1] SDERSTS1.CMDE1, [0] SDERSTS1.CMDE0
0x8AC5C SDHI 32-bit
  [6] SDERSTS2.CRCBSYTO, [5] SDERSTS2.CRCTO, [4] SDERSTS2.RDTO, [3] SDERSTS2.BSYTO1, [2] SDERSTS2.BSYTO0, [1] SDERSTS2.RSPTO1, [0] SDERSTS2.RSPTO0
0x8AC68 SDHI 32-bit
  [9] SDIOMD.C52PUB, [8] SDIOMD.IOABT, [2] SDIOMD.RWREQ, [0] SDIOMD.INTEN
0x8AC6C SDHI 32-bit
  [15] SDIOSTS.EXWT, [14] SDIOSTS.EXPUB52, [0] SDIOSTS.IOIRQ
0x8AC70 SDHI 32-bit
  [15] SDIOIMSK.EXWTM, [14] SDIOIMSK.EXPUB52M, [0] SDIOIMSK.IOIRQM
0x8ADB0 SDHI 32-bit
  [1] SDDMAEN.DMAEN
0x8ADC0 SDHI 32-bit
  [0] SDRST.SDRST
0x8ADC4 SDHI 32-bit
  [15] SDVER.CPRM, [14] SDVER.CLKRAT, [11:8] SDVER.IP2, [7:0] SDVER.IP1
0x8ADE0 SDHI 32-bit
  [7] SDSWAP.BRSWP, [6] SDSWAP.BWSWP
0x8B000 CAC
  [0] CACR0.CFME
0x8B001 CAC
  [7:6] CACR1.EDGES, [5:4] CACR1.TCSS, [3:1] CACR1.FMCS, [0] CACR1.CACREFE
0x8B002 CAC
  [7:6] CACR2.DFS, [5:4] CACR2.RCDS, [3:1] CACR2.RSCS, [0] CACR2.RPS
0x8B003 CAC
  [6] CAICR.OVFFCL, [5] CAICR.MENDFCL, [4] CAICR.FERRFCL, [2] CAICR.OVFIE, [1] CAICR.MENDIE, [0] CAICR.FERRIE
0x8B004 CAC
  [2] CASTR.OVFF, [1] CASTR.MENDF, [0] CASTR.FERRF
0x8B080 DOC
  [6] DOCR.DOPCFCL, [5] DOCR.DOPCF, [4] DOCR.DOPCIE, [2] DOCR.DCSEL, [1:0] DOCR.OMS
0x8B100 ELC
  [7] ELCR.ELCON
0x8B101 ELC
  [7:0] ELSR0.ELS
0x8B104 ELC
  [7:0] ELSR3.ELS
0x8B105 ELC
  [7:0] ELSR4.ELS
0x8B108 ELC
  [7:0] ELSR7.ELS
0x8B10B ELC
  [7:0] ELSR10.ELS
0x8B10C ELC
  [7:0] ELSR11.ELS
0x8B10D ELC
  [7:0] ELSR12.ELS
0x8B10E ELC
  [7:0] ELSR13.ELS
0x8B110 ELC
  [7:0] ELSR15.ELS
0x8B111 ELC
  [7:0] ELSR16.ELS
0x8B113 ELC
  [7:0] ELSR18.ELS
0x8B114 ELC
  [7:0] ELSR19.ELS
0x8B115 ELC
  [7:0] ELSR20.ELS
0x8B116 ELC
  [7:0] ELSR21.ELS
0x8B117 ELC
  [7:0] ELSR22.ELS
0x8B118 ELC
  [7:0] ELSR23.ELS
0x8B119 ELC
  [7:0] ELSR24.ELS
0x8B11A ELC
  [7:0] ELSR25.ELS
0x8B11B ELC
  [7:0] ELSR26.ELS
0x8B11C ELC
  [7:0] ELSR27.ELS
0x8B11D ELC
  [7:0] ELSR28.ELS
0x8B11F ELC
  [7:6] ELOPA.MTU3MD, [1:0] ELOPA.MTU0MD
0x8B120 ELC
  [1:0] ELOPB.MTU4MD
0x8B121 ELC
  [3:2] ELOPC.CMT1MD
0x8B122 ELC
  [2n+1:2n] ELOPD.TMR{n}MD (n=0..3)
0x8B123 ELC
  [n] PGR1.PGR{n} (n=0..7)
0x8B124 ELC
  [n] PGR2.PGR{n} (n=0..7)
0x8B125 ELC
  [6:4] PGC1.PGCO, [2] PGC1.PGCOVE, [1:0] PGC1.PGCI
0x8B126 ELC
  [6:4] PGC2.PGCO, [2] PGC2.PGCOVE, [1:0] PGC2.PGCI
0x8B127 ELC
  [n] PDBF1.PDBF{n} (n=0..7)
0x8B128 ELC
  [n] PDBF2.PDBF{n} (n=0..7)
0x8B129 ELC
  [6:5] PEL0.PSM, [4:3] PEL0.PSP, [2:0] PEL0.PSB
0x8B12A ELC
  [6:5] PEL1.PSM, [4:3] PEL1.PSP, [2:0] PEL1.PSB
0x8B12B ELC
  [6:5] PEL2.PSM, [4:3] PEL2.PSP, [2:0] PEL2.PSB
0x8B12C ELC
  [6:5] PEL3.PSM, [4:3] PEL3.PSP, [2:0] PEL3.PSB
0x8B12D ELC
  [7] ELSEGR.WI, [6] ELSEGR.WE, [0] ELSEGR.SEG
0x8B131 ELC
  [7:0] ELSR33.ELS
0x8B133 ELC
  [7:0] ELSR35.ELS
0x8B134 ELC
  [7:0] ELSR36.ELS
0x8B135 ELC
  [7:0] ELSR37.ELS
0x8B136 ELC
  [7:0] ELSR38.ELS
0x8B13D ELC
  [7:0] ELSR45.ELS
0x8B13F ELC
  [2n+1:2n] ELOPF.TPU{n}MD (n=0..3)
0x8B141 ELC
  [1:0] ELOPH.CMTW0MD
0x8B300 SCI12
  fields as SCI0
0x8B300 SMCI12
  fields as SMCI0
0x8B302 SCI12
  [7] SCR.TIE, [6] SCR.RIE, [5] SCR.TE, [4] SCR.RE, [3] SCR.MPIE, [2] SCR.TEIE, [1:0] SCR.CKE
0x8B302 SMCI12
  [7] SCR.TIE, [6] SCR.RIE, [5] SCR.TE, [4] SCR.RE, [3] SCR.MPIE, [2] SCR.TEIE, [1:0] SCR.CKE
0x8B304 SCI12
  [7] SSR.TDRE, [6] SSR.RDRF, [5] SSR.ORER, [4] SSR.FER, [3] SSR.PER, [2] SSR.TEND, [1] SSR.MPB, [0] SSR.MPBT
0x8B304 SMCI12
  [7] SSR.TDRE, [6] SSR.RDRF, [5] SSR.ORER, [4] SSR.ERS, [3] SSR.PER, [2] SSR.TEND, [1] SSR.MPB, [0] SSR.MPBT
0x8B306 SCI12
  [7] SCMR.BCP2, [4] SCMR.CHR1, [3] SCMR.SDIR, [2] SCMR.SINV, [0] SCMR.SMIF
0x8B306 SMCI12
  [7] SCMR.BCP2, [4] SCMR.CHR1, [3] SCMR.SDIR, [2] SCMR.SINV, [0] SCMR.SMIF
0x8B307 SCI12
  [7] SEMR.RXDESEL, [6] SEMR.BGDM, [5] SEMR.NFEN, [4] SEMR.ABCS, [2] SEMR.BRME, [0] SEMR.ACS0
0x8B308 SCI12
  [2:0] SNFR.NFCS
0x8B309 SCI12
  [7:3] SIMR1.IICDL, [0] SIMR1.IICM
0x8B30A SCI12
  [5] SIMR2.IICACKT, [1] SIMR2.IICCSC, [0] SIMR2.IICINTM
0x8B30B SCI12
  [7:6] SIMR3.IICSCLS, [5:4] SIMR3.IICSDAS, [3] SIMR3.IICSTIF, [2] SIMR3.IICSTPREQ, [1] SIMR3.IICRSTAREQ, [0] SIMR3.IICSTAREQ
0x8B30C SCI12
  [0] SISR.IICACKR
0x8B30D SCI12
  [7] SPMR.CKPH, [6] SPMR.CKPOL, [4] SPMR.MFF, [2] SPMR.MSS, [1] SPMR.CTSE, [0] SPMR.SSE
0x8B320 SCI12
  [0] ESMER.ESME
0x8B321 SCI12
  [3] CR0.BRME, [2] CR0.RXDSF, [1] CR0.SFSF
0x8B322 SCI12
  [7:5] CR1.PIBS, [4] CR1.PIBE, [3:2] CR1.CF1DS, [1] CR1.CF0RE, [0] CR1.BFE
0x8B323 SCI12
  [7:6] CR2.RTS, [5:4] CR2.BCCS, [2:0] CR2.DFCS
0x8B324 SCI12
  [0] CR3.SDST
0x8B325 SCI12
  [4] PCR.SHARPS, [1] PCR.RXDXPS, [0] PCR.TXDXPS
0x8B326 SCI12
  [5] ICR.AEDIE, [4] ICR.BCDIE, [3] ICR.PIBDIE, [2] ICR.CF1MIE, [1] ICR.CF0MIE, [0] ICR.BFDIE
0x8B327 SCI12
  [5] STR.AEDF, [4] STR.BCDF, [3] STR.PIBDF, [2] STR.CF1MF, [1] STR.CF0MF, [0] STR.BFDF
0x8B328 SCI12
  [5] STCR.AEDCL, [4] STCR.BCDCL, [3] STCR.PIBDCL, [2] STCR.CF1MCL, [1] STCR.CF0MCL, [0] STCR.BFDCL
0x8B32A SCI12
  [n] CF0CR.CF0CE{n} (n=0..7)
0x8B32E SCI12
  [n] CF1CR.CF1CE{n} (n=0..7)
0x8B330 SCI12
  [0] TCR.TCST
0x8B331 SCI12
  [6:4] TMR.TCSS, [3] TMR.TWRC, [1:0] TMR.TOMS
0x8C000 PORT0
  [7] PDR.B7, [5] PDR.B5, [n] PDR.B{n} (n=0..3)
0x8C001 PORT1
  [n] PDR.B{n} (n=0..7)
0x8C002 PORT2
  [n] PDR.B{n} (n=0..7)
0x8C003 PORT3
  [7] PDR.B7, [6] PDR.B6, [n] PDR.B{n} (n=0..4)
{0x8C000+i} PORT{i} (i=4..9)
  [n] PDR.B{n} (n=0..7)
0x8C00A PORTA
  [n] PDR.B{n} (n=0..7)
0x8C00B PORTB
  [n] PDR.B{n} (n=0..7)
0x8C00C PORTC
  [n] PDR.B{n} (n=0..7)
0x8C00D PORTD
  [n] PDR.B{n} (n=0..7)
0x8C00E PORTE
  [n] PDR.B{n} (n=0..7)
0x8C00F PORTF
  [n] PDR.B{n} (n=0..5)
0x8C010 PORTG
  [n] PDR.B{n} (n=0..7)
0x8C012 PORTJ
  [5] PDR.B5, [n] PDR.B{n} (n=0..3)
0x8C020 PORT0
  [7] PODR.B7, [5] PODR.B5, [n] PODR.B{n} (n=0..3)
0x8C021 PORT1
  [n] PODR.B{n} (n=0..7)
0x8C022 PORT2
  [n] PODR.B{n} (n=0..7)
0x8C023 PORT3
  [7] PODR.B7, [6] PODR.B6, [n] PODR.B{n} (n=0..4)
{0x8C020+i} PORT{i} (i=4..9)
  [n] PODR.B{n} (n=0..7)
0x8C02A PORTA
  [n] PODR.B{n} (n=0..7)
0x8C02B PORTB
  [n] PODR.B{n} (n=0..7)
0x8C02C PORTC
  [n] PODR.B{n} (n=0..7)
0x8C02D PORTD
  [n] PODR.B{n} (n=0..7)
0x8C02E PORTE
  [n] PODR.B{n} (n=0..7)
0x8C02F PORTF
  [n] PODR.B{n} (n=0..5)
0x8C030 PORTG
  [n] PODR.B{n} (n=0..7)
0x8C032 PORTJ
  [5] PODR.B5, [n] PODR.B{n} (n=0..3)
0x8C040 PORT0
  [7] PIDR.B7, [5] PIDR.B5, [n] PIDR.B{n} (n=0..3)
{0x8C040+i} PORT{i} (i=1..9)
  [n] PIDR.B{n} (n=0..7)
0x8C04A PORTA
  [n] PIDR.B{n} (n=0..7)
0x8C04B PORTB
  [n] PIDR.B{n} (n=0..7)
0x8C04C PORTC
  [n] PIDR.B{n} (n=0..7)
0x8C04D PORTD
  [n] PIDR.B{n} (n=0..7)
0x8C04E PORTE
  [n] PIDR.B{n} (n=0..7)
0x8C04F PORTF
  [n] PIDR.B{n} (n=0..5)
0x8C050 PORTG
  [n] PIDR.B{n} (n=0..7)
0x8C052 PORTJ
  [5] PIDR.B5, [n] PIDR.B{n} (n=0..3)
0x8C060 PORT0
  [7] PMR.B7, [5] PMR.B5, [n] PMR.B{n} (n=0..3)
0x8C061 PORT1
  [n] PMR.B{n} (n=0..7)
0x8C062 PORT2
  [n] PMR.B{n} (n=0..7)
0x8C063 PORT3
  [7] PMR.B7, [6] PMR.B6, [n] PMR.B{n} (n=0..4)
{0x8C060+i} PORT{i} (i=4..9)
  [n] PMR.B{n} (n=0..7)
0x8C06A PORTA
  [n] PMR.B{n} (n=0..7)
0x8C06B PORTB
  [n] PMR.B{n} (n=0..7)
0x8C06C PORTC
  [n] PMR.B{n} (n=0..7)
0x8C06D PORTD
  [n] PMR.B{n} (n=0..7)
0x8C06E PORTE
  [n] PMR.B{n} (n=0..7)
0x8C06F PORTF
  [n] PMR.B{n} (n=0..5)
0x8C070 PORTG
  [n] PMR.B{n} (n=0..7)
0x8C072 PORTJ
  [5] PMR.B5, [n] PMR.B{n} (n=0..3)
0x8C080 PORT0
  [6] ODR0.B6, [4] ODR0.B4, [2] ODR0.B2, [0] ODR0.B0
0x8C081 PORT0
  [6] ODR1.B6, [2] ODR1.B2
0x8C082 PORT1
  [6] ODR0.B6, [4] ODR0.B4, [2] ODR0.B2, [0] ODR0.B0
0x8C083 PORT1
  [6] ODR1.B6, [4] ODR1.B4, [2] ODR1.B2, [0] ODR1.B0
0x8C084 PORT2
  [6] ODR0.B6, [4] ODR0.B4, [2] ODR0.B2, [0] ODR0.B0
0x8C085 PORT2
  [6] ODR1.B6, [4] ODR1.B4, [2] ODR1.B2, [0] ODR1.B0
0x8C086 PORT3
  [6] ODR0.B6, [4] ODR0.B4, [2] ODR0.B2, [0] ODR0.B0
0x8C087 PORT3
  [6] ODR1.B6, [4] ODR1.B4, [0] ODR1.B0
0x8C088 PORT4
  [6] ODR0.B6, [4] ODR0.B4, [2] ODR0.B2, [0] ODR0.B0
0x8C089 PORT4
  [6] ODR1.B6, [4] ODR1.B4, [2] ODR1.B2, [0] ODR1.B0
0x8C08A PORT5
  [6] ODR0.B6, [4] ODR0.B4, [2] ODR0.B2, [0] ODR0.B0
0x8C08B PORT5
  [6] ODR1.B6, [4] ODR1.B4, [2] ODR1.B2, [0] ODR1.B0
# iorx65n register map
Registers are 8-bit, access not given, no defined reset value unless marked. A register's access mark holds for its fields unless they carry their own. Addresses are absolute; registers are grouped by the start of their names; [hi:lo] are bit positions; {n}, {i} and the like mark numbered series; 'fields as' and 'values as' point back to an identical list.

## SFR (part 4 of 7)
0x91835 CAN1
  [7] MCTL[21]_TX.TRMREQ, [7] MCTL[21]_RX.TRMREQ, [6] MCTL[21]_TX.RECREQ, [6] MCTL[21]_RX.RECREQ, [4] MCTL[21]_TX.ONESHOT, [4] MCTL[21]_RX.ONESHOT, [2] MCTL[21]_TX.TRMABT, [2] MCTL[21]_RX.MSGLOST, [1] MCTL[21]_TX.TRMACTIVE, [1] MCTL[21]_RX.INVALDATA, [0] MCTL[21]_TX.SENTDATA, [0] MCTL[21]_RX.NEWDATA
0x91836 CAN1
  [7] MCTL[22]_TX.TRMREQ, [7] MCTL[22]_RX.TRMREQ, [6] MCTL[22]_TX.RECREQ, [6] MCTL[22]_RX.RECREQ, [4] MCTL[22]_TX.ONESHOT, [4] MCTL[22]_RX.ONESHOT, [2] MCTL[22]_TX.TRMABT, [2] MCTL[22]_RX.MSGLOST, [1] MCTL[22]_TX.TRMACTIVE, [1] MCTL[22]_RX.INVALDATA, [0] MCTL[22]_TX.SENTDATA, [0] MCTL[22]_RX.NEWDATA
0x91837 CAN1
  [7] MCTL[23]_TX.TRMREQ, [7] MCTL[23]_RX.TRMREQ, [6] MCTL[23]_TX.RECREQ, [6] MCTL[23]_RX.RECREQ, [4] MCTL[23]_TX.ONESHOT, [4] MCTL[23]_RX.ONESHOT, [2] MCTL[23]_TX.TRMABT, [2] MCTL[23]_RX.MSGLOST, [1] MCTL[23]_TX.TRMACTIVE, [1] MCTL[23]_RX.INVALDATA, [0] MCTL[23]_TX.SENTDATA, [0] MCTL[23]_RX.NEWDATA
0x91838 CAN1
  [7] MCTL[24]_TX.TRMREQ, [7] MCTL[24]_RX.TRMREQ, [6] MCTL[24]_TX.RECREQ, [6] MCTL[24]_RX.RECREQ, [4] MCTL[24]_TX.ONESHOT, [4] MCTL[24]_RX.ONESHOT, [2] MCTL[24]_TX.TRMABT, [2] MCTL[24]_RX.MSGLOST, [1] MCTL[24]_TX.TRMACTIVE, [1] MCTL[24]_RX.INVALDATA, [0] MCTL[24]_TX.SENTDATA, [0] MCTL[24]_RX.NEWDATA
0x91839 CAN1
  [7] MCTL[25]_TX.TRMREQ, [7] MCTL[25]_RX.TRMREQ, [6] MCTL[25]_TX.RECREQ, [6] MCTL[25]_RX.RECREQ, [4] MCTL[25]_TX.ONESHOT, [4] MCTL[25]_RX.ONESHOT, [2] MCTL[25]_TX.TRMABT, [2] MCTL[25]_RX.MSGLOST, [1] MCTL[25]_TX.TRMACTIVE, [1] MCTL[25]_RX.INVALDATA, [0] MCTL[25]_TX.SENTDATA, [0] MCTL[25]_RX.NEWDATA
0x9183A CAN1
  [7] MCTL[26]_TX.TRMREQ, [7] MCTL[26]_RX.TRMREQ, [6] MCTL[26]_TX.RECREQ, [6] MCTL[26]_RX.RECREQ, [4] MCTL[26]_TX.ONESHOT, [4] MCTL[26]_RX.ONESHOT, [2] MCTL[26]_TX.TRMABT, [2] MCTL[26]_RX.MSGLOST, [1] MCTL[26]_TX.TRMACTIVE, [1] MCTL[26]_RX.INVALDATA, [0] MCTL[26]_TX.SENTDATA, [0] MCTL[26]_RX.NEWDATA
0x9183B CAN1
  [7] MCTL[27]_TX.TRMREQ, [7] MCTL[27]_RX.TRMREQ, [6] MCTL[27]_TX.RECREQ, [6] MCTL[27]_RX.RECREQ, [4] MCTL[27]_TX.ONESHOT, [4] MCTL[27]_RX.ONESHOT, [2] MCTL[27]_TX.TRMABT, [2] MCTL[27]_RX.MSGLOST, [1] MCTL[27]_TX.TRMACTIVE, [1] MCTL[27]_RX.INVALDATA, [0] MCTL[27]_TX.SENTDATA, [0] MCTL[27]_RX.NEWDATA
0x9183C CAN1
  [7] MCTL[28]_TX.TRMREQ, [7] MCTL[28]_RX.TRMREQ, [6] MCTL[28]_TX.RECREQ, [6] MCTL[28]_RX.RECREQ, [4] MCTL[28]_TX.ONESHOT, [4] MCTL[28]_RX.ONESHOT, [2] MCTL[28]_TX.TRMABT, [2] MCTL[28]_RX.MSGLOST, [1] MCTL[28]_TX.TRMACTIVE, [1] MCTL[28]_RX.INVALDATA, [0] MCTL[28]_TX.SENTDATA, [0] MCTL[28]_RX.NEWDATA
0x9183D CAN1
  [7] MCTL[29]_TX.TRMREQ, [7] MCTL[29]_RX.TRMREQ, [6] MCTL[29]_TX.RECREQ, [6] MCTL[29]_RX.RECREQ, [4] MCTL[29]_TX.ONESHOT, [4] MCTL[29]_RX.ONESHOT, [2] MCTL[29]_TX.TRMABT, [2] MCTL[29]_RX.MSGLOST, [1] MCTL[29]_TX.TRMACTIVE, [1] MCTL[29]_RX.INVALDATA, [0] MCTL[29]_TX.SENTDATA, [0] MCTL[29]_RX.NEWDATA
0x9183E CAN1
  [7] MCTL[30]_TX.TRMREQ, [7] MCTL[30]_RX.TRMREQ, [6] MCTL[30]_TX.RECREQ, [6] MCTL[30]_RX.RECREQ, [4] MCTL[30]_TX.ONESHOT, [4] MCTL[30]_RX.ONESHOT, [2] MCTL[30]_TX.TRMABT, [2] MCTL[30]_RX.MSGLOST, [1] MCTL[30]_TX.TRMACTIVE, [1] MCTL[30]_RX.INVALDATA, [0] MCTL[30]_TX.SENTDATA, [0] MCTL[30]_RX.NEWDATA
0x9183F CAN1
  [7] MCTL[31]_TX.TRMREQ, [7] MCTL[31]_RX.TRMREQ, [6] MCTL[31]_TX.RECREQ, [6] MCTL[31]_RX.RECREQ, [4] MCTL[31]_TX.ONESHOT, [4] MCTL[31]_RX.ONESHOT, [2] MCTL[31]_TX.TRMABT, [2] MCTL[31]_RX.MSGLOST, [1] MCTL[31]_TX.TRMACTIVE, [1] MCTL[31]_RX.INVALDATA, [0] MCTL[31]_TX.SENTDATA, [0] MCTL[31]_RX.NEWDATA
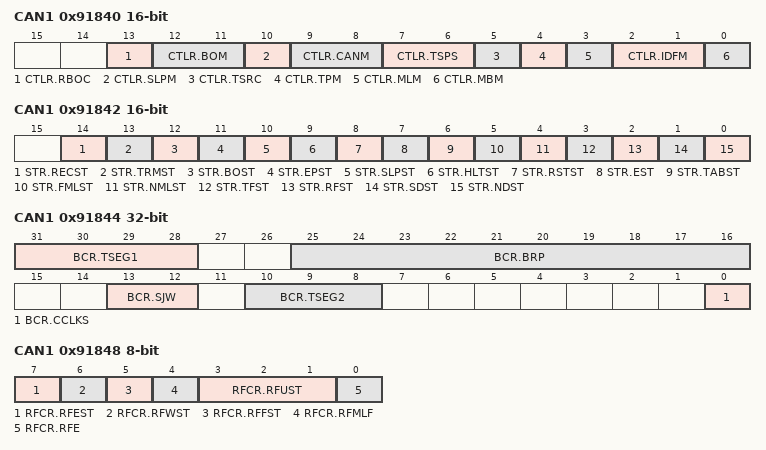
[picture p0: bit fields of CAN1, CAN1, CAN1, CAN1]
0x91840 CAN1 16-bit
  [13] CTLR.RBOC, [12:11] CTLR.BOM, [10] CTLR.SLPM, [9:8] CTLR.CANM, [7:6] CTLR.TSPS, [5] CTLR.TSRC, [4] CTLR.TPM, [3] CTLR.MLM, [2:1] CTLR.IDFM, [0] CTLR.MBM
0x91842 CAN1 16-bit
  [14] STR.RECST, [13] STR.TRMST, [12] STR.BOST, [11] STR.EPST, [10] STR.SLPST, [9] STR.HLTST, [8] STR.RSTST, [7] STR.EST, [6] STR.TABST, [5] STR.FMLST, [4] STR.NMLST, [3] STR.TFST, [2] STR.RFST, [1] STR.SDST, [0] STR.NDST
0x91844 CAN1 32-bit
  [31:28] BCR.TSEG1, [25:16] BCR.BRP, [13:12] BCR.SJW, [10:8] BCR.TSEG2, [0] BCR.CCLKS
0x91848 CAN1
  [7] RFCR.RFEST, [6] RFCR.RFWST, [5] RFCR.RFFST, [4] RFCR.RFMLF, [3:1] RFCR.RFUST, [0] RFCR.RFE
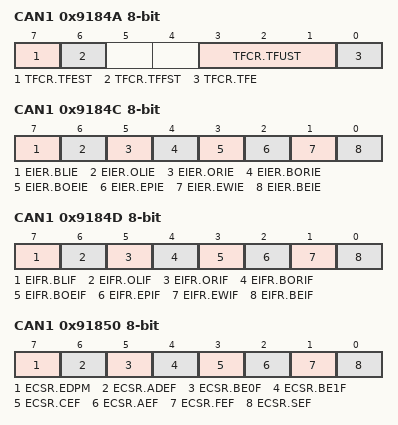
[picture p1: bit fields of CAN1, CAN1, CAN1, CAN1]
0x9184A CAN1
  [7] TFCR.TFEST, [6] TFCR.TFFST, [3:1] TFCR.TFUST, [0] TFCR.TFE
0x9184C CAN1
  [7] EIER.BLIE, [6] EIER.OLIE, [5] EIER.ORIE, [4] EIER.BORIE, [3] EIER.BOEIE, [2] EIER.EPIE, [1] EIER.EWIE, [0] EIER.BEIE
0x9184D CAN1
  [7] EIFR.BLIF, [6] EIFR.OLIF, [5] EIFR.ORIF, [4] EIFR.BORIF, [3] EIFR.BOEIF, [2] EIFR.EPIF, [1] EIFR.EWIF, [0] EIFR.BEIF
0x91850 CAN1
  [7] ECSR.EDPM, [6] ECSR.ADEF, [5] ECSR.BE0F, [4] ECSR.BE1F, [3] ECSR.CEF, [2] ECSR.AEF, [1] ECSR.FEF, [0] ECSR.SEF
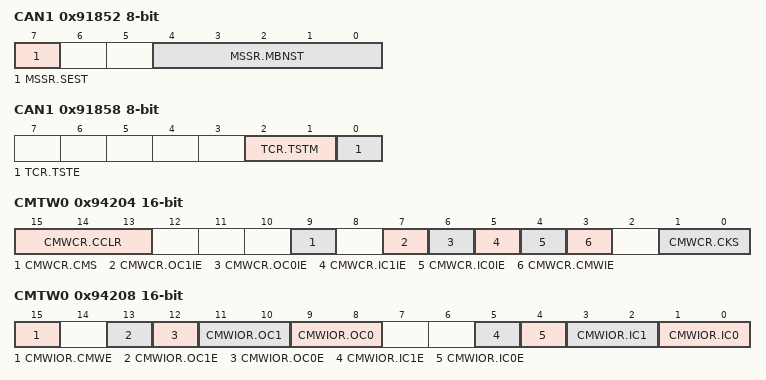
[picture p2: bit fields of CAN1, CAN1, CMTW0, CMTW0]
0x91852 CAN1
  [7] MSSR.SEST, [4:0] MSSR.MBNST
0x91853 CAN1
  [1:0] MSMR.MBSM
0x91858 CAN1
  [2:1] TCR.TSTM, [0] TCR.TSTE
0x94200 CMTW0 16-bit
  [0] CMWSTR.STR
0x94204 CMTW0 16-bit
  [15:13] CMWCR.CCLR, [9] CMWCR.CMS, [7] CMWCR.OC1IE, [6] CMWCR.OC0IE, [5] CMWCR.IC1IE, [4] CMWCR.IC0IE, [3] CMWCR.CMWIE, [1:0] CMWCR.CKS
0x94208 CMTW0 16-bit
  [15] CMWIOR.CMWE, [13] CMWIOR.OC1E, [12] CMWIOR.OC0E, [11:10] CMWIOR.OC1, [9:8] CMWIOR.OC0, [5] CMWIOR.IC1E, [4] CMWIOR.IC0E, [3:2] CMWIOR.IC1, [1:0] CMWIOR.IC0
0x94280 CMTW1 16-bit
  [0] CMWSTR.STR
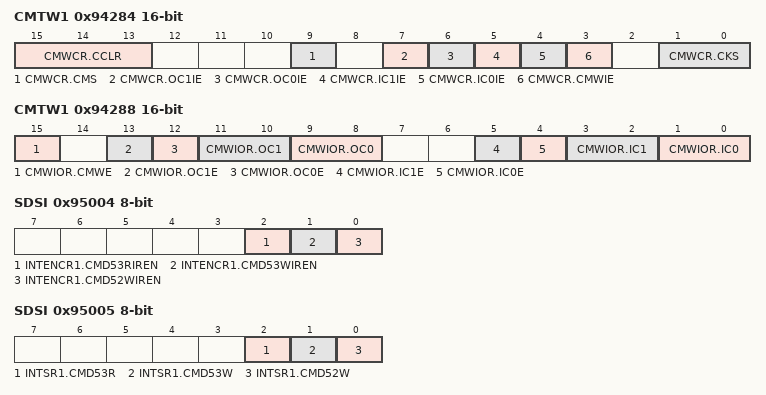
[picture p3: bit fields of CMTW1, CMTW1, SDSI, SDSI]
0x94284 CMTW1 16-bit
  [15:13] CMWCR.CCLR, [9] CMWCR.CMS, [7] CMWCR.OC1IE, [6] CMWCR.OC0IE, [5] CMWCR.IC1IE, [4] CMWCR.IC0IE, [3] CMWCR.CMWIE, [1:0] CMWCR.CKS
0x94288 CMTW1 16-bit
  [15] CMWIOR.CMWE, [13] CMWIOR.OC1E, [12] CMWIOR.OC0E, [11:10] CMWIOR.OC1, [9:8] CMWIOR.OC0, [5] CMWIOR.IC1E, [4] CMWIOR.IC0E, [3:2] CMWIOR.IC1, [1:0] CMWIOR.IC0
0x95000 SDSI 32-bit
  [11] FN1ACCR.FN1ACC
0x95004 SDSI
  [2] INTENCR1.CMD53RIREN, [1] INTENCR1.CMD53WIREN, [0] INTENCR1.CMD52WIREN
0x95005 SDSI
  [2] INTSR1.CMD53R, [1] INTSR1.CMD53W, [0] INTSR1.CMD52W
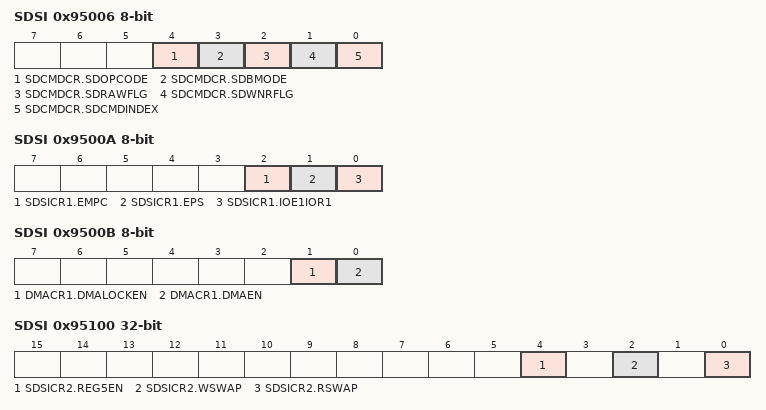
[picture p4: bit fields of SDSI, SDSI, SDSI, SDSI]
0x95006 SDSI
  [4] SDCMDCR.SDOPCODE, [3] SDCMDCR.SDBMODE, [2] SDCMDCR.SDRAWFLG, [1] SDCMDCR.SDWNRFLG, [0] SDCMDCR.SDCMDINDEX
0x95007 SDSI
  [7:0] SDCADD0R.SDCMDACCADD
0x95008 SDSI
  [7:0] SDCADD1R.SDCMDACCADD
0x95009 SDSI
  [0] SDCADD2R.SDCMDACCADD
0x9500A SDSI
  [2] SDSICR1.EMPC, [1] SDSICR1.EPS, [0] SDSICR1.IOE1IOR1
0x9500B SDSI
  [1] DMACR1.DMALOCKEN, [0] DMACR1.DMAEN
0x9500C SDSI 16-bit
  [8:0] BLKCNT.CMD53BLK
0x9500E SDSI 16-bit
  [11:0] BYTCNT.CMD53BYT
0x95010 SDSI 32-bit
  [31:0] DMATRADDR.DMAADD
0x95100 SDSI 32-bit
  [4] SDSICR2.REG5EN, [2] SDSICR2.WSWAP, [0] SDSICR2.RSWAP
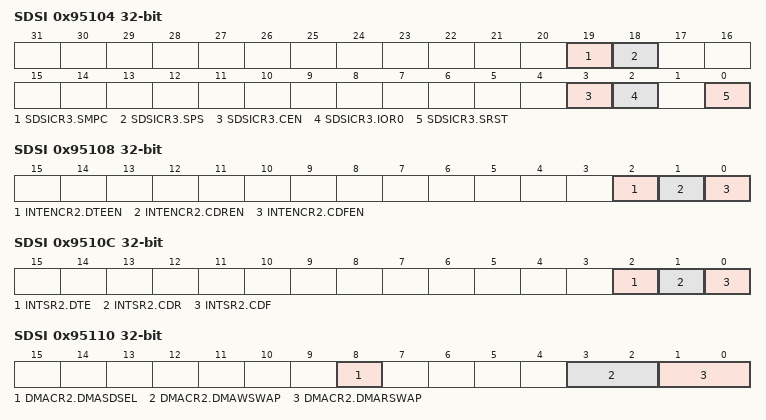
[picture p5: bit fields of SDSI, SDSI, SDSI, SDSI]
0x95104 SDSI 32-bit
  [19] SDSICR3.SMPC, [18] SDSICR3.SPS, [3] SDSICR3.CEN, [2] SDSICR3.IOR0, [0] SDSICR3.SRST
0x95108 SDSI 32-bit
  [2] INTENCR2.DTEEN, [1] INTENCR2.CDREN, [0] INTENCR2.CDFEN
0x9510C SDSI 32-bit
  [2] INTSR2.DTE, [1] INTSR2.CDR, [0] INTSR2.CDF
0x95110 SDSI 32-bit
  [8] DMACR2.DMASDSEL, [3:2] DMACR2.DMAWSWAP, [1:0] DMACR2.DMARSWAP
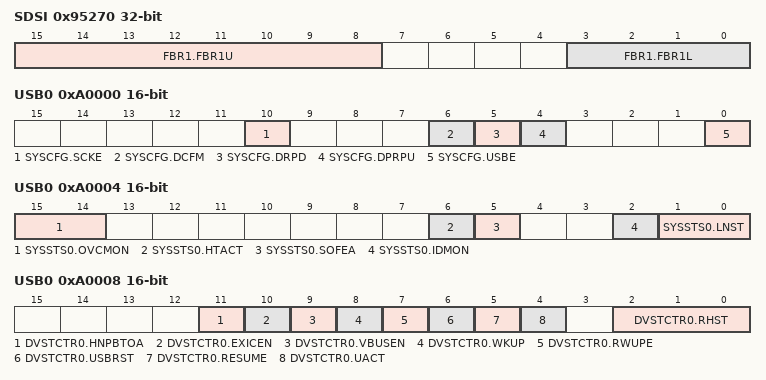
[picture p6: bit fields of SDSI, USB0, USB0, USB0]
0x95270 SDSI 32-bit
  [15:8] FBR1.FBR1U, [3:0] FBR1.FBR1L
0x95274 SDSI 32-bit
  [7:0] FBR2.FBR2
0x95278 SDSI 32-bit
  [15:0] FBR3.FBR3
0x9527C SDSI 32-bit
  [15:0] FBR4.FBR4
0x95280 SDSI 32-bit
  [7:0] FBR5.FBR5
0x95B00 SDSI
  [7:0] FN1INTVECR.INTVEC
0x95B01 SDSI
  [7:0] FN1INTCLRR.INTCTR
0xA0000 USB0 16-bit
  [10] SYSCFG.SCKE, [6] SYSCFG.DCFM, [5] SYSCFG.DRPD, [4] SYSCFG.DPRPU, [0] SYSCFG.USBE
0xA0004 USB0 16-bit
  [15:14] SYSSTS0.OVCMON, [6] SYSSTS0.HTACT, [5] SYSSTS0.SOFEA, [2] SYSSTS0.IDMON, [1:0] SYSSTS0.LNST
0xA0008 USB0 16-bit
  [11] DVSTCTR0.HNPBTOA, [10] DVSTCTR0.EXICEN, [9] DVSTCTR0.VBUSEN, [8] DVSTCTR0.WKUP, [7] DVSTCTR0.RWUPE, [6] DVSTCTR0.USBRST, [5] DVSTCTR0.RESUME, [4] DVSTCTR0.UACT, [2:0] DVSTCTR0.RHST
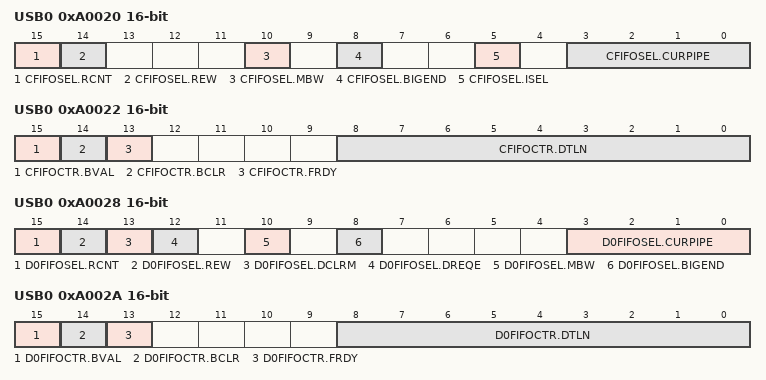
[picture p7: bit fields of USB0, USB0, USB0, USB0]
0xA0020 USB0 16-bit
  [15] CFIFOSEL.RCNT, [14] CFIFOSEL.REW, [10] CFIFOSEL.MBW, [8] CFIFOSEL.BIGEND, [5] CFIFOSEL.ISEL, [3:0] CFIFOSEL.CURPIPE
0xA0022 USB0 16-bit
  [15] CFIFOCTR.BVAL, [14] CFIFOCTR.BCLR, [13] CFIFOCTR.FRDY, [8:0] CFIFOCTR.DTLN
0xA0028 USB0 16-bit
  [15] D0FIFOSEL.RCNT, [14] D0FIFOSEL.REW, [13] D0FIFOSEL.DCLRM, [12] D0FIFOSEL.DREQE, [10] D0FIFOSEL.MBW, [8] D0FIFOSEL.BIGEND, [3:0] D0FIFOSEL.CURPIPE
0xA002A USB0 16-bit
  [15] D0FIFOCTR.BVAL, [14] D0FIFOCTR.BCLR, [13] D0FIFOCTR.FRDY, [8:0] D0FIFOCTR.DTLN
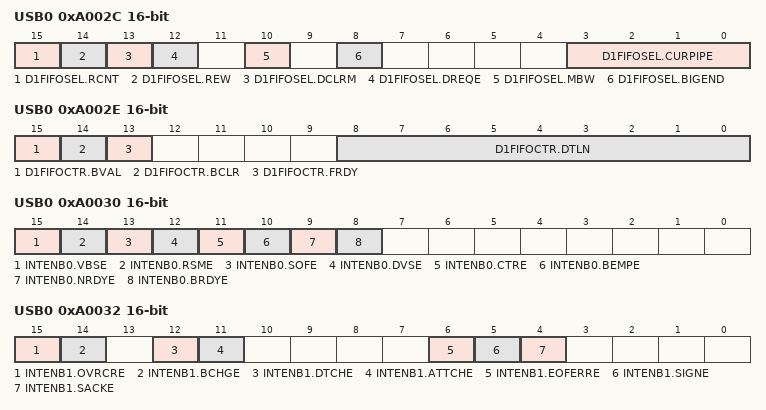
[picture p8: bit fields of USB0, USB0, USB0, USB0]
0xA002C USB0 16-bit
  [15] D1FIFOSEL.RCNT, [14] D1FIFOSEL.REW, [13] D1FIFOSEL.DCLRM, [12] D1FIFOSEL.DREQE, [10] D1FIFOSEL.MBW, [8] D1FIFOSEL.BIGEND, [3:0] D1FIFOSEL.CURPIPE
0xA002E USB0 16-bit
  [15] D1FIFOCTR.BVAL, [14] D1FIFOCTR.BCLR, [13] D1FIFOCTR.FRDY, [8:0] D1FIFOCTR.DTLN
0xA0030 USB0 16-bit
  [15] INTENB0.VBSE, [14] INTENB0.RSME, [13] INTENB0.SOFE, [12] INTENB0.DVSE, [11] INTENB0.CTRE, [10] INTENB0.BEMPE, [9] INTENB0.NRDYE, [8] INTENB0.BRDYE
0xA0032 USB0 16-bit
  [15] INTENB1.OVRCRE, [14] INTENB1.BCHGE, [12] INTENB1.DTCHE, [11] INTENB1.ATTCHE, [6] INTENB1.EOFERRE, [5] INTENB1.SIGNE, [4] INTENB1.SACKE
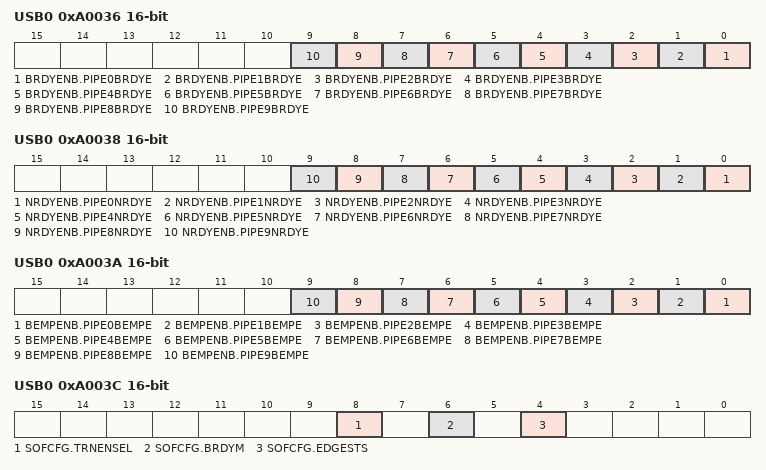
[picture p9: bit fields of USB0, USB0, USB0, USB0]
0xA0036 USB0 16-bit
  [n] BRDYENB.PIPE{n}BRDYE (n=0..9)
0xA0038 USB0 16-bit
  [n] NRDYENB.PIPE{n}NRDYE (n=0..9)
0xA003A USB0 16-bit
  [n] BEMPENB.PIPE{n}BEMPE (n=0..9)
0xA003C USB0 16-bit
  [8] SOFCFG.TRNENSEL, [6] SOFCFG.BRDYM, [4] SOFCFG.EDGESTS
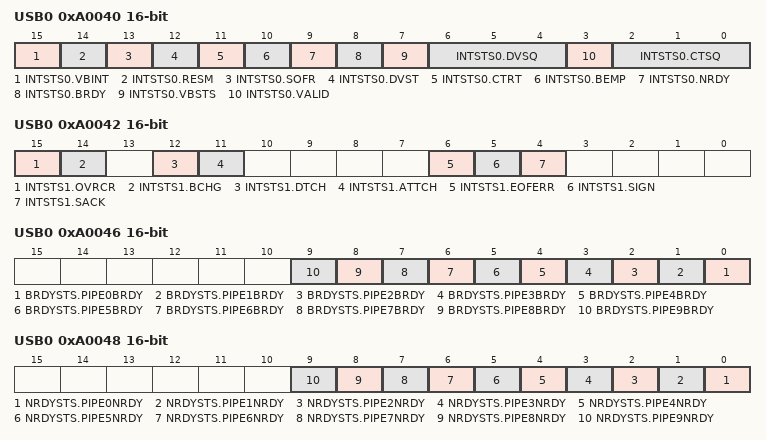
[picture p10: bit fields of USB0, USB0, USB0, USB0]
0xA0040 USB0 16-bit
  [15] INTSTS0.VBINT, [14] INTSTS0.RESM, [13] INTSTS0.SOFR, [12] INTSTS0.DVST, [11] INTSTS0.CTRT, [10] INTSTS0.BEMP, [9] INTSTS0.NRDY, [8] INTSTS0.BRDY, [7] INTSTS0.VBSTS, [6:4] INTSTS0.DVSQ, [3] INTSTS0.VALID, [2:0] INTSTS0.CTSQ
0xA0042 USB0 16-bit
  [15] INTSTS1.OVRCR, [14] INTSTS1.BCHG, [12] INTSTS1.DTCH, [11] INTSTS1.ATTCH, [6] INTSTS1.EOFERR, [5] INTSTS1.SIGN, [4] INTSTS1.SACK
0xA0046 USB0 16-bit
  [n] BRDYSTS.PIPE{n}BRDY (n=0..9)
0xA0048 USB0 16-bit
  [n] NRDYSTS.PIPE{n}NRDY (n=0..9)
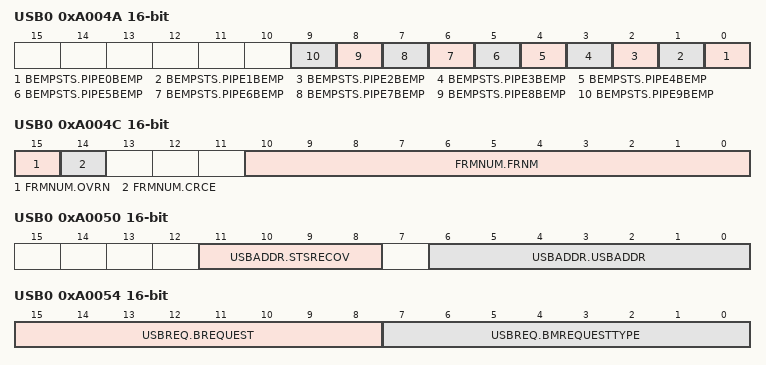
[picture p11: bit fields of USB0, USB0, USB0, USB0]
0xA004A USB0 16-bit
  [n] BEMPSTS.PIPE{n}BEMP (n=0..9)
0xA004C USB0 16-bit
  [15] FRMNUM.OVRN, [14] FRMNUM.CRCE, [10:0] FRMNUM.FRNM
0xA004E USB0 16-bit
  [15] DVCHGR.DVCHG
0xA0050 USB0 16-bit
  [11:8] USBADDR.STSRECOV, [6:0] USBADDR.USBADDR
0xA0054 USB0 16-bit
  [15:8] USBREQ.BREQUEST, [7:0] USBREQ.BMREQUESTTYPE
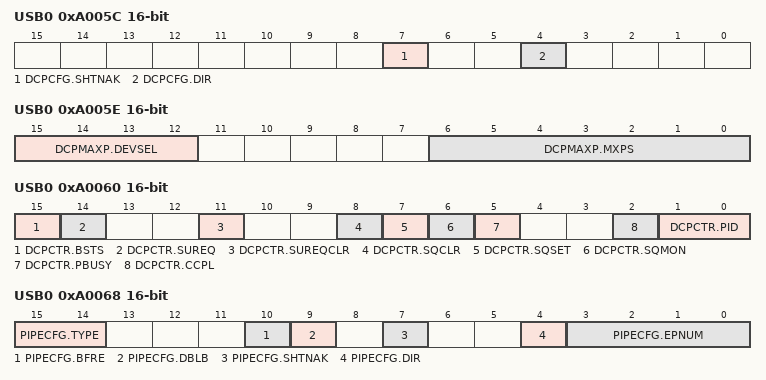
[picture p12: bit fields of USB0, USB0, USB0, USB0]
0xA005C USB0 16-bit
  [7] DCPCFG.SHTNAK, [4] DCPCFG.DIR
0xA005E USB0 16-bit
  [15:12] DCPMAXP.DEVSEL, [6:0] DCPMAXP.MXPS
0xA0060 USB0 16-bit
  [15] DCPCTR.BSTS, [14] DCPCTR.SUREQ, [11] DCPCTR.SUREQCLR, [8] DCPCTR.SQCLR, [7] DCPCTR.SQSET, [6] DCPCTR.SQMON, [5] DCPCTR.PBUSY, [2] DCPCTR.CCPL, [1:0] DCPCTR.PID
0xA0064 USB0 16-bit
  [3:0] PIPESEL.PIPESEL
0xA0068 USB0 16-bit
  [15:14] PIPECFG.TYPE, [10] PIPECFG.BFRE, [9] PIPECFG.DBLB, [7] PIPECFG.SHTNAK, [4] PIPECFG.DIR, [3:0] PIPECFG.EPNUM
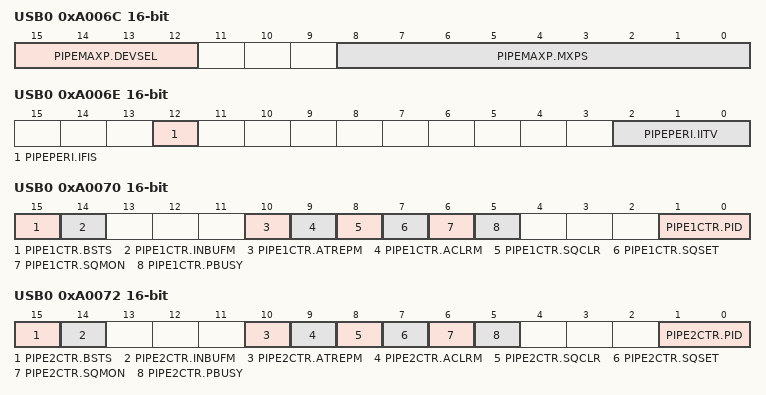
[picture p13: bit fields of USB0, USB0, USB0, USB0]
0xA006C USB0 16-bit
  [15:12] PIPEMAXP.DEVSEL, [8:0] PIPEMAXP.MXPS
0xA006E USB0 16-bit
  [12] PIPEPERI.IFIS, [2:0] PIPEPERI.IITV
0xA0070 USB0 16-bit
  [15] PIPE1CTR.BSTS, [14] PIPE1CTR.INBUFM, [10] PIPE1CTR.ATREPM, [9] PIPE1CTR.ACLRM, [8] PIPE1CTR.SQCLR, [7] PIPE1CTR.SQSET, [6] PIPE1CTR.SQMON, [5] PIPE1CTR.PBUSY, [1:0] PIPE1CTR.PID
0xA0072 USB0 16-bit
  [15] PIPE2CTR.BSTS, [14] PIPE2CTR.INBUFM, [10] PIPE2CTR.ATREPM, [9] PIPE2CTR.ACLRM, [8] PIPE2CTR.SQCLR, [7] PIPE2CTR.SQSET, [6] PIPE2CTR.SQMON, [5] PIPE2CTR.PBUSY, [1:0] PIPE2CTR.PID
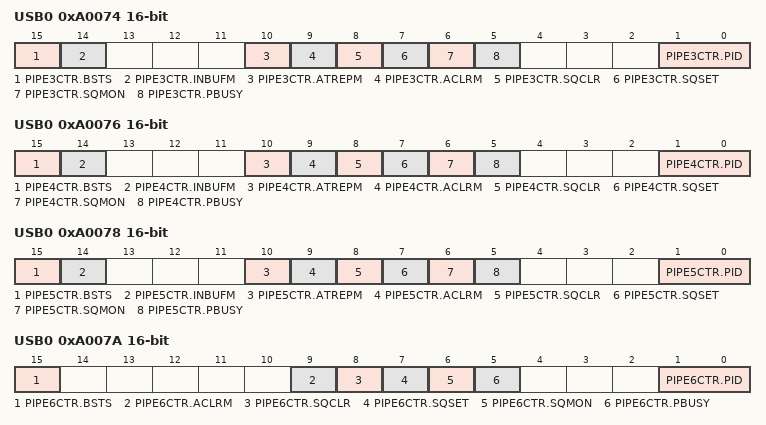
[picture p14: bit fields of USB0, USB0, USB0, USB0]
0xA0074 USB0 16-bit
  [15] PIPE3CTR.BSTS, [14] PIPE3CTR.INBUFM, [10] PIPE3CTR.ATREPM, [9] PIPE3CTR.ACLRM, [8] PIPE3CTR.SQCLR, [7] PIPE3CTR.SQSET, [6] PIPE3CTR.SQMON, [5] PIPE3CTR.PBUSY, [1:0] PIPE3CTR.PID
0xA0076 USB0 16-bit
  [15] PIPE4CTR.BSTS, [14] PIPE4CTR.INBUFM, [10] PIPE4CTR.ATREPM, [9] PIPE4CTR.ACLRM, [8] PIPE4CTR.SQCLR, [7] PIPE4CTR.SQSET, [6] PIPE4CTR.SQMON, [5] PIPE4CTR.PBUSY, [1:0] PIPE4CTR.PID
0xA0078 USB0 16-bit
  [15] PIPE5CTR.BSTS, [14] PIPE5CTR.INBUFM, [10] PIPE5CTR.ATREPM, [9] PIPE5CTR.ACLRM, [8] PIPE5CTR.SQCLR, [7] PIPE5CTR.SQSET, [6] PIPE5CTR.SQMON, [5] PIPE5CTR.PBUSY, [1:0] PIPE5CTR.PID
0xA007A USB0 16-bit
  [15] PIPE6CTR.BSTS, [9] PIPE6CTR.ACLRM, [8] PIPE6CTR.SQCLR, [7] PIPE6CTR.SQSET, [6] PIPE6CTR.SQMON, [5] PIPE6CTR.PBUSY, [1:0] PIPE6CTR.PID
0xA007C USB0 16-bit
  [15] PIPE7CTR.BSTS, [9] PIPE7CTR.ACLRM, [8] PIPE7CTR.SQCLR, [7] PIPE7CTR.SQSET, [6] PIPE7CTR.SQMON, [5] PIPE7CTR.PBUSY, [1:0] PIPE7CTR.PID
0xA007E USB0 16-bit
  [15] PIPE8CTR.BSTS, [9] PIPE8CTR.ACLRM, [8] PIPE8CTR.SQCLR, [7] PIPE8CTR.SQSET, [6] PIPE8CTR.SQMON, [5] PIPE8CTR.PBUSY, [1:0] PIPE8CTR.PID
0xA0080 USB0 16-bit
  [15] PIPE9CTR.BSTS, [9] PIPE9CTR.ACLRM, [8] PIPE9CTR.SQCLR, [7] PIPE9CTR.SQSET, [6] PIPE9CTR.SQMON, [5] PIPE9CTR.PBUSY, [1:0] PIPE9CTR.PID
0xA0090 USB0 16-bit
  [9] PIPE1TRE.TRENB, [8] PIPE1TRE.TRCLR
0xA0094 USB0 16-bit
  [9] PIPE2TRE.TRENB, [8] PIPE2TRE.TRCLR
0xA0098 USB0 16-bit
  [9] PIPE3TRE.TRENB, [8] PIPE3TRE.TRCLR
0xA009C USB0 16-bit
  [9] PIPE4TRE.TRENB, [8] PIPE4TRE.TRCLR
0xA00A0 USB0 16-bit
  [9] PIPE5TRE.TRENB, [8] PIPE5TRE.TRCLR
0xA00D0 USB0 16-bit
  [7:6] DEVADD0.USBSPD
0xA00D2 USB0 16-bit
  [7:6] DEVADD1.USBSPD
0xA00D4 USB0 16-bit
  [7:6] DEVADD2.USBSPD
0xA00D6 USB0 16-bit
  [7:6] DEVADD3.USBSPD
0xA00D8 USB0 16-bit
  [7:6] DEVADD4.USBSPD
0xA00DA USB0 16-bit
  [7:6] DEVADD5.USBSPD
0xA00F0 USB0 32-bit
  [3] PHYSLEW.SLEWF01, [2] PHYSLEW.SLEWF00, [1] PHYSLEW.SLEWR01, [0] PHYSLEW.SLEWR00
0xA0400 USB 32-bit
  [23] DPUSR0R.DVBSTS0, [21] DPUSR0R.DOVCB0, [20] DPUSR0R.DOVCA0, [17] DPUSR0R.DM0, [16] DPUSR0R.DP0, [4] DPUSR0R.FIXPHY0, [3] DPUSR0R.DRPD0, [1] DPUSR0R.RPUE0, [0] DPUSR0R.SRPC0
0xA0404 USB 32-bit
  [23] DPUSR1R.DVBINT0, [21] DPUSR1R.DOVRCRB0, [20] DPUSR1R.DOVRCRA0, [17] DPUSR1R.DMINT0, [16] DPUSR1R.DPINT0, [7] DPUSR1R.DVBSE0, [5] DPUSR1R.DOVRCRBE0, [4] DPUSR1R.DOVRCRAE0, [1] DPUSR1R.DMINTE0, [0] DPUSR1R.DPINTE0
0xA0500 PDC 32-bit
  [14] PCCR0.EDS, [13:11] PCCR0.PCKDIV, [10] PCCR0.PCKOE, [9] PCCR0.HERIE, [8] PCCR0.VERIE, [7] PCCR0.UDRIE, [6] PCCR0.OVIE, [5] PCCR0.FEIE, [4] PCCR0.DFIE, [3] PCCR0.PRST, [2] PCCR0.HPS, [1] PCCR0.VPS, [0] PCCR0.PCKE
0xA0504 PDC 32-bit
  [0] PCCR1.PCE
0xA0508 PDC 32-bit
  [6] PCSR.HERF, [5] PCSR.VERF, [4] PCSR.UDRF, [3] PCSR.OVRF, [2] PCSR.FEF, [1] PCSR.FEMPF, [0] PCSR.FBSY
0xA050C PDC 32-bit
  [1] PCMONR.HSYNC, [0] PCMONR.VSYNC
0xA0514 PDC 32-bit
  [27:16] VCR.VSZ, [11:0] VCR.VST
0xA0518 PDC 32-bit
  [27:16] HCR.HSZ, [11:0] HCR.HST
0xC0000 EDMAC0 32-bit
  [6] EDMR.DE, [5:4] EDMR.DL, [0] EDMR.SWR
0xC0008 EDMAC0 32-bit
  [0] EDTRR.TR
0xC0010 EDMAC0 32-bit
  [0] EDRRR.RR
0xC0028 EDMAC0 32-bit
  [30] EESR.TWB, [26] EESR.TABT, [25] EESR.RABT, [24] EESR.RFCOF, [22] EESR.ECI, [21] EESR.TC, [20] EESR.TDE, [19] EESR.TFUF, [18] EESR.FR, [17] EESR.RDE, [16] EESR.RFOF, [11] EESR.CND, [10] EESR.DLC, [9] EESR.CD, [8] EESR.TRO, [7] EESR.RMAF, [4] EESR.RRF, [3] EESR.RTLF, [2] EESR.RTSF, [1] EESR.PRE, [0] EESR.CERF
0xC0030 EDMAC0 32-bit
  [30] EESIPR.TWBIP, [26] EESIPR.TABTIP, [25] EESIPR.RABTIP, [24] EESIPR.RFCOFIP, [22] EESIPR.ECIIP, [21] EESIPR.TCIP, [20] EESIPR.TDEIP, [19] EESIPR.TFUFIP, [18] EESIPR.FRIP, [17] EESIPR.RDEIP, [16] EESIPR.RFOFIP, [11] EESIPR.CNDIP, [10] EESIPR.DLCIP, [9] EESIPR.CDIP, [8] EESIPR.TROIP, [7] EESIPR.RMAFIP, [4] EESIPR.RRFIP, [3] EESIPR.RTLFIP, [2] EESIPR.RTSFIP, [1] EESIPR.PREIP, [0] EESIPR.CERFIP
0xC0038 EDMAC0 32-bit
  [7] TRSCER.RMAFCE, [4] TRSCER.RRFCE
0xC0040 EDMAC0 32-bit
  [15:0] RMFCR.MFC
0xC0048 EDMAC0 32-bit
  [10:0] TFTR.TFT
0xC0050 EDMAC0 32-bit
  [12:8] FDR.TFD, [4:0] FDR.RFD
0xC0058 EDMAC0 32-bit
  [0] RMCR.RNR
0xC0064 EDMAC0 32-bit
  [15:0] TFUCR.UNDER
0xC0068 EDMAC0 32-bit
  [15:0] RFOCR.OVER
0xC006C EDMAC0 32-bit
  [0] IOSR.ELB
0xC0070 EDMAC0 32-bit
  [18:16] FCFTR.RFFO, [2:0] FCFTR.RFDO
0xC0078 EDMAC0 32-bit
  [17:16] RPADIR.PADS, [5:0] RPADIR.PADR
0xC007C EDMAC0 32-bit
  [4] TRIMD.TIM, [0] TRIMD.TIS
0xC0100 ETHERC0 32-bit
  [20] ECMR.TPC, [19] ECMR.ZPF, [18] ECMR.PFR, [17] ECMR.RXF, [16] ECMR.TXF, [12] ECMR.PRCEF, [9] ECMR.MPDE, [6] ECMR.RE, [5] ECMR.TE, [3] ECMR.ILB, [2] ECMR.RTM, [1] ECMR.DM, [0] ECMR.PRM
0xC0108 ETHERC0 32-bit
  [11:0] RFLR.RFL
0xC0110 ETHERC0 32-bit
  [5] ECSR.BFR, [4] ECSR.PSRTO, [2] ECSR.LCHNG, [1] ECSR.MPD, [0] ECSR.ICD
0xC0118 ETHERC0 32-bit
  [5] ECSIPR.BFSIPR, [4] ECSIPR.PSRTOIP, [2] ECSIPR.LCHNGIP, [1] ECSIPR.MPDIP, [0] ECSIPR.ICDIP
0xC0120 ETHERC0 32-bit
  [3] PIR.MDI, [2] PIR.MDO, [1] PIR.MMD, [0] PIR.MDC
0xC0128 ETHERC0 32-bit
  [0] PSR.LMON
0xC0140 ETHERC0 32-bit
  [19:0] RDMLR.RMD
0xC0150 ETHERC0 32-bit
  [4:0] IPGR.IPG
0xC0154 ETHERC0 32-bit
  [15:0] APR.AP
0xC0158 ETHERC0 32-bit
  [15:0] MPR.MP
0xC0160 ETHERC0 32-bit
  [7:0] RFCF.RPAUSE
0xC0164 ETHERC0 32-bit
  [15:0] TPAUSER.TPAUSE
0xC0168 ETHERC0 32-bit
  [7:0] TPAUSECR.TXP
0xC016C ETHERC0 32-bit
  [15:0] BCFRR.BCF
0xC01C8 ETHERC0 32-bit
  [15:0] MALR.MA
0xC1200 MTU3
  [7:5] TCR.CCLR, [4:3] TCR.CKEG, [2:0] TCR.TPSC
0xC1201 MTU4
  [7:5] TCR.CCLR, [4:3] TCR.CKEG, [2:0] TCR.TPSC
0xC1202 MTU3
  [5] TMDR1.BFB, [4] TMDR1.BFA, [3:0] TMDR1.MD
0xC1203 MTU4
  [5] TMDR1.BFB, [4] TMDR1.BFA, [3:0] TMDR1.MD
0xC1204 MTU3
  [7:4] TIORH.IOB, [3:0] TIORH.IOA
0xC1205 MTU3
  [7:4] TIORL.IOD, [3:0] TIORL.IOC
0xC1206 MTU4
  [7:4] TIORH.IOB, [3:0] TIORH.IOA
0xC1207 MTU4
  [7:4] TIORL.IOD, [3:0] TIORL.IOC
0xC1208 MTU3
  [7] TIER.TTGE, [4] TIER.TCIEV, [3] TIER.TGIED, [2] TIER.TGIEC, [1] TIER.TGIEB, [0] TIER.TGIEA
0xC1209 MTU4
  [7] TIER.TTGE, [6] TIER.TTGE2, [4] TIER.TCIEV, [3] TIER.TGIED, [2] TIER.TGIEC, [1] TIER.TGIEB, [0] TIER.TGIEA
0xC120A MTU
  [5] TOERA.OE4D, [4] TOERA.OE4C, [3] TOERA.OE3D, [2] TOERA.OE4B, [1] TOERA.OE4A, [0] TOERA.OE3B
0xC120D MTU
  [6] TGCRA.BDC, [5] TGCRA.N, [4] TGCRA.P, [3] TGCRA.FB, [2] TGCRA.WF, [1] TGCRA.VF, [0] TGCRA.UF
0xC120E MTU
  [6] TOCR1A.PSYE, [3] TOCR1A.TOCL, [2] TOCR1A.TOCS, [1] TOCR1A.OLSN, [0] TOCR1A.OLSP
0xC120F MTU
  [7:6] TOCR2A.BF, [5] TOCR2A.OLS3N, [4] TOCR2A.OLS3P, [3] TOCR2A.OLS2N, [2] TOCR2A.OLS2P, [1] TOCR2A.OLS1N, [0] TOCR2A.OLS1P
0xC122C MTU3
  [7] TSR.TCFD
0xC122D MTU4
  [7] TSR.TCFD
0xC1230 MTU
  [7] TITCR1A.T3AEN, [6:4] TITCR1A.T3ACOR, [3] TITCR1A.T4VEN, [2:0] TITCR1A.T4VCOR
0xC1231 MTU
  [6:4] TITCNT1A.T3ACNT, [2:0] TITCNT1A.T4VCNT
0xC1232 MTU
  [1:0] TBTERA.BTE
0xC1234 MTU
  [0] TDERA.TDER
0xC1236 MTU
  [5] TOLBRA.OLS3N, [4] TOLBRA.OLS3P, [3] TOLBRA.OLS2N, [2] TOLBRA.OLS2P, [1] TOLBRA.OLS1N, [0] TOLBRA.OLS1P
0xC1238 MTU3
  [1] TBTM.TTSB, [0] TBTM.TTSA
0xC1239 MTU4
  [1] TBTM.TTSB, [0] TBTM.TTSA
0xC123A MTU
  [0] TITMRA.TITM
0xC123B MTU
  [2:0] TITCR2A.TRG4COR
0xC123C MTU
  [2:0] TITCNT2A.TRG4CNT
0xC1240 MTU4 16-bit
  [15:14] TADCR.BF, [7] TADCR.UT4AE, [6] TADCR.DT4AE, [5] TADCR.UT4BE, [4] TADCR.DT4BE, [3] TADCR.ITA3AE, [2] TADCR.ITA4VE, [1] TADCR.ITB3AE, [0] TADCR.ITB4VE
0xC124C MTU3
  [2:0] TCR2.TPSC2
0xC124D MTU4
  [2:0] TCR2.TPSC2
0xC1260 MTU
  [7] TWCRA.CCE, [1] TWCRA.SCC, [0] TWCRA.WRE
0xC1270 MTU
  [0] TMDR2A.DRS
0xC1280 MTU
  [7] TSTRA.CST4, [6] TSTRA.CST3, [3] TSTRA.CST8, [2] TSTRA.CST2, [1] TSTRA.CST1, [0] TSTRA.CST0
0xC1281 MTU
  [7] TSYRA.SYNC4, [6] TSYRA.SYNC3, [2] TSYRA.SYNC2, [1] TSYRA.SYNC1, [0] TSYRA.SYNC0
0xC1282 MTU
  [7-n] TCSYSTR.SCH{n} (n=0..4), [1] TCSYSTR.SCH6, [0] TCSYSTR.SCH7
0xC1284 MTU
  [0] TRWERA.RWE
{0xC1290+i} MTU{i} (i=0..4)
  [5:4] NFCR{i}.NFCS, [3] NFCR{i}.NFDEN, [2] NFCR{i}.NFCEN, [1] NFCR{i}.NFBEN, [0] NFCR{i}.NFAEN
0xC1298 MTU8
  [5:4] NFCR8.NFCS, [3] NFCR8.NFDEN, [2] NFCR8.NFCEN, [1] NFCR8.NFBEN, [0] NFCR8.NFAEN
0xC1299 MTU0
  [5:4] NFCRC.NFCS, [3] NFCRC.NFDEN, [2] NFCRC.NFCEN, [1] NFCRC.NFBEN, [0] NFCRC.NFAEN
0xC1300 MTU0
  [7:5] TCR.CCLR, [4:3] TCR.CKEG, [2:0] TCR.TPSC
0xC1301 MTU0
  [6] TMDR1.BFE, [5] TMDR1.BFB, [4] TMDR1.BFA, [3:0] TMDR1.MD
0xC1302 MTU0
  [7:4] TIORH.IOB, [3:0] TIORH.IOA
0xC1303 MTU0
  [7:4] TIORL.IOD, [3:0] TIORL.IOC
0xC1304 MTU0
  [7] TIER.TTGE, [4] TIER.TCIEV, [3] TIER.TGIED, [2] TIER.TGIEC, [1] TIER.TGIEB, [0] TIER.TGIEA
0xC1324 MTU0
  [7] TIER2.TTGE2, [1] TIER2.TGIEF, [0] TIER2.TGIEE
0xC1326 MTU0
  [2] TBTM.TTSE, [1] TBTM.TTSB, [0] TBTM.TTSA
0xC1328 MTU0
  [2:0] TCR2.TPSC2
0xC1380 MTU1
  [6:5] TCR.CCLR, [4:3] TCR.CKEG, [2:0] TCR.TPSC
0xC1381 MTU1
  [3:0] TMDR1.MD
0xC1382 MTU1
  [7:4] TIOR.IOB, [3:0] TIOR.IOA
0xC1384 MTU1
  [7] TIER.TTGE, [5] TIER.TCIEU, [4] TIER.TCIEV, [1] TIER.TGIEB, [0] TIER.TGIEA
0xC1385 MTU1
  [7] TSR.TCFD
0xC1390 MTU1
  [3] TICCR.I2BE, [2] TICCR.I2AE, [1] TICCR.I1BE, [0] TICCR.I1AE
0xC1391 MTU1
  [1] TMDR3.PHCKSEL, [0] TMDR3.LWA
0xC1394 MTU1
  [4:3] TCR2.PCB, [2:0] TCR2.TPSC2
0xC1400 MTU2
  [6:5] TCR.CCLR, [4:3] TCR.CKEG, [2:0] TCR.TPSC
0xC1401 MTU2
  [3:0] TMDR1.MD
0xC1402 MTU2
  [7:4] TIOR.IOB, [3:0] TIOR.IOA
0xC1404 MTU2
  [7] TIER.TTGE, [5] TIER.TCIEU, [4] TIER.TCIEV, [1] TIER.TGIEB, [0] TIER.TGIEA
0xC1405 MTU2
  [7] TSR.TCFD
0xC140C MTU2
  [4:3] TCR2.PCB, [2:0] TCR2.TPSC2
0xC1600 MTU8
  [7:5] TCR.CCLR, [4:3] TCR.CKEG, [2:0] TCR.TPSC
0xC1601 MTU8
  [5] TMDR1.BFB, [4] TMDR1.BFA, [3:0] TMDR1.MD
0xC1602 MTU8
  [7:4] TIORH.IOB, [3:0] TIORH.IOA
0xC1603 MTU8
  [7:4] TIORL.IOD, [3:0] TIORL.IOC
0xC1604 MTU8
  [4] TIER.TCIEV, [3] TIER.TGIED, [2] TIER.TGIEC, [1] TIER.TGIEB, [0] TIER.TGIEA
0xC1606 MTU8
  [2:0] TCR2.TPSC2
0xC1A00 MTU6
  [7:5] TCR.CCLR, [4:3] TCR.CKEG, [2:0] TCR.TPSC
0xC1A01 MTU7
  [7:5] TCR.CCLR, [4:3] TCR.CKEG, [2:0] TCR.TPSC
0xC1A02 MTU6
  [5] TMDR1.BFB, [4] TMDR1.BFA, [3:0] TMDR1.MD
0xC1A03 MTU7
  [5] TMDR1.BFB, [4] TMDR1.BFA, [3:0] TMDR1.MD
0xC1A04 MTU6
  [7:4] TIORH.IOB, [3:0] TIORH.IOA
0xC1A05 MTU6
  [7:4] TIORL.IOD, [3:0] TIORL.IOC
0xC1A06 MTU7
  [7:4] TIORH.IOB, [3:0] TIORH.IOA
0xC1A07 MTU7
  [7:4] TIORL.IOD, [3:0] TIORL.IOC
0xC1A08 MTU6
  [7] TIER.TTGE, [4] TIER.TCIEV, [3] TIER.TGIED, [2] TIER.TGIEC, [1] TIER.TGIEB, [0] TIER.TGIEA
0xC1A09 MTU7
  [7] TIER.TTGE, [6] TIER.TTGE2, [4] TIER.TCIEV, [3] TIER.TGIED, [2] TIER.TGIEC, [1] TIER.TGIEB, [0] TIER.TGIEA
0xC1A0A MTU
  [5] TOERB.OE7D, [4] TOERB.OE7C, [3] TOERB.OE6D, [2] TOERB.OE7B, [1] TOERB.OE7A, [0] TOERB.OE6B
0xC1A0E MTU
  [6] TOCR1B.PSYE, [3] TOCR1B.TOCL, [2] TOCR1B.TOCS, [1] TOCR1B.OLSN, [0] TOCR1B.OLSP
0xC1A0F MTU
  [7:6] TOCR2B.BF, [5] TOCR2B.OLS3N, [4] TOCR2B.OLS3P, [3] TOCR2B.OLS2N, [2] TOCR2B.OLS2P, [1] TOCR2B.OLS1N, [0] TOCR2B.OLS1P
0xC1A2C MTU6
  [7] TSR.TCFD
0xC1A2D MTU7
  [7] TSR.TCFD
0xC1A30 MTU
  [7] TITCR1B.T6AEN, [6:4] TITCR1B.T6ACOR, [3] TITCR1B.T7VEN, [2:0] TITCR1B.T7VCOR
0xC1A31 MTU
  [6:4] TITCNT1B.T6ACNT, [2:0] TITCNT1B.T7VCNT
0xC1A32 MTU
  [1:0] TBTERB.BTE
0xC1A34 MTU
  [0] TDERB.TDER
0xC1A36 MTU
  [5] TOLBRB.OLS3N, [4] TOLBRB.OLS3P, [3] TOLBRB.OLS2N, [2] TOLBRB.OLS2P, [1] TOLBRB.OLS1N, [0] TOLBRB.OLS1P
0xC1A38 MTU6
  [1] TBTM.TTSB, [0] TBTM.TTSA
0xC1A39 MTU7
  [1] TBTM.TTSB, [0] TBTM.TTSA
0xC1A3A MTU
  [0] TITMRB.TITM
0xC1A3B MTU
  [2:0] TITCR2B.TRG7COR
0xC1A3C MTU
  [2:0] TITCNT2B.TRG7CNT
0xC1A40 MTU7 16-bit
  [15:14] TADCR.BF, [7] TADCR.UT7AE, [6] TADCR.DT7AE, [5] TADCR.UT7BE, [4] TADCR.DT7BE, [3] TADCR.ITA6AE, [2] TADCR.ITA7VE, [1] TADCR.ITB6AE, [0] TADCR.ITB7VE
0xC1A4C MTU6
  [2:0] TCR2.TPSC2
0xC1A4D MTU7
  [2:0] TCR2.TPSC2
0xC1A50 MTU6
  [7] TSYCR.CE0A, [6] TSYCR.CE0B, [5] TSYCR.CE0C, [4] TSYCR.CE0D, [3] TSYCR.CE1A, [2] TSYCR.CE1B, [1] TSYCR.CE2A, [0] TSYCR.CE2B
0xC1A60 MTU
  [7] TWCRB.CCE, [1] TWCRB.SCC, [0] TWCRB.WRE
0xC1A70 MTU
  [0] TMDR2B.DRS
0xC1A80 MTU
  [7] TSTRB.CST7, [6] TSTRB.CST6
0xC1A81 MTU
  [7] TSYRB.SYNC7, [6] TSYRB.SYNC6
0xC1A84 MTU
  [0] TRWERB.RWE
0xC1A93 MTU6
  [5:4] NFCR6.NFCS, [3] NFCR6.NFDEN, [2] NFCR6.NFCEN, [1] NFCR6.NFBEN, [0] NFCR6.NFAEN
0xC1A94 MTU7
  [5:4] NFCR7.NFCS, [3] NFCR7.NFDEN, [2] NFCR7.NFCEN, [1] NFCR7.NFBEN, [0] NFCR7.NFAEN
0xC1A95 MTU5
  [5:4] NFCR5.NFCS, [2] NFCR5.NFWEN, [1] NFCR5.NFVEN, [0] NFCR5.NFUEN
0xC1C84 MTU5
  [1:0] TCRU.TPSC
0xC1C85 MTU5
  [4:3] TCR2U.CKEG, [2:0] TCR2U.TPSC2
0xC1C86 MTU5
  [4:0] TIORU.IOC
0xC1C94 MTU5
  [1:0] TCRV.TPSC
0xC1C95 MTU5
  [4:3] TCR2V.CKEG, [2:0] TCR2V.TPSC2
0xC1C96 MTU5
  [4:0] TIORV.IOC
0xC1CA4 MTU5
  [1:0] TCRW.TPSC
0xC1CA5 MTU5
  [4:3] TCR2W.CKEG, [2:0] TCR2W.TPSC2
0xC1CA6 MTU5
  [4:0] TIORW.IOC
0xC1CB2 MTU5
  [2] TIER.TGIE5U, [1] TIER.TGIE5V, [0] TIER.TGIE5W
0xC1CB4 MTU5
  [2] TSTR.CSTU5, [1] TSTR.CSTV5, [0] TSTR.CSTW5
0xC1CB6 MTU5
  [2] TCNTCMPCLR.CMPCLR5U, [1] TCNTCMPCLR.CMPCLR5V, [0] TCNTCMPCLR.CMPCLR5W
0xC5800 BSC 32-bit
  [31] EBMAPCR.PRERR, [29] EBMAPCR.RPSTOP, [4n-2:4n-4] EBMAPCR.PR{n}SEL (n=1..5)
0xD0040 SCI10
  [7] SMR.CM, [6] SMR.CHR, [5] SMR.PE, [4] SMR.PM, [3] SMR.STOP, [2] SMR.MP, [1:0] SMR.CKS
0xD0040 SMCI10
  [7] SMR.GM, [6] SMR.BLK, [5] SMR.PE, [4] SMR.PM, [3:2] SMR.BCP, [1:0] SMR.CKS
0xD0042 SCI10
  [7] SCR.TIE, [6] SCR.RIE, [5] SCR.TE, [4] SCR.RE, [3] SCR.MPIE, [2] SCR.TEIE, [1:0] SCR.CKE
0xD0042 SMCI10
  [7] SCR.TIE, [6] SCR.RIE, [5] SCR.TE, [4] SCR.RE, [3] SCR.MPIE, [2] SCR.TEIE, [1:0] SCR.CKE
0xD0044 SCI10
  [7] SSR.TDRE, [7] SSRFIFO.TDFE, [6] SSR.RDRF, [6] SSRFIFO.RDF, [5] SSR.ORER, [5] SSRFIFO.ORER, [4] SSR.FER, [4] SSRFIFO.FER, [3] SSR.PER, [3] SSRFIFO.PER, [2] SSR.TEND, [2] SSRFIFO.TEND, [1] SSR.MPB, [0] SSR.MPBT, [0] SSRFIFO.DR
0xD0044 SMCI10
  [7] SSR.TDRE, [6] SSR.RDRF, [5] SSR.ORER, [4] SSR.ERS, [3] SSR.PER, [2] SSR.TEND, [1] SSR.MPB, [0] SSR.MPBT
0xD0046 SCI10
  [7] SCMR.BCP2, [4] SCMR.CHR1, [3] SCMR.SDIR, [2] SCMR.SINV, [0] SCMR.SMIF
0xD0046 SMCI10
  [7] SCMR.BCP2, [4] SCMR.CHR1, [3] SCMR.SDIR, [2] SCMR.SINV, [0] SCMR.SMIF
0xD0047 SCI10
  [7] SEMR.RXDESEL, [6] SEMR.BGDM, [5] SEMR.NFEN, [4] SEMR.ABCS, [2] SEMR.BRME, [0] SEMR.ACS0
0xD0048 SCI10
  [2:0] SNFR.NFCS
0xD0049 SCI10
  [7:3] SIMR1.IICDL, [0] SIMR1.IICM
0xD004A SCI10
  [5] SIMR2.IICACKT, [1] SIMR2.IICCSC, [0] SIMR2.IICINTM
0xD004B SCI10
  [7:6] SIMR3.IICSCLS, [5:4] SIMR3.IICSDAS, [3] SIMR3.IICSTIF, [2] SIMR3.IICSTPREQ, [1] SIMR3.IICRSTAREQ, [0] SIMR3.IICSTAREQ
0xD004C SCI10
  [0] SISR.IICACKR
0xD004D SCI10
  [7] SPMR.CKPH, [6] SPMR.CKPOL, [4] SPMR.MFF, [2] SPMR.MSS, [1] SPMR.CTSE, [0] SPMR.SSE
0xD004E SCI10 16-bit
  [9] FTDR.MPBT, [8:0] FTDR.TDAT
0xD0050 SCI10 16-bit
  [14] FRDR.RDF, [13] FRDR.ORER, [12] FRDR.FER, [11] FRDR.PER, [10] FRDR.DR, [9] FRDR.MPB, [8:0] FRDR.RDAT
0xD0053 SCI10
  [7] DCCR.DCME, [6] DCCR.IDSEL, [4] DCCR.DFER, [3] DCCR.DPER, [0] DCCR.DCMF
0xD0054 SCI10 16-bit
  [15:12] FCR.RSTRG, [11:8] FCR.RTRG, [7:4] FCR.TTRG, [3] FCR.DRES, [2] FCR.TFRST, [1] FCR.RFRST, [0] FCR.FM
0xD0056 SCI10 16-bit
  [12:8] FDR.T, [4:0] FDR.R
0xD0058 SCI10 16-bit
  [12:8] LSR.PNUM, [6:2] LSR.FNUM, [0] LSR.ORER
0xD005A SCI10 16-bit
  [8:0] CDR.CMPD
0xD005C SCI10
  [2] SPTR.SPB2IO, [1] SPTR.SPB2DT, [0] SPTR.RXDMON
0xD0060 SCI11
  fields as SCI10
0xD0060 SMCI11
  fields as SMCI10
0xD0062 SCI11
  [7] SCR.TIE, [6] SCR.RIE, [5] SCR.TE, [4] SCR.RE, [3] SCR.MPIE, [2] SCR.TEIE, [1:0] SCR.CKE
0xD0062 SMCI11
  [7] SCR.TIE, [6] SCR.RIE, [5] SCR.TE, [4] SCR.RE, [3] SCR.MPIE, [2] SCR.TEIE, [1:0] SCR.CKE
0xD0064 SCI11
  [7] SSR.TDRE, [7] SSRFIFO.TDFE, [6] SSR.RDRF, [6] SSRFIFO.RDF, [5] SSR.ORER, [5] SSRFIFO.ORER, [4] SSR.FER, [4] SSRFIFO.FER, [3] SSR.PER, [3] SSRFIFO.PER, [2] SSR.TEND, [2] SSRFIFO.TEND, [1] SSR.MPB, [0] SSR.MPBT, [0] SSRFIFO.DR
0xD0064 SMCI11
  [7] SSR.TDRE, [6] SSR.RDRF, [5] SSR.ORER, [4] SSR.ERS, [3] SSR.PER, [2] SSR.TEND, [1] SSR.MPB, [0] SSR.MPBT
0xD0066 SCI11
  [7] SCMR.BCP2, [4] SCMR.CHR1, [3] SCMR.SDIR, [2] SCMR.SINV, [0] SCMR.SMIF
0xD0066 SMCI11
  [7] SCMR.BCP2, [4] SCMR.CHR1, [3] SCMR.SDIR, [2] SCMR.SINV, [0] SCMR.SMIF
0xD0067 SCI11
  [7] SEMR.RXDESEL, [6] SEMR.BGDM, [5] SEMR.NFEN, [4] SEMR.ABCS, [2] SEMR.BRME, [0] SEMR.ACS0
0xD0068 SCI11
  [2:0] SNFR.NFCS
0xD0069 SCI11
  [7:3] SIMR1.IICDL, [0] SIMR1.IICM
0xD006A SCI11
  [5] SIMR2.IICACKT, [1] SIMR2.IICCSC, [0] SIMR2.IICINTM
0xD006B SCI11
  [7:6] SIMR3.IICSCLS, [5:4] SIMR3.IICSDAS, [3] SIMR3.IICSTIF, [2] SIMR3.IICSTPREQ, [1] SIMR3.IICRSTAREQ, [0] SIMR3.IICSTAREQ
0xD006C SCI11
  [0] SISR.IICACKR
0xD006D SCI11
  [7] SPMR.CKPH, [6] SPMR.CKPOL, [4] SPMR.MFF, [2] SPMR.MSS, [1] SPMR.CTSE, [0] SPMR.SSE
0xD006E SCI11 16-bit
  [9] FTDR.MPBT, [8:0] FTDR.TDAT
0xD0070 SCI11 16-bit
  [14] FRDR.RDF, [13] FRDR.ORER, [12] FRDR.FER, [11] FRDR.PER, [10] FRDR.DR, [9] FRDR.MPB, [8:0] FRDR.RDAT
0xD0073 SCI11
  [7] DCCR.DCME, [6] DCCR.IDSEL, [4] DCCR.DFER, [3] DCCR.DPER, [0] DCCR.DCMF
0xD0074 SCI11 16-bit
  [15:12] FCR.RSTRG, [11:8] FCR.RTRG, [7:4] FCR.TTRG, [3] FCR.DRES, [2] FCR.TFRST, [1] FCR.RFRST, [0] FCR.FM
0xD0076 SCI11 16-bit
  [12:8] FDR.T, [4:0] FDR.R
0xD0078 SCI11 16-bit
  [12:8] LSR.PNUM, [6:2] LSR.FNUM, [0] LSR.ORER
0xD007A SCI11 16-bit
  [8:0] CDR.CMPD
0xD007C SCI11
  [2] SPTR.SPB2IO, [1] SPTR.SPB2DT, [0] SPTR.RXDMON
0xD0100 RSPI0
  [7] SPCR.SPRIE, [6] SPCR.SPE, [5] SPCR.SPTIE, [4] SPCR.SPEIE, [3] SPCR.MSTR, [2] SPCR.MODFEN, [1] SPCR.TXMD, [0] SPCR.SPMS
0xD0101 RSPI0
  [n] SSLP.SSL{n}P (n=0..3)
0xD0102 RSPI0
  [5] SPPCR.MOIFE, [4] SPPCR.MOIFV, [1] SPPCR.SPLP2, [0] SPPCR.SPLP
0xD0103 RSPI0
  [7] SPSR.SPRF, [5] SPSR.SPTEF, [4] SPSR.UDRF, [3] SPSR.PERF, [2] SPSR.MODF, [1] SPSR.IDLNF, [0] SPSR.OVRF
0xD0108 RSPI0
  [2:0] SPSCR.SPSLN
0xD0109 RSPI0
  [6:4] SPSSR.SPECM, [2:0] SPSSR.SPCP
0xD010B RSPI0
  [6] SPDCR.SPBYT, [5] SPDCR.SPLW, [4] SPDCR.SPRDTD, [1:0] SPDCR.SPFC
0xD010C RSPI0
  [2:0] SPCKD.SCKDL
0xD010D RSPI0
  [2:0] SSLND.SLNDL
0xD010E RSPI0
  [2:0] SPND.SPNDL
0xD010F RSPI0
  [4] SPCR2.SCKASE, [3] SPCR2.PTE, [2] SPCR2.SPIIE, [1] SPCR2.SPOE, [0] SPCR2.SPPE
0xD0110 RSPI0 16-bit
  [15] SPCMD0.SCKDEN, [14] SPCMD0.SLNDEN, [13] SPCMD0.SPNDEN, [12] SPCMD0.LSBF, [11:8] SPCMD0.SPB, [7] SPCMD0.SSLKP, [6:4] SPCMD0.SSLA, [3:2] SPCMD0.BRDV, [1] SPCMD0.CPOL, [0] SPCMD0.CPHA
0xD0112 RSPI0 16-bit
  [15] SPCMD1.SCKDEN, [14] SPCMD1.SLNDEN, [13] SPCMD1.SPNDEN, [12] SPCMD1.LSBF, [11:8] SPCMD1.SPB, [7] SPCMD1.SSLKP, [6:4] SPCMD1.SSLA, [3:2] SPCMD1.BRDV, [1] SPCMD1.CPOL, [0] SPCMD1.CPHA
0xD0114 RSPI0 16-bit
  [15] SPCMD2.SCKDEN, [14] SPCMD2.SLNDEN, [13] SPCMD2.SPNDEN, [12] SPCMD2.LSBF, [11:8] SPCMD2.SPB, [7] SPCMD2.SSLKP, [6:4] SPCMD2.SSLA, [3:2] SPCMD2.BRDV, [1] SPCMD2.CPOL, [0] SPCMD2.CPHA
0xD0116 RSPI0 16-bit
  [15] SPCMD3.SCKDEN, [14] SPCMD3.SLNDEN, [13] SPCMD3.SPNDEN, [12] SPCMD3.LSBF, [11:8] SPCMD3.SPB, [7] SPCMD3.SSLKP, [6:4] SPCMD3.SSLA, [3:2] SPCMD3.BRDV, [1] SPCMD3.CPOL, [0] SPCMD3.CPHA
0xD0118 RSPI0 16-bit
  [15] SPCMD4.SCKDEN, [14] SPCMD4.SLNDEN, [13] SPCMD4.SPNDEN, [12] SPCMD4.LSBF, [11:8] SPCMD4.SPB, [7] SPCMD4.SSLKP, [6:4] SPCMD4.SSLA, [3:2] SPCMD4.BRDV, [1] SPCMD4.CPOL, [0] SPCMD4.CPHA
0xD011A RSPI0 16-bit
  [15] SPCMD5.SCKDEN, [14] SPCMD5.SLNDEN, [13] SPCMD5.SPNDEN, [12] SPCMD5.LSBF, [11:8] SPCMD5.SPB, [7] SPCMD5.SSLKP, [6:4] SPCMD5.SSLA, [3:2] SPCMD5.BRDV, [1] SPCMD5.CPOL, [0] SPCMD5.CPHA
0xD011C RSPI0 16-bit
  [15] SPCMD6.SCKDEN, [14] SPCMD6.SLNDEN, [13] SPCMD6.SPNDEN, [12] SPCMD6.LSBF, [11:8] SPCMD6.SPB, [7] SPCMD6.SSLKP, [6:4] SPCMD6.SSLA, [3:2] SPCMD6.BRDV, [1] SPCMD6.CPOL, [0] SPCMD6.CPHA
0xD011E RSPI0 16-bit
  [15] SPCMD7.SCKDEN, [14] SPCMD7.SLNDEN, [13] SPCMD7.SPNDEN, [12] SPCMD7.LSBF, [11:8] SPCMD7.SPB, [7] SPCMD7.SSLKP, [6:4] SPCMD7.SSLA, [3:2] SPCMD7.BRDV, [1] SPCMD7.CPOL, [0] SPCMD7.CPHA
0xD0120 RSPI0
  [0] SPDCR2.BYSW
0xD0140 RSPI1
  fields as RSPI0
0xD0141 RSPI1
  [n] SSLP.SSL{n}P (n=0..3)
0xD0142 RSPI1
  [5] SPPCR.MOIFE, [4] SPPCR.MOIFV, [1] SPPCR.SPLP2, [0] SPPCR.SPLP
0xD0143 RSPI1
  [7] SPSR.SPRF, [5] SPSR.SPTEF, [4] SPSR.UDRF, [3] SPSR.PERF, [2] SPSR.MODF, [1] SPSR.IDLNF, [0] SPSR.OVRF
0xD0148 RSPI1
  [2:0] SPSCR.SPSLN
0xD0149 RSPI1
  [6:4] SPSSR.SPECM, [2:0] SPSSR.SPCP
0xD014B RSPI1
  [6] SPDCR.SPBYT, [5] SPDCR.SPLW, [4] SPDCR.SPRDTD, [1:0] SPDCR.SPFC
0xD014C RSPI1
  [2:0] SPCKD.SCKDL
0xD014D RSPI1
  [2:0] SSLND.SLNDL
0xD014E RSPI1
  [2:0] SPND.SPNDL
0xD014F RSPI1
  [4] SPCR2.SCKASE, [3] SPCR2.PTE, [2] SPCR2.SPIIE, [1] SPCR2.SPOE, [0] SPCR2.SPPE
0xD0150 RSPI1 16-bit
  [15] SPCMD0.SCKDEN, [14] SPCMD0.SLNDEN, [13] SPCMD0.SPNDEN, [12] SPCMD0.LSBF, [11:8] SPCMD0.SPB, [7] SPCMD0.SSLKP, [6:4] SPCMD0.SSLA, [3:2] SPCMD0.BRDV, [1] SPCMD0.CPOL, [0] SPCMD0.CPHA
0xD0152 RSPI1 16-bit
  [15] SPCMD1.SCKDEN, [14] SPCMD1.SLNDEN, [13] SPCMD1.SPNDEN, [12] SPCMD1.LSBF, [11:8] SPCMD1.SPB, [7] SPCMD1.SSLKP, [6:4] SPCMD1.SSLA, [3:2] SPCMD1.BRDV, [1] SPCMD1.CPOL, [0] SPCMD1.CPHA
0xD0154 RSPI1 16-bit
  [15] SPCMD2.SCKDEN, [14] SPCMD2.SLNDEN, [13] SPCMD2.SPNDEN, [12] SPCMD2.LSBF, [11:8] SPCMD2.SPB, [7] SPCMD2.SSLKP, [6:4] SPCMD2.SSLA, [3:2] SPCMD2.BRDV, [1] SPCMD2.CPOL, [0] SPCMD2.CPHA
0xD0156 RSPI1 16-bit
  [15] SPCMD3.SCKDEN, [14] SPCMD3.SLNDEN, [13] SPCMD3.SPNDEN, [12] SPCMD3.LSBF, [11:8] SPCMD3.SPB, [7] SPCMD3.SSLKP, [6:4] SPCMD3.SSLA, [3:2] SPCMD3.BRDV, [1] SPCMD3.CPOL, [0] SPCMD3.CPHA
0xD0158 RSPI1 16-bit
  [15] SPCMD4.SCKDEN, [14] SPCMD4.SLNDEN, [13] SPCMD4.SPNDEN, [12] SPCMD4.LSBF, [11:8] SPCMD4.SPB, [7] SPCMD4.SSLKP, [6:4] SPCMD4.SSLA, [3:2] SPCMD4.BRDV, [1] SPCMD4.CPOL, [0] SPCMD4.CPHA
0xD015A RSPI1 16-bit
  [15] SPCMD5.SCKDEN, [14] SPCMD5.SLNDEN, [13] SPCMD5.SPNDEN, [12] SPCMD5.LSBF, [11:8] SPCMD5.SPB, [7] SPCMD5.SSLKP, [6:4] SPCMD5.SSLA, [3:2] SPCMD5.BRDV, [1] SPCMD5.CPOL, [0] SPCMD5.CPHA
0xD015C RSPI1 16-bit
  [15] SPCMD6.SCKDEN, [14] SPCMD6.SLNDEN, [13] SPCMD6.SPNDEN, [12] SPCMD6.LSBF, [11:8] SPCMD6.SPB, [7] SPCMD6.SSLKP, [6:4] SPCMD6.SSLA, [3:2] SPCMD6.BRDV, [1] SPCMD6.CPOL, [0] SPCMD6.CPHA
0xD015E RSPI1 16-bit
  [15] SPCMD7.SCKDEN, [14] SPCMD7.SLNDEN, [13] SPCMD7.SPNDEN, [12] SPCMD7.LSBF, [11:8] SPCMD7.SPB, [7] SPCMD7.SSLKP, [6:4] SPCMD7.SSLA, [3:2] SPCMD7.BRDV, [1] SPCMD7.CPOL, [0] SPCMD7.CPHA
0xD0160 RSPI1
  [0] SPDCR2.BYSW
0xD0300 RSPI2
  fields as RSPI0
0xD0301 RSPI2
  [n] SSLP.SSL{n}P (n=0..3)
0xD0302 RSPI2
  [5] SPPCR.MOIFE, [4] SPPCR.MOIFV, [1] SPPCR.SPLP2, [0] SPPCR.SPLP
0xD0303 RSPI2
  [7] SPSR.SPRF, [5] SPSR.SPTEF, [4] SPSR.UDRF, [3] SPSR.PERF, [2] SPSR.MODF, [1] SPSR.IDLNF, [0] SPSR.OVRF
0xD0308 RSPI2
  [2:0] SPSCR.SPSLN
0xD0309 RSPI2
  [6:4] SPSSR.SPECM, [2:0] SPSSR.SPCP
0xD030B RSPI2
  [6] SPDCR.SPBYT, [5] SPDCR.SPLW, [4] SPDCR.SPRDTD, [1:0] SPDCR.SPFC
0xD030C RSPI2
  [2:0] SPCKD.SCKDL
0xD030D RSPI2
  [2:0] SSLND.SLNDL
0xD030E RSPI2
  [2:0] SPND.SPNDL
0xD030F RSPI2
  [4] SPCR2.SCKASE, [3] SPCR2.PTE, [2] SPCR2.SPIIE, [1] SPCR2.SPOE, [0] SPCR2.SPPE
0xD0310 RSPI2 16-bit
  [15] SPCMD0.SCKDEN, [14] SPCMD0.SLNDEN, [13] SPCMD0.SPNDEN, [12] SPCMD0.LSBF, [11:8] SPCMD0.SPB, [7] SPCMD0.SSLKP, [6:4] SPCMD0.SSLA, [3:2] SPCMD0.BRDV, [1] SPCMD0.CPOL, [0] SPCMD0.CPHA
0xD0312 RSPI2 16-bit
  [15] SPCMD1.SCKDEN, [14] SPCMD1.SLNDEN, [13] SPCMD1.SPNDEN, [12] SPCMD1.LSBF, [11:8] SPCMD1.SPB, [7] SPCMD1.SSLKP, [6:4] SPCMD1.SSLA, [3:2] SPCMD1.BRDV, [1] SPCMD1.CPOL, [0] SPCMD1.CPHA
0xD0314 RSPI2 16-bit
  [15] SPCMD2.SCKDEN, [14] SPCMD2.SLNDEN, [13] SPCMD2.SPNDEN, [12] SPCMD2.LSBF, [11:8] SPCMD2.SPB, [7] SPCMD2.SSLKP, [6:4] SPCMD2.SSLA, [3:2] SPCMD2.BRDV, [1] SPCMD2.CPOL, [0] SPCMD2.CPHA
0xD0316 RSPI2 16-bit
  [15] SPCMD3.SCKDEN, [14] SPCMD3.SLNDEN, [13] SPCMD3.SPNDEN, [12] SPCMD3.LSBF, [11:8] SPCMD3.SPB, [7] SPCMD3.SSLKP, [6:4] SPCMD3.SSLA, [3:2] SPCMD3.BRDV, [1] SPCMD3.CPOL, [0] SPCMD3.CPHA
0xD0318 RSPI2 16-bit
  [15] SPCMD4.SCKDEN, [14] SPCMD4.SLNDEN, [13] SPCMD4.SPNDEN, [12] SPCMD4.LSBF, [11:8] SPCMD4.SPB, [7] SPCMD4.SSLKP, [6:4] SPCMD4.SSLA, [3:2] SPCMD4.BRDV, [1] SPCMD4.CPOL, [0] SPCMD4.CPHA
0xD031A RSPI2 16-bit
  [15] SPCMD5.SCKDEN, [14] SPCMD5.SLNDEN, [13] SPCMD5.SPNDEN, [12] SPCMD5.LSBF, [11:8] SPCMD5.SPB, [7] SPCMD5.SSLKP, [6:4] SPCMD5.SSLA, [3:2] SPCMD5.BRDV, [1] SPCMD5.CPOL, [0] SPCMD5.CPHA
0xD031C RSPI2 16-bit
  [15] SPCMD6.SCKDEN, [14] SPCMD6.SLNDEN, [13] SPCMD6.SPNDEN, [12] SPCMD6.LSBF, [11:8] SPCMD6.SPB, [7] SPCMD6.SSLKP, [6:4] SPCMD6.SSLA, [3:2] SPCMD6.BRDV, [1] SPCMD6.CPOL, [0] SPCMD6.CPHA
0xD031E RSPI2 16-bit
  [15] SPCMD7.SCKDEN, [14] SPCMD7.SLNDEN, [13] SPCMD7.SPNDEN, [12] SPCMD7.LSBF, [11:8] SPCMD7.SPB, [7] SPCMD7.SSLKP, [6:4] SPCMD7.SSLA, [3:2] SPCMD7.BRDV, [1] SPCMD7.CPOL, [0] SPCMD7.CPHA
0xD0320 RSPI2
  [0] SPDCR2.BYSW
0xE0000 GLCDC 32-bit
  [31:24] GR1CLUT0[0].A, [23:16] GR1CLUT0[0].R, [15:8] GR1CLUT0[0].G, [7:0] GR1CLUT0[0].B
0xE0004 GLCDC 32-bit
  [31:24] GR1CLUT0[1].A, [23:16] GR1CLUT0[1].R, [15:8] GR1CLUT0[1].G, [7:0] GR1CLUT0[1].B
0xE0008 GLCDC 32-bit
  [31:24] GR1CLUT0[2].A, [23:16] GR1CLUT0[2].R, [15:8] GR1CLUT0[2].G, [7:0] GR1CLUT0[2].B
0xE000C GLCDC 32-bit
  [31:24] GR1CLUT0[3].A, [23:16] GR1CLUT0[3].R, [15:8] GR1CLUT0[3].G, [7:0] GR1CLUT0[3].B
0xE0010 GLCDC 32-bit
  [31:24] GR1CLUT0[4].A, [23:16] GR1CLUT0[4].R, [15:8] GR1CLUT0[4].G, [7:0] GR1CLUT0[4].B
0xE0014 GLCDC 32-bit
  [31:24] GR1CLUT0[5].A, [23:16] GR1CLUT0[5].R, [15:8] GR1CLUT0[5].G, [7:0] GR1CLUT0[5].B
0xE0018 GLCDC 32-bit
  [31:24] GR1CLUT0[6].A, [23:16] GR1CLUT0[6].R, [15:8] GR1CLUT0[6].G, [7:0] GR1CLUT0[6].B
0xE001C GLCDC 32-bit
  [31:24] GR1CLUT0[7].A, [23:16] GR1CLUT0[7].R, [15:8] GR1CLUT0[7].G, [7:0] GR1CLUT0[7].B
0xE0020 GLCDC 32-bit
  [31:24] GR1CLUT0[8].A, [23:16] GR1CLUT0[8].R, [15:8] GR1CLUT0[8].G, [7:0] GR1CLUT0[8].B
0xE0024 GLCDC 32-bit
  [31:24] GR1CLUT0[9].A, [23:16] GR1CLUT0[9].R, [15:8] GR1CLUT0[9].G, [7:0] GR1CLUT0[9].B
0xE0028 GLCDC 32-bit
  [31:24] GR1CLUT0[10].A, [23:16] GR1CLUT0[10].R, [15:8] GR1CLUT0[10].G, [7:0] GR1CLUT0[10].B
0xE002C GLCDC 32-bit
  [31:24] GR1CLUT0[11].A, [23:16] GR1CLUT0[11].R, [15:8] GR1CLUT0[11].G, [7:0] GR1CLUT0[11].B
0xE0030 GLCDC 32-bit
  [31:24] GR1CLUT0[12].A, [23:16] GR1CLUT0[12].R, [15:8] GR1CLUT0[12].G, [7:0] GR1CLUT0[12].B
0xE0034 GLCDC 32-bit
  [31:24] GR1CLUT0[13].A, [23:16] GR1CLUT0[13].R, [15:8] GR1CLUT0[13].G, [7:0] GR1CLUT0[13].B
0xE0038 GLCDC 32-bit
  [31:24] GR1CLUT0[14].A, [23:16] GR1CLUT0[14].R, [15:8] GR1CLUT0[14].G, [7:0] GR1CLUT0[14].B
0xE003C GLCDC 32-bit
  [31:24] GR1CLUT0[15].A, [23:16] GR1CLUT0[15].R, [15:8] GR1CLUT0[15].G, [7:0] GR1CLUT0[15].B
0xE0040 GLCDC 32-bit
  [31:24] GR1CLUT0[16].A, [23:16] GR1CLUT0[16].R, [15:8] GR1CLUT0[16].G, [7:0] GR1CLUT0[16].B
0xE0044 GLCDC 32-bit
  [31:24] GR1CLUT0[17].A, [23:16] GR1CLUT0[17].R, [15:8] GR1CLUT0[17].G, [7:0] GR1CLUT0[17].B
0xE0048 GLCDC 32-bit
  [31:24] GR1CLUT0[18].A, [23:16] GR1CLUT0[18].R, [15:8] GR1CLUT0[18].G, [7:0] GR1CLUT0[18].B
0xE004C GLCDC 32-bit
  [31:24] GR1CLUT0[19].A, [23:16] GR1CLUT0[19].R, [15:8] GR1CLUT0[19].G, [7:0] GR1CLUT0[19].B
0xE0050 GLCDC 32-bit
  [31:24] GR1CLUT0[20].A, [23:16] GR1CLUT0[20].R, [15:8] GR1CLUT0[20].G, [7:0] GR1CLUT0[20].B
0xE0054 GLCDC 32-bit
  [31:24] GR1CLUT0[21].A, [23:16] GR1CLUT0[21].R, [15:8] GR1CLUT0[21].G, [7:0] GR1CLUT0[21].B
0xE0058 GLCDC 32-bit
  [31:24] GR1CLUT0[22].A, [23:16] GR1CLUT0[22].R, [15:8] GR1CLUT0[22].G, [7:0] GR1CLUT0[22].B
0xE005C GLCDC 32-bit
  [31:24] GR1CLUT0[23].A, [23:16] GR1CLUT0[23].R, [15:8] GR1CLUT0[23].G, [7:0] GR1CLUT0[23].B
0xE0060 GLCDC 32-bit
  [31:24] GR1CLUT0[24].A, [23:16] GR1CLUT0[24].R, [15:8] GR1CLUT0[24].G, [7:0] GR1CLUT0[24].B
0xE0064 GLCDC 32-bit
  [31:24] GR1CLUT0[25].A, [23:16] GR1CLUT0[25].R, [15:8] GR1CLUT0[25].G, [7:0] GR1CLUT0[25].B
0xE0068 GLCDC 32-bit
  [31:24] GR1CLUT0[26].A, [23:16] GR1CLUT0[26].R, [15:8] GR1CLUT0[26].G, [7:0] GR1CLUT0[26].B
0xE006C GLCDC 32-bit
  [31:24] GR1CLUT0[27].A, [23:16] GR1CLUT0[27].R, [15:8] GR1CLUT0[27].G, [7:0] GR1CLUT0[27].B
0xE0070 GLCDC 32-bit
  [31:24] GR1CLUT0[28].A, [23:16] GR1CLUT0[28].R, [15:8] GR1CLUT0[28].G, [7:0] GR1CLUT0[28].B
0xE0074 GLCDC 32-bit
  [31:24] GR1CLUT0[29].A, [23:16] GR1CLUT0[29].R, [15:8] GR1CLUT0[29].G, [7:0] GR1CLUT0[29].B
0xE0078 GLCDC 32-bit
  [31:24] GR1CLUT0[30].A, [23:16] GR1CLUT0[30].R, [15:8] GR1CLUT0[30].G, [7:0] GR1CLUT0[30].B
0xE007C GLCDC 32-bit
  [31:24] GR1CLUT0[31].A, [23:16] GR1CLUT0[31].R, [15:8] GR1CLUT0[31].G, [7:0] GR1CLUT0[31].B
0xE0080 GLCDC 32-bit
  [31:24] GR1CLUT0[32].A, [23:16] GR1CLUT0[32].R, [15:8] GR1CLUT0[32].G, [7:0] GR1CLUT0[32].B
0xE0084 GLCDC 32-bit
  [31:24] GR1CLUT0[33].A, [23:16] GR1CLUT0[33].R, [15:8] GR1CLUT0[33].G, [7:0] GR1CLUT0[33].B
0xE0088 GLCDC 32-bit
  [31:24] GR1CLUT0[34].A, [23:16] GR1CLUT0[34].R, [15:8] GR1CLUT0[34].G, [7:0] GR1CLUT0[34].B
0xE008C GLCDC 32-bit
  [31:24] GR1CLUT0[35].A, [23:16] GR1CLUT0[35].R, [15:8] GR1CLUT0[35].G, [7:0] GR1CLUT0[35].B
0xE0090 GLCDC 32-bit
  [31:24] GR1CLUT0[36].A, [23:16] GR1CLUT0[36].R, [15:8] GR1CLUT0[36].G, [7:0] GR1CLUT0[36].B
0xE0094 GLCDC 32-bit
  [31:24] GR1CLUT0[37].A, [23:16] GR1CLUT0[37].R, [15:8] GR1CLUT0[37].G, [7:0] GR1CLUT0[37].B
0xE0098 GLCDC 32-bit
  [31:24] GR1CLUT0[38].A, [23:16] GR1CLUT0[38].R, [15:8] GR1CLUT0[38].G, [7:0] GR1CLUT0[38].B
0xE009C GLCDC 32-bit
  [31:24] GR1CLUT0[39].A, [23:16] GR1CLUT0[39].R, [15:8] GR1CLUT0[39].G, [7:0] GR1CLUT0[39].B
0xE00A0 GLCDC 32-bit
  [31:24] GR1CLUT0[40].A, [23:16] GR1CLUT0[40].R, [15:8] GR1CLUT0[40].G, [7:0] GR1CLUT0[40].B
0xE00A4 GLCDC 32-bit
  [31:24] GR1CLUT0[41].A, [23:16] GR1CLUT0[41].R, [15:8] GR1CLUT0[41].G, [7:0] GR1CLUT0[41].B
0xE00A8 GLCDC 32-bit
  [31:24] GR1CLUT0[42].A, [23:16] GR1CLUT0[42].R, [15:8] GR1CLUT0[42].G, [7:0] GR1CLUT0[42].B
0xE00AC GLCDC 32-bit
  [31:24] GR1CLUT0[43].A, [23:16] GR1CLUT0[43].R, [15:8] GR1CLUT0[43].G, [7:0] GR1CLUT0[43].B
0xE00B0 GLCDC 32-bit
  [31:24] GR1CLUT0[44].A, [23:16] GR1CLUT0[44].R, [15:8] GR1CLUT0[44].G, [7:0] GR1CLUT0[44].B
0xE00B4 GLCDC 32-bit
  [31:24] GR1CLUT0[45].A, [23:16] GR1CLUT0[45].R, [15:8] GR1CLUT0[45].G, [7:0] GR1CLUT0[45].B
0xE00B8 GLCDC 32-bit
  [31:24] GR1CLUT0[46].A, [23:16] GR1CLUT0[46].R, [15:8] GR1CLUT0[46].G, [7:0] GR1CLUT0[46].B
0xE00BC GLCDC 32-bit
  [31:24] GR1CLUT0[47].A, [23:16] GR1CLUT0[47].R, [15:8] GR1CLUT0[47].G, [7:0] GR1CLUT0[47].B
0xE00C0 GLCDC 32-bit
  [31:24] GR1CLUT0[48].A, [23:16] GR1CLUT0[48].R, [15:8] GR1CLUT0[48].G, [7:0] GR1CLUT0[48].B
0xE00C4 GLCDC 32-bit
  [31:24] GR1CLUT0[49].A, [23:16] GR1CLUT0[49].R, [15:8] GR1CLUT0[49].G, [7:0] GR1CLUT0[49].B
0xE00C8 GLCDC 32-bit
  [31:24] GR1CLUT0[50].A, [23:16] GR1CLUT0[50].R, [15:8] GR1CLUT0[50].G, [7:0] GR1CLUT0[50].B
0xE00CC GLCDC 32-bit
  [31:24] GR1CLUT0[51].A, [23:16] GR1CLUT0[51].R, [15:8] GR1CLUT0[51].G, [7:0] GR1CLUT0[51].B
0xE00D0 GLCDC 32-bit
  [31:24] GR1CLUT0[52].A, [23:16] GR1CLUT0[52].R, [15:8] GR1CLUT0[52].G, [7:0] GR1CLUT0[52].B
0xE00D4 GLCDC 32-bit
  [31:24] GR1CLUT0[53].A, [23:16] GR1CLUT0[53].R, [15:8] GR1CLUT0[53].G, [7:0] GR1CLUT0[53].B
0xE00D8 GLCDC 32-bit
  [31:24] GR1CLUT0[54].A, [23:16] GR1CLUT0[54].R, [15:8] GR1CLUT0[54].G, [7:0] GR1CLUT0[54].B
0xE00DC GLCDC 32-bit
  [31:24] GR1CLUT0[55].A, [23:16] GR1CLUT0[55].R, [15:8] GR1CLUT0[55].G, [7:0] GR1CLUT0[55].B
0xE00E0 GLCDC 32-bit
  [31:24] GR1CLUT0[56].A, [23:16] GR1CLUT0[56].R, [15:8] GR1CLUT0[56].G, [7:0] GR1CLUT0[56].B
0xE00E4 GLCDC 32-bit
  [31:24] GR1CLUT0[57].A, [23:16] GR1CLUT0[57].R, [15:8] GR1CLUT0[57].G, [7:0] GR1CLUT0[57].B
0xE00E8 GLCDC 32-bit
  [31:24] GR1CLUT0[58].A, [23:16] GR1CLUT0[58].R, [15:8] GR1CLUT0[58].G, [7:0] GR1CLUT0[58].B
0xE00EC GLCDC 32-bit
  [31:24] GR1CLUT0[59].A, [23:16] GR1CLUT0[59].R, [15:8] GR1CLUT0[59].G, [7:0] GR1CLUT0[59].B
0xE00F0 GLCDC 32-bit
  [31:24] GR1CLUT0[60].A, [23:16] GR1CLUT0[60].R, [15:8] GR1CLUT0[60].G, [7:0] GR1CLUT0[60].B
